VERSION 5.8 ;
BUSBITCHARS "[]" ;
DIVIDERCHAR "/" ;
UNITS
    DATABASE MICRONS 1000 ;
END UNITS

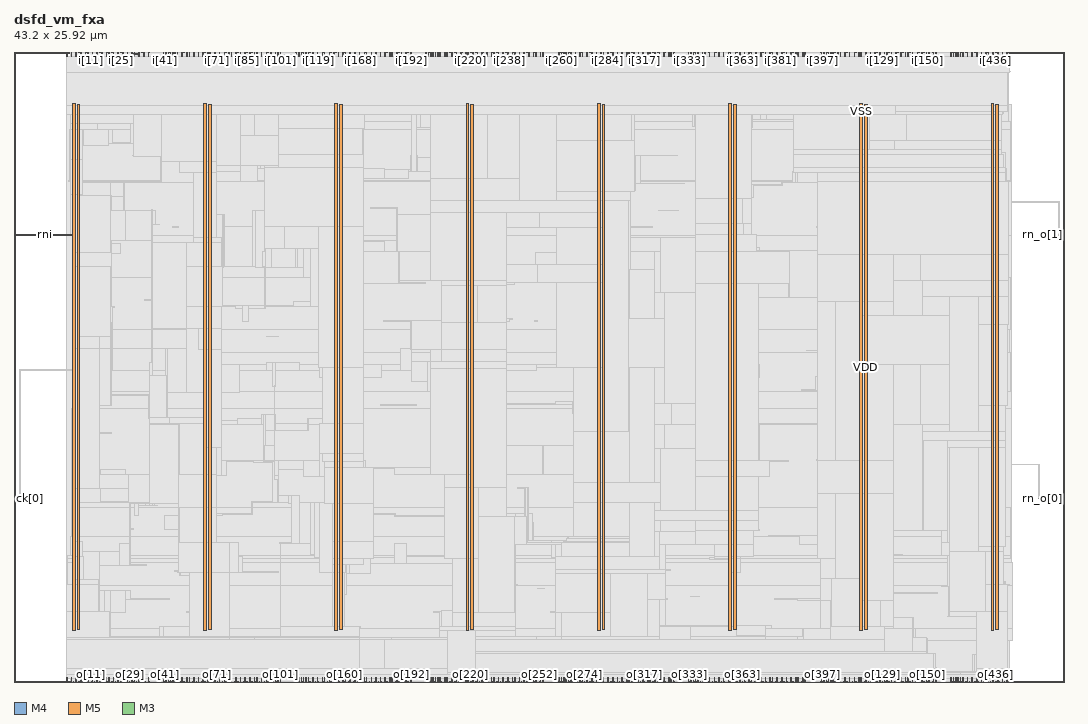
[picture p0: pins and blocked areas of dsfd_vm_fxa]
MACRO dsfd_vm_fxa
  FOREIGN dsfd_vm_fxa 0 0 ;
  CLASS BLOCK ;
  SIZE 43.2 BY 25.92 ;
  PIN ck[0]
    DIRECTION INPUT ;
    USE SIGNAL ;
    PORT
      LAYER M4 ;
        RECT  0 7.536 0.192 7.56 ;
    END
    PORT
      LAYER M4 ;
        RECT  0.156 7.536 0.275 7.56 ;
    END
  END ck[0]
  PIN i[0]
    DIRECTION INPUT ;
    USE SIGNAL ;
    PORT
      LAYER M5 ;
        RECT  2.16 25.728 2.184 25.92 ;
    END
  END i[0]
  PIN i[100]
    DIRECTION INPUT ;
    USE SIGNAL ;
    PORT
      LAYER M5 ;
        RECT  10.848 25.728 10.872 25.92 ;
    END
  END i[100]
  PIN i[101]
    DIRECTION INPUT ;
    USE SIGNAL ;
    PORT
      LAYER M3 ;
        RECT  10.944 25.882 10.962 25.92 ;
    END
  END i[101]
  PIN i[102]
    DIRECTION INPUT ;
    USE SIGNAL ;
    PORT
      LAYER M5 ;
        RECT  10.944 25.728 10.968 25.92 ;
    END
  END i[102]
  PIN i[103]
    DIRECTION INPUT ;
    USE SIGNAL ;
    PORT
      LAYER M3 ;
        RECT  11.592 25.882 11.61 25.92 ;
    END
  END i[103]
  PIN i[104]
    DIRECTION INPUT ;
    USE SIGNAL ;
    PORT
      LAYER M5 ;
        RECT  11.616 25.728 11.64 25.92 ;
    END
  END i[104]
  PIN i[105]
    DIRECTION INPUT ;
    USE SIGNAL ;
    PORT
      LAYER M3 ;
        RECT  11.664 25.882 11.682 25.92 ;
    END
  END i[105]
  PIN i[106]
    DIRECTION INPUT ;
    USE SIGNAL ;
    PORT
      LAYER M5 ;
        RECT  11.712 25.728 11.736 25.92 ;
    END
  END i[106]
  PIN i[107]
    DIRECTION INPUT ;
    USE SIGNAL ;
    PORT
      LAYER M3 ;
        RECT  11.736 25.882 11.754 25.92 ;
    END
  END i[107]
  PIN i[108]
    DIRECTION INPUT ;
    USE SIGNAL ;
    PORT
      LAYER M5 ;
        RECT  11.808 25.728 11.832 25.92 ;
    END
  END i[108]
  PIN i[109]
    DIRECTION INPUT ;
    USE SIGNAL ;
    PORT
      LAYER M3 ;
        RECT  11.808 25.882 11.826 25.92 ;
    END
  END i[109]
  PIN i[10]
    DIRECTION INPUT ;
    USE SIGNAL ;
    PORT
      LAYER M5 ;
        RECT  3.024 25.728 3.048 25.92 ;
    END
  END i[10]
  PIN i[110]
    DIRECTION INPUT ;
    USE SIGNAL ;
    PORT
      LAYER M5 ;
        RECT  11.904 25.728 11.928 25.92 ;
    END
  END i[110]
  PIN i[111]
    DIRECTION INPUT ;
    USE SIGNAL ;
    PORT
      LAYER M3 ;
        RECT  11.88 25.882 11.898 25.92 ;
    END
  END i[111]
  PIN i[112]
    DIRECTION INPUT ;
    USE SIGNAL ;
    PORT
      LAYER M5 ;
        RECT  12 25.728 12.024 25.92 ;
    END
  END i[112]
  PIN i[113]
    DIRECTION INPUT ;
    USE SIGNAL ;
    PORT
      LAYER M3 ;
        RECT  12.024 25.882 12.042 25.92 ;
    END
  END i[113]
  PIN i[114]
    DIRECTION INPUT ;
    USE SIGNAL ;
    PORT
      LAYER M5 ;
        RECT  12.096 25.728 12.12 25.92 ;
    END
  END i[114]
  PIN i[115]
    DIRECTION INPUT ;
    USE SIGNAL ;
    PORT
      LAYER M3 ;
        RECT  12.168 25.882 12.186 25.92 ;
    END
  END i[115]
  PIN i[116]
    DIRECTION INPUT ;
    USE SIGNAL ;
    PORT
      LAYER M5 ;
        RECT  12.288 25.728 12.312 25.92 ;
    END
  END i[116]
  PIN i[117]
    DIRECTION INPUT ;
    USE SIGNAL ;
    PORT
      LAYER M3 ;
        RECT  12.384 25.882 12.402 25.92 ;
    END
  END i[117]
  PIN i[118]
    DIRECTION INPUT ;
    USE SIGNAL ;
    PORT
      LAYER M5 ;
        RECT  12.48 25.728 12.504 25.92 ;
    END
  END i[118]
  PIN i[119]
    DIRECTION INPUT ;
    USE SIGNAL ;
    PORT
      LAYER M3 ;
        RECT  12.528 25.882 12.546 25.92 ;
    END
  END i[119]
  PIN i[11]
    DIRECTION INPUT ;
    USE SIGNAL ;
    PORT
      LAYER M3 ;
        RECT  3.168 25.882 3.186 25.92 ;
    END
  END i[11]
  PIN i[120]
    DIRECTION INPUT ;
    USE SIGNAL ;
    PORT
      LAYER M5 ;
        RECT  12.672 25.728 12.696 25.92 ;
    END
  END i[120]
  PIN i[121]
    DIRECTION INPUT ;
    USE SIGNAL ;
    PORT
      LAYER M3 ;
        RECT  12.744 25.882 12.762 25.92 ;
    END
  END i[121]
  PIN i[122]
    DIRECTION INPUT ;
    USE SIGNAL ;
    PORT
      LAYER M5 ;
        RECT  12.768 25.728 12.792 25.92 ;
    END
  END i[122]
  PIN i[123]
    DIRECTION INPUT ;
    USE SIGNAL ;
    PORT
      LAYER M3 ;
        RECT  12.888 25.882 12.906 25.92 ;
    END
  END i[123]
  PIN i[124]
    DIRECTION INPUT ;
    USE SIGNAL ;
    PORT
      LAYER M5 ;
        RECT  12.96 25.728 12.984 25.92 ;
    END
  END i[124]
  PIN i[125]
    DIRECTION INPUT ;
    USE SIGNAL ;
    PORT
      LAYER M3 ;
        RECT  13.032 25.882 13.05 25.92 ;
    END
  END i[125]
  PIN i[126]
    DIRECTION INPUT ;
    USE SIGNAL ;
    PORT
      LAYER M5 ;
        RECT  13.152 25.728 13.176 25.92 ;
    END
  END i[126]
  PIN i[127]
    DIRECTION INPUT ;
    USE SIGNAL ;
    PORT
      LAYER M3 ;
        RECT  13.248 25.882 13.266 25.92 ;
    END
  END i[127]
  PIN i[128]
    DIRECTION INPUT ;
    USE SIGNAL ;
    PORT
      LAYER M5 ;
        RECT  35.616 25.728 35.64 25.92 ;
    END
  END i[128]
  PIN i[129]
    DIRECTION INPUT ;
    USE SIGNAL ;
    PORT
      LAYER M3 ;
        RECT  35.712 25.882 35.73 25.92 ;
    END
  END i[129]
  PIN i[12]
    DIRECTION INPUT ;
    USE SIGNAL ;
    PORT
      LAYER M5 ;
        RECT  3.216 25.728 3.24 25.92 ;
    END
  END i[12]
  PIN i[130]
    DIRECTION INPUT ;
    USE SIGNAL ;
    PORT
      LAYER M5 ;
        RECT  35.808 25.728 35.832 25.92 ;
    END
  END i[130]
  PIN i[131]
    DIRECTION INPUT ;
    USE SIGNAL ;
    PORT
      LAYER M3 ;
        RECT  35.856 25.882 35.874 25.92 ;
    END
  END i[131]
  PIN i[132]
    DIRECTION INPUT ;
    USE SIGNAL ;
    PORT
      LAYER M5 ;
        RECT  35.904 25.728 35.928 25.92 ;
    END
  END i[132]
  PIN i[133]
    DIRECTION INPUT ;
    USE SIGNAL ;
    PORT
      LAYER M3 ;
        RECT  36 25.882 36.018 25.92 ;
    END
  END i[133]
  PIN i[134]
    DIRECTION INPUT ;
    USE SIGNAL ;
    PORT
      LAYER M5 ;
        RECT  36.096 25.728 36.12 25.92 ;
    END
  END i[134]
  PIN i[135]
    DIRECTION INPUT ;
    USE SIGNAL ;
    PORT
      LAYER M3 ;
        RECT  36.216 25.882 36.234 25.92 ;
    END
  END i[135]
  PIN i[136]
    DIRECTION INPUT ;
    USE SIGNAL ;
    PORT
      LAYER M5 ;
        RECT  36.288 25.728 36.312 25.92 ;
    END
  END i[136]
  PIN i[137]
    DIRECTION INPUT ;
    USE SIGNAL ;
    PORT
      LAYER M3 ;
        RECT  36.36 25.882 36.378 25.92 ;
    END
  END i[137]
  PIN i[138]
    DIRECTION INPUT ;
    USE SIGNAL ;
    PORT
      LAYER M5 ;
        RECT  36.48 25.728 36.504 25.92 ;
    END
  END i[138]
  PIN i[139]
    DIRECTION INPUT ;
    USE SIGNAL ;
    PORT
      LAYER M3 ;
        RECT  36.576 25.882 36.594 25.92 ;
    END
  END i[139]
  PIN i[13]
    DIRECTION INPUT ;
    USE SIGNAL ;
    PORT
      LAYER M3 ;
        RECT  3.312 25.882 3.33 25.92 ;
    END
  END i[13]
  PIN i[140]
    DIRECTION INPUT ;
    USE SIGNAL ;
    PORT
      LAYER M5 ;
        RECT  36.672 25.728 36.696 25.92 ;
    END
  END i[140]
  PIN i[141]
    DIRECTION INPUT ;
    USE SIGNAL ;
    PORT
      LAYER M3 ;
        RECT  36.72 25.882 36.738 25.92 ;
    END
  END i[141]
  PIN i[142]
    DIRECTION INPUT ;
    USE SIGNAL ;
    PORT
      LAYER M5 ;
        RECT  36.768 25.728 36.792 25.92 ;
    END
  END i[142]
  PIN i[143]
    DIRECTION INPUT ;
    USE SIGNAL ;
    PORT
      LAYER M5 ;
        RECT  36.96 25.728 36.984 25.92 ;
    END
  END i[143]
  PIN i[144]
    DIRECTION INPUT ;
    USE SIGNAL ;
    PORT
      LAYER M3 ;
        RECT  37.08 25.882 37.098 25.92 ;
    END
  END i[144]
  PIN i[145]
    DIRECTION INPUT ;
    USE SIGNAL ;
    PORT
      LAYER M5 ;
        RECT  37.152 25.728 37.176 25.92 ;
    END
  END i[145]
  PIN i[146]
    DIRECTION INPUT ;
    USE SIGNAL ;
    PORT
      LAYER M3 ;
        RECT  37.224 25.882 37.242 25.92 ;
    END
  END i[146]
  PIN i[147]
    DIRECTION INPUT ;
    USE SIGNAL ;
    PORT
      LAYER M5 ;
        RECT  37.344 25.728 37.368 25.92 ;
    END
  END i[147]
  PIN i[148]
    DIRECTION INPUT ;
    USE SIGNAL ;
    PORT
      LAYER M3 ;
        RECT  37.44 25.882 37.458 25.92 ;
    END
  END i[148]
  PIN i[149]
    DIRECTION INPUT ;
    USE SIGNAL ;
    PORT
      LAYER M5 ;
        RECT  37.536 25.728 37.56 25.92 ;
    END
  END i[149]
  PIN i[14]
    DIRECTION INPUT ;
    USE SIGNAL ;
    PORT
      LAYER M5 ;
        RECT  3.408 25.728 3.432 25.92 ;
    END
  END i[14]
  PIN i[150]
    DIRECTION INPUT ;
    USE SIGNAL ;
    PORT
      LAYER M3 ;
        RECT  37.584 25.882 37.602 25.92 ;
    END
  END i[150]
  PIN i[151]
    DIRECTION INPUT ;
    USE SIGNAL ;
    PORT
      LAYER M5 ;
        RECT  37.632 25.728 37.656 25.92 ;
    END
  END i[151]
  PIN i[152]
    DIRECTION INPUT ;
    USE SIGNAL ;
    PORT
      LAYER M3 ;
        RECT  37.8 25.882 37.818 25.92 ;
    END
  END i[152]
  PIN i[153]
    DIRECTION INPUT ;
    USE SIGNAL ;
    PORT
      LAYER M5 ;
        RECT  37.824 25.728 37.848 25.92 ;
    END
  END i[153]
  PIN i[154]
    DIRECTION INPUT ;
    USE SIGNAL ;
    PORT
      LAYER M3 ;
        RECT  37.944 25.882 37.962 25.92 ;
    END
  END i[154]
  PIN i[155]
    DIRECTION INPUT ;
    USE SIGNAL ;
    PORT
      LAYER M5 ;
        RECT  37.92 25.728 37.944 25.92 ;
    END
  END i[155]
  PIN i[156]
    DIRECTION INPUT ;
    USE SIGNAL ;
    PORT
      LAYER M3 ;
        RECT  38.592 25.882 38.61 25.92 ;
    END
  END i[156]
  PIN i[157]
    DIRECTION INPUT ;
    USE SIGNAL ;
    PORT
      LAYER M5 ;
        RECT  13.344 25.728 13.368 25.92 ;
    END
  END i[157]
  PIN i[158]
    DIRECTION INPUT ;
    USE SIGNAL ;
    PORT
      LAYER M3 ;
        RECT  13.392 25.882 13.41 25.92 ;
    END
  END i[158]
  PIN i[159]
    DIRECTION INPUT ;
    USE SIGNAL ;
    PORT
      LAYER M5 ;
        RECT  13.536 25.728 13.56 25.92 ;
    END
  END i[159]
  PIN i[15]
    DIRECTION INPUT ;
    USE SIGNAL ;
    PORT
      LAYER M3 ;
        RECT  3.528 25.882 3.546 25.92 ;
    END
  END i[15]
  PIN i[160]
    DIRECTION INPUT ;
    USE SIGNAL ;
    PORT
      LAYER M3 ;
        RECT  13.608 25.882 13.626 25.92 ;
    END
  END i[160]
  PIN i[161]
    DIRECTION INPUT ;
    USE SIGNAL ;
    PORT
      LAYER M5 ;
        RECT  13.632 25.728 13.656 25.92 ;
    END
  END i[161]
  PIN i[162]
    DIRECTION INPUT ;
    USE SIGNAL ;
    PORT
      LAYER M3 ;
        RECT  13.752 25.882 13.77 25.92 ;
    END
  END i[162]
  PIN i[163]
    DIRECTION INPUT ;
    USE SIGNAL ;
    PORT
      LAYER M5 ;
        RECT  13.824 25.728 13.848 25.92 ;
    END
  END i[163]
  PIN i[164]
    DIRECTION INPUT ;
    USE SIGNAL ;
    PORT
      LAYER M3 ;
        RECT  13.968 25.882 13.986 25.92 ;
    END
  END i[164]
  PIN i[165]
    DIRECTION INPUT ;
    USE SIGNAL ;
    PORT
      LAYER M5 ;
        RECT  14.016 25.728 14.04 25.92 ;
    END
  END i[165]
  PIN i[166]
    DIRECTION INPUT ;
    USE SIGNAL ;
    PORT
      LAYER M3 ;
        RECT  14.112 25.882 14.13 25.92 ;
    END
  END i[166]
  PIN i[167]
    DIRECTION INPUT ;
    USE SIGNAL ;
    PORT
      LAYER M5 ;
        RECT  14.208 25.728 14.232 25.92 ;
    END
  END i[167]
  PIN i[168]
    DIRECTION INPUT ;
    USE SIGNAL ;
    PORT
      LAYER M3 ;
        RECT  14.256 25.882 14.274 25.92 ;
    END
  END i[168]
  PIN i[169]
    DIRECTION INPUT ;
    USE SIGNAL ;
    PORT
      LAYER M5 ;
        RECT  14.4 25.728 14.424 25.92 ;
    END
  END i[169]
  PIN i[16]
    DIRECTION INPUT ;
    USE SIGNAL ;
    PORT
      LAYER M5 ;
        RECT  3.6 25.728 3.624 25.92 ;
    END
  END i[16]
  PIN i[170]
    DIRECTION INPUT ;
    USE SIGNAL ;
    PORT
      LAYER M3 ;
        RECT  14.472 25.882 14.49 25.92 ;
    END
  END i[170]
  PIN i[171]
    DIRECTION INPUT ;
    USE SIGNAL ;
    PORT
      LAYER M5 ;
        RECT  14.496 25.728 14.52 25.92 ;
    END
  END i[171]
  PIN i[172]
    DIRECTION INPUT ;
    USE SIGNAL ;
    PORT
      LAYER M3 ;
        RECT  14.616 25.882 14.634 25.92 ;
    END
  END i[172]
  PIN i[173]
    DIRECTION INPUT ;
    USE SIGNAL ;
    PORT
      LAYER M5 ;
        RECT  14.688 25.728 14.712 25.92 ;
    END
  END i[173]
  PIN i[174]
    DIRECTION INPUT ;
    USE SIGNAL ;
    PORT
      LAYER M3 ;
        RECT  14.832 25.882 14.85 25.92 ;
    END
  END i[174]
  PIN i[175]
    DIRECTION INPUT ;
    USE SIGNAL ;
    PORT
      LAYER M5 ;
        RECT  14.88 25.728 14.904 25.92 ;
    END
  END i[175]
  PIN i[176]
    DIRECTION INPUT ;
    USE SIGNAL ;
    PORT
      LAYER M3 ;
        RECT  14.976 25.882 14.994 25.92 ;
    END
  END i[176]
  PIN i[177]
    DIRECTION INPUT ;
    USE SIGNAL ;
    PORT
      LAYER M5 ;
        RECT  15.072 25.728 15.096 25.92 ;
    END
  END i[177]
  PIN i[178]
    DIRECTION INPUT ;
    USE SIGNAL ;
    PORT
      LAYER M3 ;
        RECT  15.12 25.882 15.138 25.92 ;
    END
  END i[178]
  PIN i[179]
    DIRECTION INPUT ;
    USE SIGNAL ;
    PORT
      LAYER M5 ;
        RECT  15.264 25.728 15.288 25.92 ;
    END
  END i[179]
  PIN i[17]
    DIRECTION INPUT ;
    USE SIGNAL ;
    PORT
      LAYER M3 ;
        RECT  3.672 25.882 3.69 25.92 ;
    END
  END i[17]
  PIN i[180]
    DIRECTION INPUT ;
    USE SIGNAL ;
    PORT
      LAYER M3 ;
        RECT  15.336 25.882 15.354 25.92 ;
    END
  END i[180]
  PIN i[181]
    DIRECTION INPUT ;
    USE SIGNAL ;
    PORT
      LAYER M5 ;
        RECT  15.456 25.728 15.48 25.92 ;
    END
  END i[181]
  PIN i[182]
    DIRECTION INPUT ;
    USE SIGNAL ;
    PORT
      LAYER M3 ;
        RECT  15.48 25.882 15.498 25.92 ;
    END
  END i[182]
  PIN i[183]
    DIRECTION INPUT ;
    USE SIGNAL ;
    PORT
      LAYER M5 ;
        RECT  15.552 25.728 15.576 25.92 ;
    END
  END i[183]
  PIN i[184]
    DIRECTION INPUT ;
    USE SIGNAL ;
    PORT
      LAYER M3 ;
        RECT  15.696 25.882 15.714 25.92 ;
    END
  END i[184]
  PIN i[185]
    DIRECTION INPUT ;
    USE SIGNAL ;
    PORT
      LAYER M5 ;
        RECT  15.744 25.728 15.768 25.92 ;
    END
  END i[185]
  PIN i[186]
    DIRECTION INPUT ;
    USE SIGNAL ;
    PORT
      LAYER M3 ;
        RECT  15.84 25.882 15.858 25.92 ;
    END
  END i[186]
  PIN i[187]
    DIRECTION INPUT ;
    USE SIGNAL ;
    PORT
      LAYER M5 ;
        RECT  15.936 25.728 15.96 25.92 ;
    END
  END i[187]
  PIN i[188]
    DIRECTION INPUT ;
    USE SIGNAL ;
    PORT
      LAYER M3 ;
        RECT  16.056 25.882 16.074 25.92 ;
    END
  END i[188]
  PIN i[189]
    DIRECTION INPUT ;
    USE SIGNAL ;
    PORT
      LAYER M5 ;
        RECT  16.128 25.728 16.152 25.92 ;
    END
  END i[189]
  PIN i[18]
    DIRECTION INPUT ;
    USE SIGNAL ;
    PORT
      LAYER M5 ;
        RECT  3.792 25.728 3.816 25.92 ;
    END
  END i[18]
  PIN i[190]
    DIRECTION INPUT ;
    USE SIGNAL ;
    PORT
      LAYER M3 ;
        RECT  16.2 25.882 16.218 25.92 ;
    END
  END i[190]
  PIN i[191]
    DIRECTION INPUT ;
    USE SIGNAL ;
    PORT
      LAYER M5 ;
        RECT  16.32 25.728 16.344 25.92 ;
    END
  END i[191]
  PIN i[192]
    DIRECTION INPUT ;
    USE SIGNAL ;
    PORT
      LAYER M3 ;
        RECT  16.344 25.882 16.362 25.92 ;
    END
  END i[192]
  PIN i[193]
    DIRECTION INPUT ;
    USE SIGNAL ;
    PORT
      LAYER M5 ;
        RECT  16.944 25.728 16.968 25.92 ;
    END
  END i[193]
  PIN i[194]
    DIRECTION INPUT ;
    USE SIGNAL ;
    PORT
      LAYER M3 ;
        RECT  16.992 25.882 17.01 25.92 ;
    END
  END i[194]
  PIN i[195]
    DIRECTION INPUT ;
    USE SIGNAL ;
    PORT
      LAYER M5 ;
        RECT  17.04 25.728 17.064 25.92 ;
    END
  END i[195]
  PIN i[196]
    DIRECTION INPUT ;
    USE SIGNAL ;
    PORT
      LAYER M3 ;
        RECT  17.064 25.882 17.082 25.92 ;
    END
  END i[196]
  PIN i[197]
    DIRECTION INPUT ;
    USE SIGNAL ;
    PORT
      LAYER M5 ;
        RECT  17.136 25.728 17.16 25.92 ;
    END
  END i[197]
  PIN i[198]
    DIRECTION INPUT ;
    USE SIGNAL ;
    PORT
      LAYER M3 ;
        RECT  17.136 25.882 17.154 25.92 ;
    END
  END i[198]
  PIN i[199]
    DIRECTION INPUT ;
    USE SIGNAL ;
    PORT
      LAYER M5 ;
        RECT  17.232 25.728 17.256 25.92 ;
    END
  END i[199]
  PIN i[19]
    DIRECTION INPUT ;
    USE SIGNAL ;
    PORT
      LAYER M3 ;
        RECT  3.816 25.882 3.834 25.92 ;
    END
  END i[19]
  PIN i[1]
    DIRECTION INPUT ;
    USE SIGNAL ;
    PORT
      LAYER M3 ;
        RECT  2.304 25.882 2.322 25.92 ;
    END
  END i[1]
  PIN i[200]
    DIRECTION INPUT ;
    USE SIGNAL ;
    PORT
      LAYER M3 ;
        RECT  17.208 25.882 17.226 25.92 ;
    END
  END i[200]
  PIN i[201]
    DIRECTION INPUT ;
    USE SIGNAL ;
    PORT
      LAYER M5 ;
        RECT  17.328 25.728 17.352 25.92 ;
    END
  END i[201]
  PIN i[202]
    DIRECTION INPUT ;
    USE SIGNAL ;
    PORT
      LAYER M3 ;
        RECT  17.28 25.882 17.298 25.92 ;
    END
  END i[202]
  PIN i[203]
    DIRECTION INPUT ;
    USE SIGNAL ;
    PORT
      LAYER M5 ;
        RECT  17.424 25.728 17.448 25.92 ;
    END
  END i[203]
  PIN i[204]
    DIRECTION INPUT ;
    USE SIGNAL ;
    PORT
      LAYER M3 ;
        RECT  17.424 25.882 17.442 25.92 ;
    END
  END i[204]
  PIN i[205]
    DIRECTION INPUT ;
    USE SIGNAL ;
    PORT
      LAYER M5 ;
        RECT  17.52 25.728 17.544 25.92 ;
    END
  END i[205]
  PIN i[206]
    DIRECTION INPUT ;
    USE SIGNAL ;
    PORT
      LAYER M3 ;
        RECT  17.568 25.882 17.586 25.92 ;
    END
  END i[206]
  PIN i[207]
    DIRECTION INPUT ;
    USE SIGNAL ;
    PORT
      LAYER M5 ;
        RECT  17.712 25.728 17.736 25.92 ;
    END
  END i[207]
  PIN i[208]
    DIRECTION INPUT ;
    USE SIGNAL ;
    PORT
      LAYER M3 ;
        RECT  17.784 25.882 17.802 25.92 ;
    END
  END i[208]
  PIN i[209]
    DIRECTION INPUT ;
    USE SIGNAL ;
    PORT
      LAYER M5 ;
        RECT  17.808 25.728 17.832 25.92 ;
    END
  END i[209]
  PIN i[20]
    DIRECTION INPUT ;
    USE SIGNAL ;
    PORT
      LAYER M5 ;
        RECT  3.888 25.728 3.912 25.92 ;
    END
  END i[20]
  PIN i[210]
    DIRECTION INPUT ;
    USE SIGNAL ;
    PORT
      LAYER M3 ;
        RECT  17.928 25.882 17.946 25.92 ;
    END
  END i[210]
  PIN i[211]
    DIRECTION INPUT ;
    USE SIGNAL ;
    PORT
      LAYER M5 ;
        RECT  18 25.728 18.024 25.92 ;
    END
  END i[211]
  PIN i[212]
    DIRECTION INPUT ;
    USE SIGNAL ;
    PORT
      LAYER M3 ;
        RECT  18.144 25.882 18.162 25.92 ;
    END
  END i[212]
  PIN i[213]
    DIRECTION INPUT ;
    USE SIGNAL ;
    PORT
      LAYER M5 ;
        RECT  18.192 25.728 18.216 25.92 ;
    END
  END i[213]
  PIN i[214]
    DIRECTION INPUT ;
    USE SIGNAL ;
    PORT
      LAYER M3 ;
        RECT  18.288 25.882 18.306 25.92 ;
    END
  END i[214]
  PIN i[215]
    DIRECTION INPUT ;
    USE SIGNAL ;
    PORT
      LAYER M5 ;
        RECT  18.384 25.728 18.408 25.92 ;
    END
  END i[215]
  PIN i[216]
    DIRECTION INPUT ;
    USE SIGNAL ;
    PORT
      LAYER M3 ;
        RECT  18.432 25.882 18.45 25.92 ;
    END
  END i[216]
  PIN i[217]
    DIRECTION INPUT ;
    USE SIGNAL ;
    PORT
      LAYER M5 ;
        RECT  18.576 25.728 18.6 25.92 ;
    END
  END i[217]
  PIN i[218]
    DIRECTION INPUT ;
    USE SIGNAL ;
    PORT
      LAYER M3 ;
        RECT  18.648 25.882 18.666 25.92 ;
    END
  END i[218]
  PIN i[219]
    DIRECTION INPUT ;
    USE SIGNAL ;
    PORT
      LAYER M5 ;
        RECT  18.672 25.728 18.696 25.92 ;
    END
  END i[219]
  PIN i[21]
    DIRECTION INPUT ;
    USE SIGNAL ;
    PORT
      LAYER M3 ;
        RECT  4.032 25.882 4.05 25.92 ;
    END
  END i[21]
  PIN i[220]
    DIRECTION INPUT ;
    USE SIGNAL ;
    PORT
      LAYER M3 ;
        RECT  18.792 25.882 18.81 25.92 ;
    END
  END i[220]
  PIN i[221]
    DIRECTION INPUT ;
    USE SIGNAL ;
    PORT
      LAYER M5 ;
        RECT  18.864 25.728 18.888 25.92 ;
    END
  END i[221]
  PIN i[222]
    DIRECTION INPUT ;
    USE SIGNAL ;
    PORT
      LAYER M3 ;
        RECT  19.008 25.882 19.026 25.92 ;
    END
  END i[222]
  PIN i[223]
    DIRECTION INPUT ;
    USE SIGNAL ;
    PORT
      LAYER M5 ;
        RECT  19.056 25.728 19.08 25.92 ;
    END
  END i[223]
  PIN i[224]
    DIRECTION INPUT ;
    USE SIGNAL ;
    PORT
      LAYER M3 ;
        RECT  19.152 25.882 19.17 25.92 ;
    END
  END i[224]
  PIN i[225]
    DIRECTION INPUT ;
    USE SIGNAL ;
    PORT
      LAYER M5 ;
        RECT  19.248 25.728 19.272 25.92 ;
    END
  END i[225]
  PIN i[226]
    DIRECTION INPUT ;
    USE SIGNAL ;
    PORT
      LAYER M3 ;
        RECT  19.296 25.882 19.314 25.92 ;
    END
  END i[226]
  PIN i[227]
    DIRECTION INPUT ;
    USE SIGNAL ;
    PORT
      LAYER M5 ;
        RECT  19.44 25.728 19.464 25.92 ;
    END
  END i[227]
  PIN i[228]
    DIRECTION INPUT ;
    USE SIGNAL ;
    PORT
      LAYER M3 ;
        RECT  19.512 25.882 19.53 25.92 ;
    END
  END i[228]
  PIN i[229]
    DIRECTION INPUT ;
    USE SIGNAL ;
    PORT
      LAYER M5 ;
        RECT  19.632 25.728 19.656 25.92 ;
    END
  END i[229]
  PIN i[22]
    DIRECTION INPUT ;
    USE SIGNAL ;
    PORT
      LAYER M5 ;
        RECT  4.08 25.728 4.104 25.92 ;
    END
  END i[22]
  PIN i[230]
    DIRECTION INPUT ;
    USE SIGNAL ;
    PORT
      LAYER M3 ;
        RECT  19.656 25.882 19.674 25.92 ;
    END
  END i[230]
  PIN i[231]
    DIRECTION INPUT ;
    USE SIGNAL ;
    PORT
      LAYER M5 ;
        RECT  19.728 25.728 19.752 25.92 ;
    END
  END i[231]
  PIN i[232]
    DIRECTION INPUT ;
    USE SIGNAL ;
    PORT
      LAYER M3 ;
        RECT  19.872 25.882 19.89 25.92 ;
    END
  END i[232]
  PIN i[233]
    DIRECTION INPUT ;
    USE SIGNAL ;
    PORT
      LAYER M5 ;
        RECT  19.92 25.728 19.944 25.92 ;
    END
  END i[233]
  PIN i[234]
    DIRECTION INPUT ;
    USE SIGNAL ;
    PORT
      LAYER M3 ;
        RECT  20.016 25.882 20.034 25.92 ;
    END
  END i[234]
  PIN i[235]
    DIRECTION INPUT ;
    USE SIGNAL ;
    PORT
      LAYER M5 ;
        RECT  20.112 25.728 20.136 25.92 ;
    END
  END i[235]
  PIN i[236]
    DIRECTION INPUT ;
    USE SIGNAL ;
    PORT
      LAYER M3 ;
        RECT  20.232 25.882 20.25 25.92 ;
    END
  END i[236]
  PIN i[237]
    DIRECTION INPUT ;
    USE SIGNAL ;
    PORT
      LAYER M5 ;
        RECT  20.304 25.728 20.328 25.92 ;
    END
  END i[237]
  PIN i[238]
    DIRECTION INPUT ;
    USE SIGNAL ;
    PORT
      LAYER M3 ;
        RECT  20.376 25.882 20.394 25.92 ;
    END
  END i[238]
  PIN i[239]
    DIRECTION INPUT ;
    USE SIGNAL ;
    PORT
      LAYER M5 ;
        RECT  20.496 25.728 20.52 25.92 ;
    END
  END i[239]
  PIN i[23]
    DIRECTION INPUT ;
    USE SIGNAL ;
    PORT
      LAYER M3 ;
        RECT  4.176 25.882 4.194 25.92 ;
    END
  END i[23]
  PIN i[240]
    DIRECTION INPUT ;
    USE SIGNAL ;
    PORT
      LAYER M3 ;
        RECT  20.52 25.882 20.538 25.92 ;
    END
  END i[240]
  PIN i[241]
    DIRECTION INPUT ;
    USE SIGNAL ;
    PORT
      LAYER M5 ;
        RECT  20.592 25.728 20.616 25.92 ;
    END
  END i[241]
  PIN i[242]
    DIRECTION INPUT ;
    USE SIGNAL ;
    PORT
      LAYER M3 ;
        RECT  20.736 25.882 20.754 25.92 ;
    END
  END i[242]
  PIN i[243]
    DIRECTION INPUT ;
    USE SIGNAL ;
    PORT
      LAYER M5 ;
        RECT  20.784 25.728 20.808 25.92 ;
    END
  END i[243]
  PIN i[244]
    DIRECTION INPUT ;
    USE SIGNAL ;
    PORT
      LAYER M3 ;
        RECT  20.88 25.882 20.898 25.92 ;
    END
  END i[244]
  PIN i[245]
    DIRECTION INPUT ;
    USE SIGNAL ;
    PORT
      LAYER M5 ;
        RECT  20.976 25.728 21 25.92 ;
    END
  END i[245]
  PIN i[246]
    DIRECTION INPUT ;
    USE SIGNAL ;
    PORT
      LAYER M3 ;
        RECT  21.096 25.882 21.114 25.92 ;
    END
  END i[246]
  PIN i[247]
    DIRECTION INPUT ;
    USE SIGNAL ;
    PORT
      LAYER M5 ;
        RECT  21.168 25.728 21.192 25.92 ;
    END
  END i[247]
  PIN i[248]
    DIRECTION INPUT ;
    USE SIGNAL ;
    PORT
      LAYER M3 ;
        RECT  21.24 25.882 21.258 25.92 ;
    END
  END i[248]
  PIN i[249]
    DIRECTION INPUT ;
    USE SIGNAL ;
    PORT
      LAYER M5 ;
        RECT  21.36 25.728 21.384 25.92 ;
    END
  END i[249]
  PIN i[24]
    DIRECTION INPUT ;
    USE SIGNAL ;
    PORT
      LAYER M5 ;
        RECT  4.272 25.728 4.296 25.92 ;
    END
  END i[24]
  PIN i[250]
    DIRECTION INPUT ;
    USE SIGNAL ;
    PORT
      LAYER M3 ;
        RECT  21.384 25.882 21.402 25.92 ;
    END
  END i[250]
  PIN i[251]
    DIRECTION INPUT ;
    USE SIGNAL ;
    PORT
      LAYER M5 ;
        RECT  21.456 25.728 21.48 25.92 ;
    END
  END i[251]
  PIN i[252]
    DIRECTION INPUT ;
    USE SIGNAL ;
    PORT
      LAYER M3 ;
        RECT  21.6 25.882 21.618 25.92 ;
    END
  END i[252]
  PIN i[253]
    DIRECTION INPUT ;
    USE SIGNAL ;
    PORT
      LAYER M5 ;
        RECT  21.648 25.728 21.672 25.92 ;
    END
  END i[253]
  PIN i[254]
    DIRECTION INPUT ;
    USE SIGNAL ;
    PORT
      LAYER M3 ;
        RECT  21.744 25.882 21.762 25.92 ;
    END
  END i[254]
  PIN i[255]
    DIRECTION INPUT ;
    USE SIGNAL ;
    PORT
      LAYER M5 ;
        RECT  21.744 25.728 21.768 25.92 ;
    END
  END i[255]
  PIN i[256]
    DIRECTION INPUT ;
    USE SIGNAL ;
    PORT
      LAYER M3 ;
        RECT  22.392 25.882 22.41 25.92 ;
    END
  END i[256]
  PIN i[257]
    DIRECTION INPUT ;
    USE SIGNAL ;
    PORT
      LAYER M5 ;
        RECT  22.416 25.728 22.44 25.92 ;
    END
  END i[257]
  PIN i[258]
    DIRECTION INPUT ;
    USE SIGNAL ;
    PORT
      LAYER M3 ;
        RECT  22.464 25.882 22.482 25.92 ;
    END
  END i[258]
  PIN i[259]
    DIRECTION INPUT ;
    USE SIGNAL ;
    PORT
      LAYER M5 ;
        RECT  22.512 25.728 22.536 25.92 ;
    END
  END i[259]
  PIN i[25]
    DIRECTION INPUT ;
    USE SIGNAL ;
    PORT
      LAYER M3 ;
        RECT  4.392 25.882 4.41 25.92 ;
    END
  END i[25]
  PIN i[260]
    DIRECTION INPUT ;
    USE SIGNAL ;
    PORT
      LAYER M3 ;
        RECT  22.536 25.882 22.554 25.92 ;
    END
  END i[260]
  PIN i[261]
    DIRECTION INPUT ;
    USE SIGNAL ;
    PORT
      LAYER M5 ;
        RECT  22.608 25.728 22.632 25.92 ;
    END
  END i[261]
  PIN i[262]
    DIRECTION INPUT ;
    USE SIGNAL ;
    PORT
      LAYER M3 ;
        RECT  22.608 25.882 22.626 25.92 ;
    END
  END i[262]
  PIN i[263]
    DIRECTION INPUT ;
    USE SIGNAL ;
    PORT
      LAYER M5 ;
        RECT  22.704 25.728 22.728 25.92 ;
    END
  END i[263]
  PIN i[264]
    DIRECTION INPUT ;
    USE SIGNAL ;
    PORT
      LAYER M3 ;
        RECT  22.68 25.882 22.698 25.92 ;
    END
  END i[264]
  PIN i[265]
    DIRECTION INPUT ;
    USE SIGNAL ;
    PORT
      LAYER M5 ;
        RECT  22.8 25.728 22.824 25.92 ;
    END
  END i[265]
  PIN i[266]
    DIRECTION INPUT ;
    USE SIGNAL ;
    PORT
      LAYER M3 ;
        RECT  22.824 25.882 22.842 25.92 ;
    END
  END i[266]
  PIN i[267]
    DIRECTION INPUT ;
    USE SIGNAL ;
    PORT
      LAYER M5 ;
        RECT  22.896 25.728 22.92 25.92 ;
    END
  END i[267]
  PIN i[268]
    DIRECTION INPUT ;
    USE SIGNAL ;
    PORT
      LAYER M3 ;
        RECT  22.968 25.882 22.986 25.92 ;
    END
  END i[268]
  PIN i[269]
    DIRECTION INPUT ;
    USE SIGNAL ;
    PORT
      LAYER M5 ;
        RECT  23.088 25.728 23.112 25.92 ;
    END
  END i[269]
  PIN i[26]
    DIRECTION INPUT ;
    USE SIGNAL ;
    PORT
      LAYER M5 ;
        RECT  4.464 25.728 4.488 25.92 ;
    END
  END i[26]
  PIN i[270]
    DIRECTION INPUT ;
    USE SIGNAL ;
    PORT
      LAYER M3 ;
        RECT  23.184 25.882 23.202 25.92 ;
    END
  END i[270]
  PIN i[271]
    DIRECTION INPUT ;
    USE SIGNAL ;
    PORT
      LAYER M5 ;
        RECT  23.28 25.728 23.304 25.92 ;
    END
  END i[271]
  PIN i[272]
    DIRECTION INPUT ;
    USE SIGNAL ;
    PORT
      LAYER M3 ;
        RECT  23.328 25.882 23.346 25.92 ;
    END
  END i[272]
  PIN i[273]
    DIRECTION INPUT ;
    USE SIGNAL ;
    PORT
      LAYER M5 ;
        RECT  23.376 25.728 23.4 25.92 ;
    END
  END i[273]
  PIN i[274]
    DIRECTION INPUT ;
    USE SIGNAL ;
    PORT
      LAYER M3 ;
        RECT  23.472 25.882 23.49 25.92 ;
    END
  END i[274]
  PIN i[275]
    DIRECTION INPUT ;
    USE SIGNAL ;
    PORT
      LAYER M5 ;
        RECT  23.568 25.728 23.592 25.92 ;
    END
  END i[275]
  PIN i[276]
    DIRECTION INPUT ;
    USE SIGNAL ;
    PORT
      LAYER M3 ;
        RECT  23.688 25.882 23.706 25.92 ;
    END
  END i[276]
  PIN i[277]
    DIRECTION INPUT ;
    USE SIGNAL ;
    PORT
      LAYER M5 ;
        RECT  23.76 25.728 23.784 25.92 ;
    END
  END i[277]
  PIN i[278]
    DIRECTION INPUT ;
    USE SIGNAL ;
    PORT
      LAYER M3 ;
        RECT  23.832 25.882 23.85 25.92 ;
    END
  END i[278]
  PIN i[279]
    DIRECTION INPUT ;
    USE SIGNAL ;
    PORT
      LAYER M5 ;
        RECT  23.952 25.728 23.976 25.92 ;
    END
  END i[279]
  PIN i[27]
    DIRECTION INPUT ;
    USE SIGNAL ;
    PORT
      LAYER M3 ;
        RECT  4.536 25.882 4.554 25.92 ;
    END
  END i[27]
  PIN i[280]
    DIRECTION INPUT ;
    USE SIGNAL ;
    PORT
      LAYER M3 ;
        RECT  24.048 25.882 24.066 25.92 ;
    END
  END i[280]
  PIN i[281]
    DIRECTION INPUT ;
    USE SIGNAL ;
    PORT
      LAYER M5 ;
        RECT  24.144 25.728 24.168 25.92 ;
    END
  END i[281]
  PIN i[282]
    DIRECTION INPUT ;
    USE SIGNAL ;
    PORT
      LAYER M3 ;
        RECT  24.192 25.882 24.21 25.92 ;
    END
  END i[282]
  PIN i[283]
    DIRECTION INPUT ;
    USE SIGNAL ;
    PORT
      LAYER M5 ;
        RECT  24.24 25.728 24.264 25.92 ;
    END
  END i[283]
  PIN i[284]
    DIRECTION INPUT ;
    USE SIGNAL ;
    PORT
      LAYER M3 ;
        RECT  24.408 25.882 24.426 25.92 ;
    END
  END i[284]
  PIN i[285]
    DIRECTION INPUT ;
    USE SIGNAL ;
    PORT
      LAYER M3 ;
        RECT  38.664 25.882 38.682 25.92 ;
    END
  END i[285]
  PIN i[286]
    DIRECTION INPUT ;
    USE SIGNAL ;
    PORT
      LAYER M5 ;
        RECT  38.64 25.728 38.664 25.92 ;
    END
  END i[286]
  PIN i[287]
    DIRECTION INPUT ;
    USE SIGNAL ;
    PORT
      LAYER M3 ;
        RECT  38.736 25.882 38.754 25.92 ;
    END
  END i[287]
  PIN i[288]
    DIRECTION INPUT ;
    USE SIGNAL ;
    PORT
      LAYER M5 ;
        RECT  38.736 25.728 38.76 25.92 ;
    END
  END i[288]
  PIN i[289]
    DIRECTION INPUT ;
    USE SIGNAL ;
    PORT
      LAYER M3 ;
        RECT  38.808 25.882 38.826 25.92 ;
    END
  END i[289]
  PIN i[28]
    DIRECTION INPUT ;
    USE SIGNAL ;
    PORT
      LAYER M5 ;
        RECT  4.656 25.728 4.68 25.92 ;
    END
  END i[28]
  PIN i[290]
    DIRECTION INPUT ;
    USE SIGNAL ;
    PORT
      LAYER M5 ;
        RECT  38.832 25.728 38.856 25.92 ;
    END
  END i[290]
  PIN i[291]
    DIRECTION INPUT ;
    USE SIGNAL ;
    PORT
      LAYER M3 ;
        RECT  38.88 25.882 38.898 25.92 ;
    END
  END i[291]
  PIN i[292]
    DIRECTION INPUT ;
    USE SIGNAL ;
    PORT
      LAYER M5 ;
        RECT  38.928 25.728 38.952 25.92 ;
    END
  END i[292]
  PIN i[293]
    DIRECTION INPUT ;
    USE SIGNAL ;
    PORT
      LAYER M3 ;
        RECT  38.952 25.882 38.97 25.92 ;
    END
  END i[293]
  PIN i[294]
    DIRECTION INPUT ;
    USE SIGNAL ;
    PORT
      LAYER M5 ;
        RECT  39.024 25.728 39.048 25.92 ;
    END
  END i[294]
  PIN i[295]
    DIRECTION INPUT ;
    USE SIGNAL ;
    PORT
      LAYER M3 ;
        RECT  39.168 25.882 39.186 25.92 ;
    END
  END i[295]
  PIN i[296]
    DIRECTION INPUT ;
    USE SIGNAL ;
    PORT
      LAYER M5 ;
        RECT  39.216 25.728 39.24 25.92 ;
    END
  END i[296]
  PIN i[297]
    DIRECTION INPUT ;
    USE SIGNAL ;
    PORT
      LAYER M3 ;
        RECT  39.312 25.882 39.33 25.92 ;
    END
  END i[297]
  PIN i[298]
    DIRECTION INPUT ;
    USE SIGNAL ;
    PORT
      LAYER M5 ;
        RECT  39.408 25.728 39.432 25.92 ;
    END
  END i[298]
  PIN i[299]
    DIRECTION INPUT ;
    USE SIGNAL ;
    PORT
      LAYER M3 ;
        RECT  39.528 25.882 39.546 25.92 ;
    END
  END i[299]
  PIN i[29]
    DIRECTION INPUT ;
    USE SIGNAL ;
    PORT
      LAYER M3 ;
        RECT  4.752 25.882 4.77 25.92 ;
    END
  END i[29]
  PIN i[2]
    DIRECTION INPUT ;
    USE SIGNAL ;
    PORT
      LAYER M5 ;
        RECT  2.352 25.728 2.376 25.92 ;
    END
  END i[2]
  PIN i[300]
    DIRECTION INPUT ;
    USE SIGNAL ;
    PORT
      LAYER M5 ;
        RECT  24.432 25.728 24.456 25.92 ;
    END
  END i[300]
  PIN i[301]
    DIRECTION INPUT ;
    USE SIGNAL ;
    PORT
      LAYER M3 ;
        RECT  24.552 25.882 24.57 25.92 ;
    END
  END i[301]
  PIN i[302]
    DIRECTION INPUT ;
    USE SIGNAL ;
    PORT
      LAYER M5 ;
        RECT  24.624 25.728 24.648 25.92 ;
    END
  END i[302]
  PIN i[303]
    DIRECTION INPUT ;
    USE SIGNAL ;
    PORT
      LAYER M3 ;
        RECT  24.696 25.882 24.714 25.92 ;
    END
  END i[303]
  PIN i[304]
    DIRECTION INPUT ;
    USE SIGNAL ;
    PORT
      LAYER M5 ;
        RECT  24.816 25.728 24.84 25.92 ;
    END
  END i[304]
  PIN i[305]
    DIRECTION INPUT ;
    USE SIGNAL ;
    PORT
      LAYER M3 ;
        RECT  24.912 25.882 24.93 25.92 ;
    END
  END i[305]
  PIN i[306]
    DIRECTION INPUT ;
    USE SIGNAL ;
    PORT
      LAYER M5 ;
        RECT  25.008 25.728 25.032 25.92 ;
    END
  END i[306]
  PIN i[307]
    DIRECTION INPUT ;
    USE SIGNAL ;
    PORT
      LAYER M3 ;
        RECT  25.056 25.882 25.074 25.92 ;
    END
  END i[307]
  PIN i[308]
    DIRECTION INPUT ;
    USE SIGNAL ;
    PORT
      LAYER M5 ;
        RECT  25.2 25.728 25.224 25.92 ;
    END
  END i[308]
  PIN i[309]
    DIRECTION INPUT ;
    USE SIGNAL ;
    PORT
      LAYER M3 ;
        RECT  25.272 25.882 25.29 25.92 ;
    END
  END i[309]
  PIN i[30]
    DIRECTION INPUT ;
    USE SIGNAL ;
    PORT
      LAYER M5 ;
        RECT  4.848 25.728 4.872 25.92 ;
    END
  END i[30]
  PIN i[310]
    DIRECTION INPUT ;
    USE SIGNAL ;
    PORT
      LAYER M5 ;
        RECT  25.296 25.728 25.32 25.92 ;
    END
  END i[310]
  PIN i[311]
    DIRECTION INPUT ;
    USE SIGNAL ;
    PORT
      LAYER M3 ;
        RECT  25.416 25.882 25.434 25.92 ;
    END
  END i[311]
  PIN i[312]
    DIRECTION INPUT ;
    USE SIGNAL ;
    PORT
      LAYER M5 ;
        RECT  25.488 25.728 25.512 25.92 ;
    END
  END i[312]
  PIN i[313]
    DIRECTION INPUT ;
    USE SIGNAL ;
    PORT
      LAYER M3 ;
        RECT  25.56 25.882 25.578 25.92 ;
    END
  END i[313]
  PIN i[314]
    DIRECTION INPUT ;
    USE SIGNAL ;
    PORT
      LAYER M5 ;
        RECT  25.68 25.728 25.704 25.92 ;
    END
  END i[314]
  PIN i[315]
    DIRECTION INPUT ;
    USE SIGNAL ;
    PORT
      LAYER M3 ;
        RECT  25.776 25.882 25.794 25.92 ;
    END
  END i[315]
  PIN i[316]
    DIRECTION INPUT ;
    USE SIGNAL ;
    PORT
      LAYER M5 ;
        RECT  25.872 25.728 25.896 25.92 ;
    END
  END i[316]
  PIN i[317]
    DIRECTION INPUT ;
    USE SIGNAL ;
    PORT
      LAYER M3 ;
        RECT  25.92 25.882 25.938 25.92 ;
    END
  END i[317]
  PIN i[318]
    DIRECTION INPUT ;
    USE SIGNAL ;
    PORT
      LAYER M5 ;
        RECT  26.064 25.728 26.088 25.92 ;
    END
  END i[318]
  PIN i[319]
    DIRECTION INPUT ;
    USE SIGNAL ;
    PORT
      LAYER M3 ;
        RECT  26.136 25.882 26.154 25.92 ;
    END
  END i[319]
  PIN i[31]
    DIRECTION INPUT ;
    USE SIGNAL ;
    PORT
      LAYER M3 ;
        RECT  4.896 25.882 4.914 25.92 ;
    END
  END i[31]
  PIN i[320]
    DIRECTION INPUT ;
    USE SIGNAL ;
    PORT
      LAYER M5 ;
        RECT  26.16 25.728 26.184 25.92 ;
    END
  END i[320]
  PIN i[321]
    DIRECTION INPUT ;
    USE SIGNAL ;
    PORT
      LAYER M3 ;
        RECT  26.28 25.882 26.298 25.92 ;
    END
  END i[321]
  PIN i[322]
    DIRECTION INPUT ;
    USE SIGNAL ;
    PORT
      LAYER M5 ;
        RECT  26.352 25.728 26.376 25.92 ;
    END
  END i[322]
  PIN i[323]
    DIRECTION INPUT ;
    USE SIGNAL ;
    PORT
      LAYER M3 ;
        RECT  26.496 25.882 26.514 25.92 ;
    END
  END i[323]
  PIN i[324]
    DIRECTION INPUT ;
    USE SIGNAL ;
    PORT
      LAYER M5 ;
        RECT  26.544 25.728 26.568 25.92 ;
    END
  END i[324]
  PIN i[325]
    DIRECTION INPUT ;
    USE SIGNAL ;
    PORT
      LAYER M3 ;
        RECT  26.64 25.882 26.658 25.92 ;
    END
  END i[325]
  PIN i[326]
    DIRECTION INPUT ;
    USE SIGNAL ;
    PORT
      LAYER M5 ;
        RECT  26.736 25.728 26.76 25.92 ;
    END
  END i[326]
  PIN i[327]
    DIRECTION INPUT ;
    USE SIGNAL ;
    PORT
      LAYER M3 ;
        RECT  26.784 25.882 26.802 25.92 ;
    END
  END i[327]
  PIN i[328]
    DIRECTION INPUT ;
    USE SIGNAL ;
    PORT
      LAYER M5 ;
        RECT  26.928 25.728 26.952 25.92 ;
    END
  END i[328]
  PIN i[329]
    DIRECTION INPUT ;
    USE SIGNAL ;
    PORT
      LAYER M3 ;
        RECT  27 25.882 27.018 25.92 ;
    END
  END i[329]
  PIN i[32]
    DIRECTION INPUT ;
    USE SIGNAL ;
    PORT
      LAYER M5 ;
        RECT  4.944 25.728 4.968 25.92 ;
    END
    PORT
      LAYER M5 ;
        RECT  4.896 25.811 5.064 25.859 ;
    END
  END i[32]
  PIN i[330]
    DIRECTION INPUT ;
    USE SIGNAL ;
    PORT
      LAYER M5 ;
        RECT  27.024 25.728 27.048 25.92 ;
    END
  END i[330]
  PIN i[331]
    DIRECTION INPUT ;
    USE SIGNAL ;
    PORT
      LAYER M3 ;
        RECT  27.144 25.882 27.162 25.92 ;
    END
  END i[331]
  PIN i[332]
    DIRECTION INPUT ;
    USE SIGNAL ;
    PORT
      LAYER M5 ;
        RECT  27.12 25.728 27.144 25.92 ;
    END
  END i[332]
  PIN i[333]
    DIRECTION INPUT ;
    USE SIGNAL ;
    PORT
      LAYER M3 ;
        RECT  27.792 25.882 27.81 25.92 ;
    END
  END i[333]
  PIN i[334]
    DIRECTION INPUT ;
    USE SIGNAL ;
    PORT
      LAYER M5 ;
        RECT  27.744 25.728 27.768 25.92 ;
    END
  END i[334]
  PIN i[335]
    DIRECTION INPUT ;
    USE SIGNAL ;
    PORT
      LAYER M3 ;
        RECT  27.864 25.882 27.882 25.92 ;
    END
  END i[335]
  PIN i[336]
    DIRECTION INPUT ;
    USE SIGNAL ;
    PORT
      LAYER M5 ;
        RECT  27.84 25.728 27.864 25.92 ;
    END
  END i[336]
  PIN i[337]
    DIRECTION INPUT ;
    USE SIGNAL ;
    PORT
      LAYER M3 ;
        RECT  27.936 25.882 27.954 25.92 ;
    END
  END i[337]
  PIN i[338]
    DIRECTION INPUT ;
    USE SIGNAL ;
    PORT
      LAYER M5 ;
        RECT  27.936 25.728 27.96 25.92 ;
    END
  END i[338]
  PIN i[339]
    DIRECTION INPUT ;
    USE SIGNAL ;
    PORT
      LAYER M3 ;
        RECT  28.008 25.882 28.026 25.92 ;
    END
  END i[339]
  PIN i[33]
    DIRECTION INPUT ;
    USE SIGNAL ;
    PORT
      LAYER M3 ;
        RECT  5.04 25.882 5.058 25.92 ;
    END
  END i[33]
  PIN i[340]
    DIRECTION INPUT ;
    USE SIGNAL ;
    PORT
      LAYER M5 ;
        RECT  28.032 25.728 28.056 25.92 ;
    END
  END i[340]
  PIN i[341]
    DIRECTION INPUT ;
    USE SIGNAL ;
    PORT
      LAYER M3 ;
        RECT  28.08 25.882 28.098 25.92 ;
    END
  END i[341]
  PIN i[342]
    DIRECTION INPUT ;
    USE SIGNAL ;
    PORT
      LAYER M5 ;
        RECT  28.128 25.728 28.152 25.92 ;
    END
  END i[342]
  PIN i[343]
    DIRECTION INPUT ;
    USE SIGNAL ;
    PORT
      LAYER M3 ;
        RECT  28.224 25.882 28.242 25.92 ;
    END
  END i[343]
  PIN i[344]
    DIRECTION INPUT ;
    USE SIGNAL ;
    PORT
      LAYER M5 ;
        RECT  28.32 25.728 28.344 25.92 ;
    END
  END i[344]
  PIN i[345]
    DIRECTION INPUT ;
    USE SIGNAL ;
    PORT
      LAYER M3 ;
        RECT  28.368 25.882 28.386 25.92 ;
    END
  END i[345]
  PIN i[346]
    DIRECTION INPUT ;
    USE SIGNAL ;
    PORT
      LAYER M5 ;
        RECT  28.416 25.728 28.44 25.92 ;
    END
  END i[346]
  PIN i[347]
    DIRECTION INPUT ;
    USE SIGNAL ;
    PORT
      LAYER M3 ;
        RECT  28.584 25.882 28.602 25.92 ;
    END
  END i[347]
  PIN i[348]
    DIRECTION INPUT ;
    USE SIGNAL ;
    PORT
      LAYER M5 ;
        RECT  28.608 25.728 28.632 25.92 ;
    END
  END i[348]
  PIN i[349]
    DIRECTION INPUT ;
    USE SIGNAL ;
    PORT
      LAYER M3 ;
        RECT  28.728 25.882 28.746 25.92 ;
    END
  END i[349]
  PIN i[34]
    DIRECTION INPUT ;
    USE SIGNAL ;
    PORT
      LAYER M5 ;
        RECT  5.136 25.728 5.16 25.92 ;
    END
  END i[34]
  PIN i[350]
    DIRECTION INPUT ;
    USE SIGNAL ;
    PORT
      LAYER M5 ;
        RECT  28.8 25.728 28.824 25.92 ;
    END
  END i[350]
  PIN i[351]
    DIRECTION INPUT ;
    USE SIGNAL ;
    PORT
      LAYER M3 ;
        RECT  28.872 25.882 28.89 25.92 ;
    END
  END i[351]
  PIN i[352]
    DIRECTION INPUT ;
    USE SIGNAL ;
    PORT
      LAYER M5 ;
        RECT  28.992 25.728 29.016 25.92 ;
    END
  END i[352]
  PIN i[353]
    DIRECTION INPUT ;
    USE SIGNAL ;
    PORT
      LAYER M3 ;
        RECT  29.088 25.882 29.106 25.92 ;
    END
  END i[353]
  PIN i[354]
    DIRECTION INPUT ;
    USE SIGNAL ;
    PORT
      LAYER M5 ;
        RECT  29.184 25.728 29.208 25.92 ;
    END
  END i[354]
  PIN i[355]
    DIRECTION INPUT ;
    USE SIGNAL ;
    PORT
      LAYER M3 ;
        RECT  29.232 25.882 29.25 25.92 ;
    END
  END i[355]
  PIN i[356]
    DIRECTION INPUT ;
    USE SIGNAL ;
    PORT
      LAYER M5 ;
        RECT  29.376 25.728 29.4 25.92 ;
    END
  END i[356]
  PIN i[357]
    DIRECTION INPUT ;
    USE SIGNAL ;
    PORT
      LAYER M3 ;
        RECT  29.448 25.882 29.466 25.92 ;
    END
  END i[357]
  PIN i[358]
    DIRECTION INPUT ;
    USE SIGNAL ;
    PORT
      LAYER M5 ;
        RECT  29.472 25.728 29.496 25.92 ;
    END
  END i[358]
  PIN i[359]
    DIRECTION INPUT ;
    USE SIGNAL ;
    PORT
      LAYER M3 ;
        RECT  29.592 25.882 29.61 25.92 ;
    END
  END i[359]
  PIN i[35]
    DIRECTION INPUT ;
    USE SIGNAL ;
    PORT
      LAYER M3 ;
        RECT  5.256 25.882 5.274 25.92 ;
    END
  END i[35]
  PIN i[360]
    DIRECTION INPUT ;
    USE SIGNAL ;
    PORT
      LAYER M5 ;
        RECT  29.664 25.728 29.688 25.92 ;
    END
  END i[360]
  PIN i[361]
    DIRECTION INPUT ;
    USE SIGNAL ;
    PORT
      LAYER M3 ;
        RECT  29.736 25.882 29.754 25.92 ;
    END
  END i[361]
  PIN i[362]
    DIRECTION INPUT ;
    USE SIGNAL ;
    PORT
      LAYER M5 ;
        RECT  29.856 25.728 29.88 25.92 ;
    END
  END i[362]
  PIN i[363]
    DIRECTION INPUT ;
    USE SIGNAL ;
    PORT
      LAYER M3 ;
        RECT  29.952 25.882 29.97 25.92 ;
    END
  END i[363]
  PIN i[364]
    DIRECTION INPUT ;
    USE SIGNAL ;
    PORT
      LAYER M5 ;
        RECT  30.048 25.728 30.072 25.92 ;
    END
  END i[364]
  PIN i[365]
    DIRECTION INPUT ;
    USE SIGNAL ;
    PORT
      LAYER M3 ;
        RECT  30.096 25.882 30.114 25.92 ;
    END
  END i[365]
  PIN i[366]
    DIRECTION INPUT ;
    USE SIGNAL ;
    PORT
      LAYER M5 ;
        RECT  30.24 25.728 30.264 25.92 ;
    END
  END i[366]
  PIN i[367]
    DIRECTION INPUT ;
    USE SIGNAL ;
    PORT
      LAYER M3 ;
        RECT  30.312 25.882 30.33 25.92 ;
    END
  END i[367]
  PIN i[368]
    DIRECTION INPUT ;
    USE SIGNAL ;
    PORT
      LAYER M5 ;
        RECT  30.336 25.728 30.36 25.92 ;
    END
  END i[368]
  PIN i[369]
    DIRECTION INPUT ;
    USE SIGNAL ;
    PORT
      LAYER M3 ;
        RECT  30.456 25.882 30.474 25.92 ;
    END
  END i[369]
  PIN i[36]
    DIRECTION INPUT ;
    USE SIGNAL ;
    PORT
      LAYER M5 ;
        RECT  5.328 25.728 5.352 25.92 ;
    END
  END i[36]
  PIN i[370]
    DIRECTION INPUT ;
    USE SIGNAL ;
    PORT
      LAYER M5 ;
        RECT  30.528 25.728 30.552 25.92 ;
    END
  END i[370]
  PIN i[371]
    DIRECTION INPUT ;
    USE SIGNAL ;
    PORT
      LAYER M3 ;
        RECT  30.672 25.882 30.69 25.92 ;
    END
  END i[371]
  PIN i[372]
    DIRECTION INPUT ;
    USE SIGNAL ;
    PORT
      LAYER M5 ;
        RECT  30.72 25.728 30.744 25.92 ;
    END
  END i[372]
  PIN i[373]
    DIRECTION INPUT ;
    USE SIGNAL ;
    PORT
      LAYER M3 ;
        RECT  30.816 25.882 30.834 25.92 ;
    END
  END i[373]
  PIN i[374]
    DIRECTION INPUT ;
    USE SIGNAL ;
    PORT
      LAYER M5 ;
        RECT  30.912 25.728 30.936 25.92 ;
    END
  END i[374]
  PIN i[375]
    DIRECTION INPUT ;
    USE SIGNAL ;
    PORT
      LAYER M3 ;
        RECT  30.96 25.882 30.978 25.92 ;
    END
  END i[375]
  PIN i[376]
    DIRECTION INPUT ;
    USE SIGNAL ;
    PORT
      LAYER M5 ;
        RECT  31.104 25.728 31.128 25.92 ;
    END
  END i[376]
  PIN i[377]
    DIRECTION INPUT ;
    USE SIGNAL ;
    PORT
      LAYER M3 ;
        RECT  31.176 25.882 31.194 25.92 ;
    END
  END i[377]
  PIN i[378]
    DIRECTION INPUT ;
    USE SIGNAL ;
    PORT
      LAYER M5 ;
        RECT  31.2 25.728 31.224 25.92 ;
    END
  END i[378]
  PIN i[379]
    DIRECTION INPUT ;
    USE SIGNAL ;
    PORT
      LAYER M3 ;
        RECT  31.32 25.882 31.338 25.92 ;
    END
  END i[379]
  PIN i[37]
    DIRECTION INPUT ;
    USE SIGNAL ;
    PORT
      LAYER M3 ;
        RECT  5.4 25.882 5.418 25.92 ;
    END
  END i[37]
  PIN i[380]
    DIRECTION INPUT ;
    USE SIGNAL ;
    PORT
      LAYER M5 ;
        RECT  31.392 25.728 31.416 25.92 ;
    END
  END i[380]
  PIN i[381]
    DIRECTION INPUT ;
    USE SIGNAL ;
    PORT
      LAYER M3 ;
        RECT  31.536 25.882 31.554 25.92 ;
    END
  END i[381]
  PIN i[382]
    DIRECTION INPUT ;
    USE SIGNAL ;
    PORT
      LAYER M5 ;
        RECT  31.584 25.728 31.608 25.92 ;
    END
  END i[382]
  PIN i[383]
    DIRECTION INPUT ;
    USE SIGNAL ;
    PORT
      LAYER M3 ;
        RECT  31.68 25.882 31.698 25.92 ;
    END
  END i[383]
  PIN i[384]
    DIRECTION INPUT ;
    USE SIGNAL ;
    PORT
      LAYER M5 ;
        RECT  31.776 25.728 31.8 25.92 ;
    END
  END i[384]
  PIN i[385]
    DIRECTION INPUT ;
    USE SIGNAL ;
    PORT
      LAYER M3 ;
        RECT  31.824 25.882 31.842 25.92 ;
    END
  END i[385]
  PIN i[386]
    DIRECTION INPUT ;
    USE SIGNAL ;
    PORT
      LAYER M5 ;
        RECT  31.968 25.728 31.992 25.92 ;
    END
  END i[386]
  PIN i[387]
    DIRECTION INPUT ;
    USE SIGNAL ;
    PORT
      LAYER M3 ;
        RECT  32.04 25.882 32.058 25.92 ;
    END
  END i[387]
  PIN i[388]
    DIRECTION INPUT ;
    USE SIGNAL ;
    PORT
      LAYER M5 ;
        RECT  32.16 25.728 32.184 25.92 ;
    END
  END i[388]
  PIN i[389]
    DIRECTION INPUT ;
    USE SIGNAL ;
    PORT
      LAYER M3 ;
        RECT  32.184 25.882 32.202 25.92 ;
    END
  END i[389]
  PIN i[38]
    DIRECTION INPUT ;
    USE SIGNAL ;
    PORT
      LAYER M5 ;
        RECT  5.52 25.728 5.544 25.92 ;
    END
  END i[38]
  PIN i[390]
    DIRECTION INPUT ;
    USE SIGNAL ;
    PORT
      LAYER M5 ;
        RECT  32.256 25.728 32.28 25.92 ;
    END
  END i[390]
  PIN i[391]
    DIRECTION INPUT ;
    USE SIGNAL ;
    PORT
      LAYER M3 ;
        RECT  32.4 25.882 32.418 25.92 ;
    END
  END i[391]
  PIN i[392]
    DIRECTION INPUT ;
    USE SIGNAL ;
    PORT
      LAYER M5 ;
        RECT  32.448 25.728 32.472 25.92 ;
    END
  END i[392]
  PIN i[393]
    DIRECTION INPUT ;
    USE SIGNAL ;
    PORT
      LAYER M3 ;
        RECT  32.544 25.882 32.562 25.92 ;
    END
  END i[393]
  PIN i[394]
    DIRECTION INPUT ;
    USE SIGNAL ;
    PORT
      LAYER M5 ;
        RECT  32.544 25.728 32.568 25.92 ;
    END
  END i[394]
  PIN i[395]
    DIRECTION INPUT ;
    USE SIGNAL ;
    PORT
      LAYER M3 ;
        RECT  33.192 25.882 33.21 25.92 ;
    END
  END i[395]
  PIN i[396]
    DIRECTION INPUT ;
    USE SIGNAL ;
    PORT
      LAYER M5 ;
        RECT  33.216 25.728 33.24 25.92 ;
    END
  END i[396]
  PIN i[397]
    DIRECTION INPUT ;
    USE SIGNAL ;
    PORT
      LAYER M3 ;
        RECT  33.264 25.882 33.282 25.92 ;
    END
  END i[397]
  PIN i[398]
    DIRECTION INPUT ;
    USE SIGNAL ;
    PORT
      LAYER M5 ;
        RECT  33.312 25.728 33.336 25.92 ;
    END
  END i[398]
  PIN i[399]
    DIRECTION INPUT ;
    USE SIGNAL ;
    PORT
      LAYER M3 ;
        RECT  33.336 25.882 33.354 25.92 ;
    END
  END i[399]
  PIN i[39]
    DIRECTION INPUT ;
    USE SIGNAL ;
    PORT
      LAYER M3 ;
        RECT  5.544 25.882 5.562 25.92 ;
    END
  END i[39]
  PIN i[3]
    DIRECTION INPUT ;
    USE SIGNAL ;
    PORT
      LAYER M3 ;
        RECT  2.448 25.882 2.466 25.92 ;
    END
  END i[3]
  PIN i[400]
    DIRECTION INPUT ;
    USE SIGNAL ;
    PORT
      LAYER M5 ;
        RECT  33.408 25.728 33.432 25.92 ;
    END
  END i[400]
  PIN i[401]
    DIRECTION INPUT ;
    USE SIGNAL ;
    PORT
      LAYER M3 ;
        RECT  33.408 25.882 33.426 25.92 ;
    END
  END i[401]
  PIN i[402]
    DIRECTION INPUT ;
    USE SIGNAL ;
    PORT
      LAYER M5 ;
        RECT  33.504 25.728 33.528 25.92 ;
    END
  END i[402]
  PIN i[403]
    DIRECTION INPUT ;
    USE SIGNAL ;
    PORT
      LAYER M3 ;
        RECT  33.48 25.882 33.498 25.92 ;
    END
  END i[403]
  PIN i[404]
    DIRECTION INPUT ;
    USE SIGNAL ;
    PORT
      LAYER M5 ;
        RECT  33.6 25.728 33.624 25.92 ;
    END
  END i[404]
  PIN i[405]
    DIRECTION INPUT ;
    USE SIGNAL ;
    PORT
      LAYER M3 ;
        RECT  33.624 25.882 33.642 25.92 ;
    END
  END i[405]
  PIN i[406]
    DIRECTION INPUT ;
    USE SIGNAL ;
    PORT
      LAYER M5 ;
        RECT  33.696 25.728 33.72 25.92 ;
    END
  END i[406]
  PIN i[407]
    DIRECTION INPUT ;
    USE SIGNAL ;
    PORT
      LAYER M3 ;
        RECT  33.768 25.882 33.786 25.92 ;
    END
  END i[407]
  PIN i[408]
    DIRECTION INPUT ;
    USE SIGNAL ;
    PORT
      LAYER M5 ;
        RECT  33.888 25.728 33.912 25.92 ;
    END
  END i[408]
  PIN i[409]
    DIRECTION INPUT ;
    USE SIGNAL ;
    PORT
      LAYER M3 ;
        RECT  33.912 25.882 33.93 25.92 ;
    END
  END i[409]
  PIN i[40]
    DIRECTION INPUT ;
    USE SIGNAL ;
    PORT
      LAYER M5 ;
        RECT  6.144 25.728 6.168 25.92 ;
    END
  END i[40]
  PIN i[410]
    DIRECTION INPUT ;
    USE SIGNAL ;
    PORT
      LAYER M5 ;
        RECT  33.984 25.728 34.008 25.92 ;
    END
  END i[410]
  PIN i[411]
    DIRECTION INPUT ;
    USE SIGNAL ;
    PORT
      LAYER M3 ;
        RECT  34.128 25.882 34.146 25.92 ;
    END
  END i[411]
  PIN i[412]
    DIRECTION INPUT ;
    USE SIGNAL ;
    PORT
      LAYER M5 ;
        RECT  34.176 25.728 34.2 25.92 ;
    END
  END i[412]
  PIN i[413]
    DIRECTION INPUT ;
    USE SIGNAL ;
    PORT
      LAYER M3 ;
        RECT  34.272 25.882 34.29 25.92 ;
    END
  END i[413]
  PIN i[414]
    DIRECTION INPUT ;
    USE SIGNAL ;
    PORT
      LAYER M5 ;
        RECT  34.368 25.728 34.392 25.92 ;
    END
  END i[414]
  PIN i[415]
    DIRECTION INPUT ;
    USE SIGNAL ;
    PORT
      LAYER M3 ;
        RECT  34.488 25.882 34.506 25.92 ;
    END
  END i[415]
  PIN i[416]
    DIRECTION INPUT ;
    USE SIGNAL ;
    PORT
      LAYER M5 ;
        RECT  34.56 25.728 34.584 25.92 ;
    END
  END i[416]
  PIN i[417]
    DIRECTION INPUT ;
    USE SIGNAL ;
    PORT
      LAYER M3 ;
        RECT  34.632 25.882 34.65 25.92 ;
    END
  END i[417]
  PIN i[418]
    DIRECTION INPUT ;
    USE SIGNAL ;
    PORT
      LAYER M5 ;
        RECT  34.752 25.728 34.776 25.92 ;
    END
  END i[418]
  PIN i[419]
    DIRECTION INPUT ;
    USE SIGNAL ;
    PORT
      LAYER M3 ;
        RECT  34.776 25.882 34.794 25.92 ;
    END
  END i[419]
  PIN i[41]
    DIRECTION INPUT ;
    USE SIGNAL ;
    PORT
      LAYER M3 ;
        RECT  6.192 25.882 6.21 25.92 ;
    END
  END i[41]
  PIN i[420]
    DIRECTION INPUT ;
    USE SIGNAL ;
    PORT
      LAYER M5 ;
        RECT  34.848 25.728 34.872 25.92 ;
    END
  END i[420]
  PIN i[421]
    DIRECTION INPUT ;
    USE SIGNAL ;
    PORT
      LAYER M3 ;
        RECT  34.992 25.882 35.01 25.92 ;
    END
  END i[421]
  PIN i[422]
    DIRECTION INPUT ;
    USE SIGNAL ;
    PORT
      LAYER M5 ;
        RECT  35.04 25.728 35.064 25.92 ;
    END
  END i[422]
  PIN i[423]
    DIRECTION INPUT ;
    USE SIGNAL ;
    PORT
      LAYER M3 ;
        RECT  35.136 25.882 35.154 25.92 ;
    END
  END i[423]
  PIN i[424]
    DIRECTION INPUT ;
    USE SIGNAL ;
    PORT
      LAYER M5 ;
        RECT  35.232 25.728 35.256 25.92 ;
    END
  END i[424]
  PIN i[425]
    DIRECTION INPUT ;
    USE SIGNAL ;
    PORT
      LAYER M3 ;
        RECT  35.352 25.882 35.37 25.92 ;
    END
  END i[425]
  PIN i[426]
    DIRECTION INPUT ;
    USE SIGNAL ;
    PORT
      LAYER M5 ;
        RECT  35.424 25.728 35.448 25.92 ;
    END
  END i[426]
  PIN i[427]
    DIRECTION INPUT ;
    USE SIGNAL ;
    PORT
      LAYER M3 ;
        RECT  35.496 25.882 35.514 25.92 ;
    END
  END i[427]
  PIN i[428]
    DIRECTION INPUT ;
    USE SIGNAL ;
    PORT
      LAYER M3 ;
        RECT  39.672 25.882 39.69 25.92 ;
    END
  END i[428]
  PIN i[429]
    DIRECTION INPUT ;
    USE SIGNAL ;
    PORT
      LAYER M5 ;
        RECT  39.792 25.728 39.816 25.92 ;
    END
  END i[429]
  PIN i[42]
    DIRECTION INPUT ;
    USE SIGNAL ;
    PORT
      LAYER M5 ;
        RECT  6.24 25.728 6.264 25.92 ;
    END
  END i[42]
  PIN i[430]
    DIRECTION INPUT ;
    USE SIGNAL ;
    PORT
      LAYER M3 ;
        RECT  39.888 25.882 39.906 25.92 ;
    END
  END i[430]
  PIN i[431]
    DIRECTION INPUT ;
    USE SIGNAL ;
    PORT
      LAYER M5 ;
        RECT  39.984 25.728 40.008 25.92 ;
    END
  END i[431]
  PIN i[432]
    DIRECTION INPUT ;
    USE SIGNAL ;
    PORT
      LAYER M3 ;
        RECT  40.032 25.882 40.05 25.92 ;
    END
  END i[432]
  PIN i[433]
    DIRECTION INPUT ;
    USE SIGNAL ;
    PORT
      LAYER M5 ;
        RECT  40.08 25.728 40.104 25.92 ;
    END
  END i[433]
  PIN i[434]
    DIRECTION INPUT ;
    USE SIGNAL ;
    PORT
      LAYER M3 ;
        RECT  40.176 25.882 40.194 25.92 ;
    END
  END i[434]
  PIN i[435]
    DIRECTION INPUT ;
    USE SIGNAL ;
    PORT
      LAYER M5 ;
        RECT  40.272 25.728 40.296 25.92 ;
    END
  END i[435]
  PIN i[436]
    DIRECTION INPUT ;
    USE SIGNAL ;
    PORT
      LAYER M3 ;
        RECT  40.392 25.882 40.41 25.92 ;
    END
  END i[436]
  PIN i[437]
    DIRECTION INPUT ;
    USE SIGNAL ;
    PORT
      LAYER M5 ;
        RECT  40.464 25.728 40.488 25.92 ;
    END
  END i[437]
  PIN i[438]
    DIRECTION INPUT ;
    USE SIGNAL ;
    PORT
      LAYER M3 ;
        RECT  40.536 25.882 40.554 25.92 ;
    END
  END i[438]
  PIN i[439]
    DIRECTION INPUT ;
    USE SIGNAL ;
    PORT
      LAYER M5 ;
        RECT  40.656 25.728 40.68 25.92 ;
    END
  END i[439]
  PIN i[43]
    DIRECTION INPUT ;
    USE SIGNAL ;
    PORT
      LAYER M3 ;
        RECT  6.264 25.882 6.282 25.92 ;
    END
  END i[43]
  PIN i[440]
    DIRECTION INPUT ;
    USE SIGNAL ;
    PORT
      LAYER M3 ;
        RECT  40.752 25.882 40.77 25.92 ;
    END
  END i[440]
  PIN i[441]
    DIRECTION INPUT ;
    USE SIGNAL ;
    PORT
      LAYER M5 ;
        RECT  40.848 25.728 40.872 25.92 ;
    END
  END i[441]
  PIN i[442]
    DIRECTION INPUT ;
    USE SIGNAL ;
    PORT
      LAYER M3 ;
        RECT  40.896 25.882 40.914 25.92 ;
    END
  END i[442]
  PIN i[44]
    DIRECTION INPUT ;
    USE SIGNAL ;
    PORT
      LAYER M5 ;
        RECT  6.336 25.728 6.36 25.92 ;
    END
  END i[44]
  PIN i[45]
    DIRECTION INPUT ;
    USE SIGNAL ;
    PORT
      LAYER M3 ;
        RECT  6.336 25.882 6.354 25.92 ;
    END
  END i[45]
  PIN i[46]
    DIRECTION INPUT ;
    USE SIGNAL ;
    PORT
      LAYER M5 ;
        RECT  6.432 25.728 6.456 25.92 ;
    END
  END i[46]
  PIN i[47]
    DIRECTION INPUT ;
    USE SIGNAL ;
    PORT
      LAYER M3 ;
        RECT  6.408 25.882 6.426 25.92 ;
    END
  END i[47]
  PIN i[48]
    DIRECTION INPUT ;
    USE SIGNAL ;
    PORT
      LAYER M5 ;
        RECT  6.528 25.728 6.552 25.92 ;
    END
  END i[48]
  PIN i[49]
    DIRECTION INPUT ;
    USE SIGNAL ;
    PORT
      LAYER M3 ;
        RECT  6.48 25.882 6.498 25.92 ;
    END
  END i[49]
  PIN i[4]
    DIRECTION INPUT ;
    USE SIGNAL ;
    PORT
      LAYER M5 ;
        RECT  2.544 25.728 2.568 25.92 ;
    END
  END i[4]
  PIN i[50]
    DIRECTION INPUT ;
    USE SIGNAL ;
    PORT
      LAYER M5 ;
        RECT  6.624 25.728 6.648 25.92 ;
    END
  END i[50]
  PIN i[51]
    DIRECTION INPUT ;
    USE SIGNAL ;
    PORT
      LAYER M3 ;
        RECT  6.624 25.882 6.642 25.92 ;
    END
  END i[51]
  PIN i[52]
    DIRECTION INPUT ;
    USE SIGNAL ;
    PORT
      LAYER M5 ;
        RECT  6.72 25.728 6.744 25.92 ;
    END
  END i[52]
  PIN i[53]
    DIRECTION INPUT ;
    USE SIGNAL ;
    PORT
      LAYER M3 ;
        RECT  6.84 25.882 6.858 25.92 ;
    END
  END i[53]
  PIN i[54]
    DIRECTION INPUT ;
    USE SIGNAL ;
    PORT
      LAYER M5 ;
        RECT  6.912 25.728 6.936 25.92 ;
    END
  END i[54]
  PIN i[55]
    DIRECTION INPUT ;
    USE SIGNAL ;
    PORT
      LAYER M3 ;
        RECT  6.984 25.882 7.002 25.92 ;
    END
  END i[55]
  PIN i[56]
    DIRECTION INPUT ;
    USE SIGNAL ;
    PORT
      LAYER M5 ;
        RECT  7.104 25.728 7.128 25.92 ;
    END
  END i[56]
  PIN i[57]
    DIRECTION INPUT ;
    USE SIGNAL ;
    PORT
      LAYER M3 ;
        RECT  7.128 25.882 7.146 25.92 ;
    END
  END i[57]
  PIN i[58]
    DIRECTION INPUT ;
    USE SIGNAL ;
    PORT
      LAYER M5 ;
        RECT  7.2 25.728 7.224 25.92 ;
    END
  END i[58]
  PIN i[59]
    DIRECTION INPUT ;
    USE SIGNAL ;
    PORT
      LAYER M3 ;
        RECT  7.344 25.882 7.362 25.92 ;
    END
  END i[59]
  PIN i[5]
    DIRECTION INPUT ;
    USE SIGNAL ;
    PORT
      LAYER M3 ;
        RECT  2.664 25.882 2.682 25.92 ;
    END
  END i[5]
  PIN i[60]
    DIRECTION INPUT ;
    USE SIGNAL ;
    PORT
      LAYER M5 ;
        RECT  7.392 25.728 7.416 25.92 ;
    END
  END i[60]
  PIN i[61]
    DIRECTION INPUT ;
    USE SIGNAL ;
    PORT
      LAYER M3 ;
        RECT  7.488 25.882 7.506 25.92 ;
    END
  END i[61]
  PIN i[62]
    DIRECTION INPUT ;
    USE SIGNAL ;
    PORT
      LAYER M5 ;
        RECT  7.584 25.728 7.608 25.92 ;
    END
  END i[62]
  PIN i[63]
    DIRECTION INPUT ;
    USE SIGNAL ;
    PORT
      LAYER M3 ;
        RECT  7.704 25.882 7.722 25.92 ;
    END
  END i[63]
  PIN i[64]
    DIRECTION INPUT ;
    USE SIGNAL ;
    PORT
      LAYER M5 ;
        RECT  7.776 25.728 7.8 25.92 ;
    END
  END i[64]
  PIN i[65]
    DIRECTION INPUT ;
    USE SIGNAL ;
    PORT
      LAYER M3 ;
        RECT  7.848 25.882 7.866 25.92 ;
    END
  END i[65]
  PIN i[66]
    DIRECTION INPUT ;
    USE SIGNAL ;
    PORT
      LAYER M5 ;
        RECT  7.968 25.728 7.992 25.92 ;
    END
  END i[66]
  PIN i[67]
    DIRECTION INPUT ;
    USE SIGNAL ;
    PORT
      LAYER M3 ;
        RECT  7.992 25.882 8.01 25.92 ;
    END
  END i[67]
  PIN i[68]
    DIRECTION INPUT ;
    USE SIGNAL ;
    PORT
      LAYER M5 ;
        RECT  8.064 25.728 8.088 25.92 ;
    END
  END i[68]
  PIN i[69]
    DIRECTION INPUT ;
    USE SIGNAL ;
    PORT
      LAYER M3 ;
        RECT  8.208 25.882 8.226 25.92 ;
    END
  END i[69]
  PIN i[6]
    DIRECTION INPUT ;
    USE SIGNAL ;
    PORT
      LAYER M5 ;
        RECT  2.736 25.728 2.76 25.92 ;
    END
  END i[6]
  PIN i[70]
    DIRECTION INPUT ;
    USE SIGNAL ;
    PORT
      LAYER M5 ;
        RECT  8.256 25.728 8.28 25.92 ;
    END
  END i[70]
  PIN i[71]
    DIRECTION INPUT ;
    USE SIGNAL ;
    PORT
      LAYER M3 ;
        RECT  8.352 25.882 8.37 25.92 ;
    END
  END i[71]
  PIN i[72]
    DIRECTION INPUT ;
    USE SIGNAL ;
    PORT
      LAYER M5 ;
        RECT  8.448 25.728 8.472 25.92 ;
    END
  END i[72]
  PIN i[73]
    DIRECTION INPUT ;
    USE SIGNAL ;
    PORT
      LAYER M3 ;
        RECT  8.568 25.882 8.586 25.92 ;
    END
  END i[73]
  PIN i[74]
    DIRECTION INPUT ;
    USE SIGNAL ;
    PORT
      LAYER M5 ;
        RECT  8.64 25.728 8.664 25.92 ;
    END
  END i[74]
  PIN i[75]
    DIRECTION INPUT ;
    USE SIGNAL ;
    PORT
      LAYER M3 ;
        RECT  8.712 25.882 8.73 25.92 ;
    END
  END i[75]
  PIN i[76]
    DIRECTION INPUT ;
    USE SIGNAL ;
    PORT
      LAYER M5 ;
        RECT  8.832 25.728 8.856 25.92 ;
    END
  END i[76]
  PIN i[77]
    DIRECTION INPUT ;
    USE SIGNAL ;
    PORT
      LAYER M3 ;
        RECT  8.856 25.882 8.874 25.92 ;
    END
  END i[77]
  PIN i[78]
    DIRECTION INPUT ;
    USE SIGNAL ;
    PORT
      LAYER M5 ;
        RECT  8.928 25.728 8.952 25.92 ;
    END
  END i[78]
  PIN i[79]
    DIRECTION INPUT ;
    USE SIGNAL ;
    PORT
      LAYER M3 ;
        RECT  9.072 25.882 9.09 25.92 ;
    END
  END i[79]
  PIN i[7]
    DIRECTION INPUT ;
    USE SIGNAL ;
    PORT
      LAYER M3 ;
        RECT  2.808 25.882 2.826 25.92 ;
    END
  END i[7]
  PIN i[80]
    DIRECTION INPUT ;
    USE SIGNAL ;
    PORT
      LAYER M5 ;
        RECT  9.12 25.728 9.144 25.92 ;
    END
  END i[80]
  PIN i[81]
    DIRECTION INPUT ;
    USE SIGNAL ;
    PORT
      LAYER M3 ;
        RECT  9.216 25.882 9.234 25.92 ;
    END
  END i[81]
  PIN i[82]
    DIRECTION INPUT ;
    USE SIGNAL ;
    PORT
      LAYER M5 ;
        RECT  9.312 25.728 9.336 25.92 ;
    END
  END i[82]
  PIN i[83]
    DIRECTION INPUT ;
    USE SIGNAL ;
    PORT
      LAYER M3 ;
        RECT  9.432 25.882 9.45 25.92 ;
    END
  END i[83]
  PIN i[84]
    DIRECTION INPUT ;
    USE SIGNAL ;
    PORT
      LAYER M5 ;
        RECT  9.504 25.728 9.528 25.92 ;
    END
  END i[84]
  PIN i[85]
    DIRECTION INPUT ;
    USE SIGNAL ;
    PORT
      LAYER M3 ;
        RECT  9.576 25.882 9.594 25.92 ;
    END
  END i[85]
  PIN i[86]
    DIRECTION INPUT ;
    USE SIGNAL ;
    PORT
      LAYER M5 ;
        RECT  9.696 25.728 9.72 25.92 ;
    END
  END i[86]
  PIN i[87]
    DIRECTION INPUT ;
    USE SIGNAL ;
    PORT
      LAYER M3 ;
        RECT  9.792 25.882 9.81 25.92 ;
    END
  END i[87]
  PIN i[88]
    DIRECTION INPUT ;
    USE SIGNAL ;
    PORT
      LAYER M5 ;
        RECT  9.888 25.728 9.912 25.92 ;
    END
  END i[88]
  PIN i[89]
    DIRECTION INPUT ;
    USE SIGNAL ;
    PORT
      LAYER M3 ;
        RECT  9.936 25.882 9.954 25.92 ;
    END
  END i[89]
  PIN i[8]
    DIRECTION INPUT ;
    USE SIGNAL ;
    PORT
      LAYER M5 ;
        RECT  2.928 25.728 2.952 25.92 ;
    END
  END i[8]
  PIN i[90]
    DIRECTION INPUT ;
    USE SIGNAL ;
    PORT
      LAYER M5 ;
        RECT  9.984 25.728 10.008 25.92 ;
    END
  END i[90]
  PIN i[91]
    DIRECTION INPUT ;
    USE SIGNAL ;
    PORT
      LAYER M3 ;
        RECT  10.08 25.882 10.098 25.92 ;
    END
  END i[91]
  PIN i[92]
    DIRECTION INPUT ;
    USE SIGNAL ;
    PORT
      LAYER M5 ;
        RECT  10.176 25.728 10.2 25.92 ;
    END
  END i[92]
  PIN i[93]
    DIRECTION INPUT ;
    USE SIGNAL ;
    PORT
      LAYER M3 ;
        RECT  10.296 25.882 10.314 25.92 ;
    END
  END i[93]
  PIN i[94]
    DIRECTION INPUT ;
    USE SIGNAL ;
    PORT
      LAYER M5 ;
        RECT  10.368 25.728 10.392 25.92 ;
    END
  END i[94]
  PIN i[95]
    DIRECTION INPUT ;
    USE SIGNAL ;
    PORT
      LAYER M3 ;
        RECT  10.44 25.882 10.458 25.92 ;
    END
  END i[95]
  PIN i[96]
    DIRECTION INPUT ;
    USE SIGNAL ;
    PORT
      LAYER M5 ;
        RECT  10.56 25.728 10.584 25.92 ;
    END
  END i[96]
  PIN i[97]
    DIRECTION INPUT ;
    USE SIGNAL ;
    PORT
      LAYER M3 ;
        RECT  10.656 25.882 10.674 25.92 ;
    END
  END i[97]
  PIN i[98]
    DIRECTION INPUT ;
    USE SIGNAL ;
    PORT
      LAYER M5 ;
        RECT  10.752 25.728 10.776 25.92 ;
    END
  END i[98]
  PIN i[99]
    DIRECTION INPUT ;
    USE SIGNAL ;
    PORT
      LAYER M3 ;
        RECT  10.8 25.882 10.818 25.92 ;
    END
  END i[99]
  PIN i[9]
    DIRECTION INPUT ;
    USE SIGNAL ;
    PORT
      LAYER M3 ;
        RECT  2.952 25.882 2.97 25.92 ;
    END
  END i[9]
  PIN i_v[0]
    DIRECTION INPUT ;
    USE SIGNAL ;
    PORT
      LAYER M3 ;
        RECT  36.864 25.882 36.882 25.92 ;
    END
  END i_v[0]
  PIN i_v[1]
    DIRECTION INPUT ;
    USE SIGNAL ;
    PORT
      LAYER M5 ;
        RECT  38.544 25.728 38.568 25.92 ;
    END
  END i_v[1]
  PIN i_v[2]
    DIRECTION INPUT ;
    USE SIGNAL ;
    PORT
      LAYER M5 ;
        RECT  39.6 25.728 39.624 25.92 ;
    END
  END i_v[2]
  PIN i_v[3]
    DIRECTION INPUT ;
    USE SIGNAL ;
    PORT
      LAYER M5 ;
        RECT  40.944 25.728 40.968 25.92 ;
    END
  END i_v[3]
  PIN o[0]
    DIRECTION OUTPUT ;
    USE SIGNAL ;
    PORT
      LAYER M5 ;
        RECT  2.16 0 2.184 0.192 ;
    END
  END o[0]
  PIN o[100]
    DIRECTION OUTPUT ;
    USE SIGNAL ;
    PORT
      LAYER M5 ;
        RECT  10.848 0 10.872 0.192 ;
    END
  END o[100]
  PIN o[101]
    DIRECTION OUTPUT ;
    USE SIGNAL ;
    PORT
      LAYER M3 ;
        RECT  10.944 0 10.962 0.038 ;
    END
  END o[101]
  PIN o[102]
    DIRECTION OUTPUT ;
    USE SIGNAL ;
    PORT
      LAYER M5 ;
        RECT  10.944 0 10.968 0.192 ;
    END
  END o[102]
  PIN o[103]
    DIRECTION OUTPUT ;
    USE SIGNAL ;
    PORT
      LAYER M3 ;
        RECT  11.592 0 11.61 0.038 ;
    END
  END o[103]
  PIN o[104]
    DIRECTION OUTPUT ;
    USE SIGNAL ;
    PORT
      LAYER M5 ;
        RECT  11.616 0 11.64 0.192 ;
    END
  END o[104]
  PIN o[105]
    DIRECTION OUTPUT ;
    USE SIGNAL ;
    PORT
      LAYER M3 ;
        RECT  11.664 0 11.682 0.038 ;
    END
  END o[105]
  PIN o[106]
    DIRECTION OUTPUT ;
    USE SIGNAL ;
    PORT
      LAYER M5 ;
        RECT  11.712 0 11.736 0.192 ;
    END
  END o[106]
  PIN o[107]
    DIRECTION OUTPUT ;
    USE SIGNAL ;
    PORT
      LAYER M3 ;
        RECT  11.736 0 11.754 0.038 ;
    END
  END o[107]
  PIN o[108]
    DIRECTION OUTPUT ;
    USE SIGNAL ;
    PORT
      LAYER M5 ;
        RECT  11.808 0 11.832 0.192 ;
    END
  END o[108]
  PIN o[109]
    DIRECTION OUTPUT ;
    USE SIGNAL ;
    PORT
      LAYER M3 ;
        RECT  11.808 0 11.826 0.038 ;
    END
  END o[109]
  PIN o[10]
    DIRECTION OUTPUT ;
    USE SIGNAL ;
    PORT
      LAYER M5 ;
        RECT  3.024 0 3.048 0.192 ;
    END
  END o[10]
  PIN o[110]
    DIRECTION OUTPUT ;
    USE SIGNAL ;
    PORT
      LAYER M5 ;
        RECT  11.904 0 11.928 0.192 ;
    END
  END o[110]
  PIN o[111]
    DIRECTION OUTPUT ;
    USE SIGNAL ;
    PORT
      LAYER M3 ;
        RECT  11.88 0 11.898 0.038 ;
    END
  END o[111]
  PIN o[112]
    DIRECTION OUTPUT ;
    USE SIGNAL ;
    PORT
      LAYER M5 ;
        RECT  12 0 12.024 0.192 ;
    END
  END o[112]
  PIN o[113]
    DIRECTION OUTPUT ;
    USE SIGNAL ;
    PORT
      LAYER M3 ;
        RECT  12.024 0 12.042 0.038 ;
    END
  END o[113]
  PIN o[114]
    DIRECTION OUTPUT ;
    USE SIGNAL ;
    PORT
      LAYER M5 ;
        RECT  12.096 0 12.12 0.192 ;
    END
  END o[114]
  PIN o[115]
    DIRECTION OUTPUT ;
    USE SIGNAL ;
    PORT
      LAYER M3 ;
        RECT  12.168 0 12.186 0.038 ;
    END
  END o[115]
  PIN o[116]
    DIRECTION OUTPUT ;
    USE SIGNAL ;
    PORT
      LAYER M5 ;
        RECT  12.288 0 12.312 0.192 ;
    END
  END o[116]
  PIN o[117]
    DIRECTION OUTPUT ;
    USE SIGNAL ;
    PORT
      LAYER M3 ;
        RECT  12.384 0 12.402 0.038 ;
    END
  END o[117]
  PIN o[118]
    DIRECTION OUTPUT ;
    USE SIGNAL ;
    PORT
      LAYER M5 ;
        RECT  12.48 0 12.504 0.192 ;
    END
  END o[118]
  PIN o[119]
    DIRECTION OUTPUT ;
    USE SIGNAL ;
    PORT
      LAYER M3 ;
        RECT  12.528 0 12.546 0.038 ;
    END
  END o[119]
  PIN o[11]
    DIRECTION OUTPUT ;
    USE SIGNAL ;
    PORT
      LAYER M3 ;
        RECT  3.168 0 3.186 0.038 ;
    END
  END o[11]
  PIN o[120]
    DIRECTION OUTPUT ;
    USE SIGNAL ;
    PORT
      LAYER M5 ;
        RECT  12.672 0 12.696 0.192 ;
    END
  END o[120]
  PIN o[121]
    DIRECTION OUTPUT ;
    USE SIGNAL ;
    PORT
      LAYER M3 ;
        RECT  12.744 0 12.762 0.038 ;
    END
  END o[121]
  PIN o[122]
    DIRECTION OUTPUT ;
    USE SIGNAL ;
    PORT
      LAYER M5 ;
        RECT  12.768 0 12.792 0.192 ;
    END
  END o[122]
  PIN o[123]
    DIRECTION OUTPUT ;
    USE SIGNAL ;
    PORT
      LAYER M3 ;
        RECT  12.888 0 12.906 0.038 ;
    END
  END o[123]
  PIN o[124]
    DIRECTION OUTPUT ;
    USE SIGNAL ;
    PORT
      LAYER M5 ;
        RECT  12.96 0 12.984 0.192 ;
    END
  END o[124]
  PIN o[125]
    DIRECTION OUTPUT ;
    USE SIGNAL ;
    PORT
      LAYER M3 ;
        RECT  13.032 0 13.05 0.038 ;
    END
  END o[125]
  PIN o[126]
    DIRECTION OUTPUT ;
    USE SIGNAL ;
    PORT
      LAYER M5 ;
        RECT  13.152 0 13.176 0.192 ;
    END
  END o[126]
  PIN o[127]
    DIRECTION OUTPUT ;
    USE SIGNAL ;
    PORT
      LAYER M3 ;
        RECT  13.248 0 13.266 0.038 ;
    END
  END o[127]
  PIN o[128]
    DIRECTION OUTPUT ;
    USE SIGNAL ;
    PORT
      LAYER M5 ;
        RECT  35.616 0 35.64 0.192 ;
    END
  END o[128]
  PIN o[129]
    DIRECTION OUTPUT ;
    USE SIGNAL ;
    PORT
      LAYER M3 ;
        RECT  35.712 0 35.73 0.038 ;
    END
  END o[129]
  PIN o[12]
    DIRECTION OUTPUT ;
    USE SIGNAL ;
    PORT
      LAYER M5 ;
        RECT  3.216 0 3.24 0.192 ;
    END
  END o[12]
  PIN o[130]
    DIRECTION OUTPUT ;
    USE SIGNAL ;
    PORT
      LAYER M5 ;
        RECT  35.808 0 35.832 0.192 ;
    END
  END o[130]
  PIN o[131]
    DIRECTION OUTPUT ;
    USE SIGNAL ;
    PORT
      LAYER M3 ;
        RECT  35.856 0 35.874 0.038 ;
    END
  END o[131]
  PIN o[132]
    DIRECTION OUTPUT ;
    USE SIGNAL ;
    PORT
      LAYER M5 ;
        RECT  35.904 0 35.928 0.192 ;
    END
  END o[132]
  PIN o[133]
    DIRECTION OUTPUT ;
    USE SIGNAL ;
    PORT
      LAYER M3 ;
        RECT  36 0 36.018 0.038 ;
    END
  END o[133]
  PIN o[134]
    DIRECTION OUTPUT ;
    USE SIGNAL ;
    PORT
      LAYER M5 ;
        RECT  36.096 0 36.12 0.192 ;
    END
  END o[134]
  PIN o[135]
    DIRECTION OUTPUT ;
    USE SIGNAL ;
    PORT
      LAYER M3 ;
        RECT  36.216 0 36.234 0.038 ;
    END
  END o[135]
  PIN o[136]
    DIRECTION OUTPUT ;
    USE SIGNAL ;
    PORT
      LAYER M5 ;
        RECT  36.288 0 36.312 0.192 ;
    END
  END o[136]
  PIN o[137]
    DIRECTION OUTPUT ;
    USE SIGNAL ;
    PORT
      LAYER M3 ;
        RECT  36.36 0 36.378 0.038 ;
    END
  END o[137]
  PIN o[138]
    DIRECTION OUTPUT ;
    USE SIGNAL ;
    PORT
      LAYER M5 ;
        RECT  36.48 0 36.504 0.192 ;
    END
  END o[138]
  PIN o[139]
    DIRECTION OUTPUT ;
    USE SIGNAL ;
    PORT
      LAYER M3 ;
        RECT  36.576 0 36.594 0.038 ;
    END
  END o[139]
  PIN o[13]
    DIRECTION OUTPUT ;
    USE SIGNAL ;
    PORT
      LAYER M3 ;
        RECT  3.312 0 3.33 0.038 ;
    END
  END o[13]
  PIN o[140]
    DIRECTION OUTPUT ;
    USE SIGNAL ;
    PORT
      LAYER M5 ;
        RECT  36.672 0 36.696 0.192 ;
    END
  END o[140]
  PIN o[141]
    DIRECTION OUTPUT ;
    USE SIGNAL ;
    PORT
      LAYER M3 ;
        RECT  36.72 0 36.738 0.038 ;
    END
  END o[141]
  PIN o[142]
    DIRECTION OUTPUT ;
    USE SIGNAL ;
    PORT
      LAYER M5 ;
        RECT  36.768 0 36.792 0.192 ;
    END
  END o[142]
  PIN o[143]
    DIRECTION OUTPUT ;
    USE SIGNAL ;
    PORT
      LAYER M5 ;
        RECT  36.96 0 36.984 0.192 ;
    END
  END o[143]
  PIN o[144]
    DIRECTION OUTPUT ;
    USE SIGNAL ;
    PORT
      LAYER M3 ;
        RECT  37.08 0 37.098 0.038 ;
    END
  END o[144]
  PIN o[145]
    DIRECTION OUTPUT ;
    USE SIGNAL ;
    PORT
      LAYER M5 ;
        RECT  37.152 0 37.176 0.192 ;
    END
  END o[145]
  PIN o[146]
    DIRECTION OUTPUT ;
    USE SIGNAL ;
    PORT
      LAYER M3 ;
        RECT  37.224 0 37.242 0.038 ;
    END
  END o[146]
  PIN o[147]
    DIRECTION OUTPUT ;
    USE SIGNAL ;
    PORT
      LAYER M5 ;
        RECT  37.344 0 37.368 0.192 ;
    END
  END o[147]
  PIN o[148]
    DIRECTION OUTPUT ;
    USE SIGNAL ;
    PORT
      LAYER M3 ;
        RECT  37.44 0 37.458 0.038 ;
    END
  END o[148]
  PIN o[149]
    DIRECTION OUTPUT ;
    USE SIGNAL ;
    PORT
      LAYER M5 ;
        RECT  37.536 0 37.56 0.192 ;
    END
  END o[149]
  PIN o[14]
    DIRECTION OUTPUT ;
    USE SIGNAL ;
    PORT
      LAYER M5 ;
        RECT  3.408 0 3.432 0.192 ;
    END
  END o[14]
  PIN o[150]
    DIRECTION OUTPUT ;
    USE SIGNAL ;
    PORT
      LAYER M3 ;
        RECT  37.584 0 37.602 0.038 ;
    END
  END o[150]
  PIN o[151]
    DIRECTION OUTPUT ;
    USE SIGNAL ;
    PORT
      LAYER M5 ;
        RECT  37.632 0 37.656 0.192 ;
    END
  END o[151]
  PIN o[152]
    DIRECTION OUTPUT ;
    USE SIGNAL ;
    PORT
      LAYER M3 ;
        RECT  37.8 0 37.818 0.038 ;
    END
  END o[152]
  PIN o[153]
    DIRECTION OUTPUT ;
    USE SIGNAL ;
    PORT
      LAYER M5 ;
        RECT  37.824 0 37.848 0.192 ;
    END
  END o[153]
  PIN o[154]
    DIRECTION OUTPUT ;
    USE SIGNAL ;
    PORT
      LAYER M3 ;
        RECT  37.944 0 37.962 0.038 ;
    END
  END o[154]
  PIN o[155]
    DIRECTION OUTPUT ;
    USE SIGNAL ;
    PORT
      LAYER M5 ;
        RECT  37.92 0 37.944 0.192 ;
    END
  END o[155]
  PIN o[156]
    DIRECTION OUTPUT ;
    USE SIGNAL ;
    PORT
      LAYER M3 ;
        RECT  38.592 0 38.61 0.038 ;
    END
  END o[156]
  PIN o[157]
    DIRECTION OUTPUT ;
    USE SIGNAL ;
    PORT
      LAYER M5 ;
        RECT  13.344 0 13.368 0.192 ;
    END
  END o[157]
  PIN o[158]
    DIRECTION OUTPUT ;
    USE SIGNAL ;
    PORT
      LAYER M3 ;
        RECT  13.392 0 13.41 0.038 ;
    END
  END o[158]
  PIN o[159]
    DIRECTION OUTPUT ;
    USE SIGNAL ;
    PORT
      LAYER M5 ;
        RECT  13.536 0 13.56 0.192 ;
    END
  END o[159]
  PIN o[15]
    DIRECTION OUTPUT ;
    USE SIGNAL ;
    PORT
      LAYER M3 ;
        RECT  3.528 0 3.546 0.038 ;
    END
  END o[15]
  PIN o[160]
    DIRECTION OUTPUT ;
    USE SIGNAL ;
    PORT
      LAYER M3 ;
        RECT  13.608 0 13.626 0.038 ;
    END
  END o[160]
  PIN o[161]
    DIRECTION OUTPUT ;
    USE SIGNAL ;
    PORT
      LAYER M5 ;
        RECT  13.632 0 13.656 0.192 ;
    END
  END o[161]
  PIN o[162]
    DIRECTION OUTPUT ;
    USE SIGNAL ;
    PORT
      LAYER M3 ;
        RECT  13.752 0 13.77 0.038 ;
    END
  END o[162]
  PIN o[163]
    DIRECTION OUTPUT ;
    USE SIGNAL ;
    PORT
      LAYER M5 ;
        RECT  13.824 0 13.848 0.192 ;
    END
  END o[163]
  PIN o[164]
    DIRECTION OUTPUT ;
    USE SIGNAL ;
    PORT
      LAYER M3 ;
        RECT  13.968 0 13.986 0.038 ;
    END
  END o[164]
  PIN o[165]
    DIRECTION OUTPUT ;
    USE SIGNAL ;
    PORT
      LAYER M5 ;
        RECT  14.016 0 14.04 0.192 ;
    END
  END o[165]
  PIN o[166]
    DIRECTION OUTPUT ;
    USE SIGNAL ;
    PORT
      LAYER M3 ;
        RECT  14.112 0 14.13 0.038 ;
    END
  END o[166]
  PIN o[167]
    DIRECTION OUTPUT ;
    USE SIGNAL ;
    PORT
      LAYER M5 ;
        RECT  14.208 0 14.232 0.192 ;
    END
  END o[167]
  PIN o[168]
    DIRECTION OUTPUT ;
    USE SIGNAL ;
    PORT
      LAYER M3 ;
        RECT  14.256 0 14.274 0.038 ;
    END
  END o[168]
  PIN o[169]
    DIRECTION OUTPUT ;
    USE SIGNAL ;
    PORT
      LAYER M5 ;
        RECT  14.4 0 14.424 0.192 ;
    END
  END o[169]
  PIN o[16]
    DIRECTION OUTPUT ;
    USE SIGNAL ;
    PORT
      LAYER M5 ;
        RECT  3.6 0 3.624 0.192 ;
    END
  END o[16]
  PIN o[170]
    DIRECTION OUTPUT ;
    USE SIGNAL ;
    PORT
      LAYER M3 ;
        RECT  14.472 0 14.49 0.038 ;
    END
  END o[170]
  PIN o[171]
    DIRECTION OUTPUT ;
    USE SIGNAL ;
    PORT
      LAYER M5 ;
        RECT  14.496 0 14.52 0.192 ;
    END
  END o[171]
  PIN o[172]
    DIRECTION OUTPUT ;
    USE SIGNAL ;
    PORT
      LAYER M3 ;
        RECT  14.616 0 14.634 0.038 ;
    END
  END o[172]
  PIN o[173]
    DIRECTION OUTPUT ;
    USE SIGNAL ;
    PORT
      LAYER M5 ;
        RECT  14.688 0 14.712 0.192 ;
    END
  END o[173]
  PIN o[174]
    DIRECTION OUTPUT ;
    USE SIGNAL ;
    PORT
      LAYER M3 ;
        RECT  14.832 0 14.85 0.038 ;
    END
  END o[174]
  PIN o[175]
    DIRECTION OUTPUT ;
    USE SIGNAL ;
    PORT
      LAYER M5 ;
        RECT  14.88 0 14.904 0.192 ;
    END
  END o[175]
  PIN o[176]
    DIRECTION OUTPUT ;
    USE SIGNAL ;
    PORT
      LAYER M3 ;
        RECT  14.976 0 14.994 0.038 ;
    END
  END o[176]
  PIN o[177]
    DIRECTION OUTPUT ;
    USE SIGNAL ;
    PORT
      LAYER M5 ;
        RECT  15.072 0 15.096 0.192 ;
    END
  END o[177]
  PIN o[178]
    DIRECTION OUTPUT ;
    USE SIGNAL ;
    PORT
      LAYER M3 ;
        RECT  15.12 0 15.138 0.038 ;
    END
  END o[178]
  PIN o[179]
    DIRECTION OUTPUT ;
    USE SIGNAL ;
    PORT
      LAYER M5 ;
        RECT  15.264 0 15.288 0.192 ;
    END
  END o[179]
  PIN o[17]
    DIRECTION OUTPUT ;
    USE SIGNAL ;
    PORT
      LAYER M3 ;
        RECT  3.672 0 3.69 0.038 ;
    END
  END o[17]
  PIN o[180]
    DIRECTION OUTPUT ;
    USE SIGNAL ;
    PORT
      LAYER M3 ;
        RECT  15.336 0 15.354 0.038 ;
    END
  END o[180]
  PIN o[181]
    DIRECTION OUTPUT ;
    USE SIGNAL ;
    PORT
      LAYER M5 ;
        RECT  15.456 0 15.48 0.192 ;
    END
  END o[181]
  PIN o[182]
    DIRECTION OUTPUT ;
    USE SIGNAL ;
    PORT
      LAYER M3 ;
        RECT  15.48 0 15.498 0.038 ;
    END
  END o[182]
  PIN o[183]
    DIRECTION OUTPUT ;
    USE SIGNAL ;
    PORT
      LAYER M5 ;
        RECT  15.552 0 15.576 0.192 ;
    END
  END o[183]
  PIN o[184]
    DIRECTION OUTPUT ;
    USE SIGNAL ;
    PORT
      LAYER M3 ;
        RECT  15.696 0 15.714 0.038 ;
    END
  END o[184]
  PIN o[185]
    DIRECTION OUTPUT ;
    USE SIGNAL ;
    PORT
      LAYER M5 ;
        RECT  15.744 0 15.768 0.192 ;
    END
  END o[185]
  PIN o[186]
    DIRECTION OUTPUT ;
    USE SIGNAL ;
    PORT
      LAYER M3 ;
        RECT  15.84 0 15.858 0.038 ;
    END
  END o[186]
  PIN o[187]
    DIRECTION OUTPUT ;
    USE SIGNAL ;
    PORT
      LAYER M5 ;
        RECT  15.936 0 15.96 0.192 ;
    END
  END o[187]
  PIN o[188]
    DIRECTION OUTPUT ;
    USE SIGNAL ;
    PORT
      LAYER M3 ;
        RECT  16.056 0 16.074 0.038 ;
    END
  END o[188]
  PIN o[189]
    DIRECTION OUTPUT ;
    USE SIGNAL ;
    PORT
      LAYER M5 ;
        RECT  16.128 0 16.152 0.192 ;
    END
  END o[189]
  PIN o[18]
    DIRECTION OUTPUT ;
    USE SIGNAL ;
    PORT
      LAYER M5 ;
        RECT  3.792 0 3.816 0.192 ;
    END
  END o[18]
  PIN o[190]
    DIRECTION OUTPUT ;
    USE SIGNAL ;
    PORT
      LAYER M3 ;
        RECT  16.2 0 16.218 0.038 ;
    END
  END o[190]
  PIN o[191]
    DIRECTION OUTPUT ;
    USE SIGNAL ;
    PORT
      LAYER M5 ;
        RECT  16.32 0 16.344 0.192 ;
    END
  END o[191]
  PIN o[192]
    DIRECTION OUTPUT ;
    USE SIGNAL ;
    PORT
      LAYER M3 ;
        RECT  16.344 0 16.362 0.038 ;
    END
  END o[192]
  PIN o[193]
    DIRECTION OUTPUT ;
    USE SIGNAL ;
    PORT
      LAYER M5 ;
        RECT  16.944 0 16.968 0.192 ;
    END
  END o[193]
  PIN o[194]
    DIRECTION OUTPUT ;
    USE SIGNAL ;
    PORT
      LAYER M3 ;
        RECT  16.992 0 17.01 0.038 ;
    END
  END o[194]
  PIN o[195]
    DIRECTION OUTPUT ;
    USE SIGNAL ;
    PORT
      LAYER M5 ;
        RECT  17.04 0 17.064 0.192 ;
    END
  END o[195]
  PIN o[196]
    DIRECTION OUTPUT ;
    USE SIGNAL ;
    PORT
      LAYER M3 ;
        RECT  17.064 0 17.082 0.038 ;
    END
  END o[196]
  PIN o[197]
    DIRECTION OUTPUT ;
    USE SIGNAL ;
    PORT
      LAYER M5 ;
        RECT  17.136 0 17.16 0.192 ;
    END
  END o[197]
  PIN o[198]
    DIRECTION OUTPUT ;
    USE SIGNAL ;
    PORT
      LAYER M3 ;
        RECT  17.136 0 17.154 0.038 ;
    END
  END o[198]
  PIN o[199]
    DIRECTION OUTPUT ;
    USE SIGNAL ;
    PORT
      LAYER M5 ;
        RECT  17.232 0 17.256 0.192 ;
    END
  END o[199]
  PIN o[19]
    DIRECTION OUTPUT ;
    USE SIGNAL ;
    PORT
      LAYER M3 ;
        RECT  3.816 0 3.834 0.038 ;
    END
  END o[19]
  PIN o[1]
    DIRECTION OUTPUT ;
    USE SIGNAL ;
    PORT
      LAYER M3 ;
        RECT  2.304 0 2.322 0.038 ;
    END
  END o[1]
  PIN o[200]
    DIRECTION OUTPUT ;
    USE SIGNAL ;
    PORT
      LAYER M3 ;
        RECT  17.208 0 17.226 0.038 ;
    END
  END o[200]
  PIN o[201]
    DIRECTION OUTPUT ;
    USE SIGNAL ;
    PORT
      LAYER M5 ;
        RECT  17.328 0 17.352 0.192 ;
    END
  END o[201]
  PIN o[202]
    DIRECTION OUTPUT ;
    USE SIGNAL ;
    PORT
      LAYER M3 ;
        RECT  17.28 0 17.298 0.038 ;
    END
  END o[202]
  PIN o[203]
    DIRECTION OUTPUT ;
    USE SIGNAL ;
    PORT
      LAYER M5 ;
        RECT  17.424 0 17.448 0.192 ;
    END
  END o[203]
  PIN o[204]
    DIRECTION OUTPUT ;
    USE SIGNAL ;
    PORT
      LAYER M3 ;
        RECT  17.424 0 17.442 0.038 ;
    END
  END o[204]
  PIN o[205]
    DIRECTION OUTPUT ;
    USE SIGNAL ;
    PORT
      LAYER M5 ;
        RECT  17.52 0 17.544 0.192 ;
    END
  END o[205]
  PIN o[206]
    DIRECTION OUTPUT ;
    USE SIGNAL ;
    PORT
      LAYER M3 ;
        RECT  17.568 0 17.586 0.038 ;
    END
  END o[206]
  PIN o[207]
    DIRECTION OUTPUT ;
    USE SIGNAL ;
    PORT
      LAYER M5 ;
        RECT  17.712 0 17.736 0.192 ;
    END
  END o[207]
  PIN o[208]
    DIRECTION OUTPUT ;
    USE SIGNAL ;
    PORT
      LAYER M3 ;
        RECT  17.784 0 17.802 0.038 ;
    END
  END o[208]
  PIN o[209]
    DIRECTION OUTPUT ;
    USE SIGNAL ;
    PORT
      LAYER M5 ;
        RECT  17.808 0 17.832 0.192 ;
    END
  END o[209]
  PIN o[20]
    DIRECTION OUTPUT ;
    USE SIGNAL ;
    PORT
      LAYER M5 ;
        RECT  3.888 0 3.912 0.192 ;
    END
  END o[20]
  PIN o[210]
    DIRECTION OUTPUT ;
    USE SIGNAL ;
    PORT
      LAYER M3 ;
        RECT  17.928 0 17.946 0.038 ;
    END
  END o[210]
  PIN o[211]
    DIRECTION OUTPUT ;
    USE SIGNAL ;
    PORT
      LAYER M5 ;
        RECT  18 0 18.024 0.192 ;
    END
  END o[211]
  PIN o[212]
    DIRECTION OUTPUT ;
    USE SIGNAL ;
    PORT
      LAYER M3 ;
        RECT  18.144 0 18.162 0.038 ;
    END
  END o[212]
  PIN o[213]
    DIRECTION OUTPUT ;
    USE SIGNAL ;
    PORT
      LAYER M5 ;
        RECT  18.192 0 18.216 0.192 ;
    END
  END o[213]
  PIN o[214]
    DIRECTION OUTPUT ;
    USE SIGNAL ;
    PORT
      LAYER M3 ;
        RECT  18.288 0 18.306 0.038 ;
    END
  END o[214]
  PIN o[215]
    DIRECTION OUTPUT ;
    USE SIGNAL ;
    PORT
      LAYER M5 ;
        RECT  18.384 0 18.408 0.192 ;
    END
  END o[215]
  PIN o[216]
    DIRECTION OUTPUT ;
    USE SIGNAL ;
    PORT
      LAYER M3 ;
        RECT  18.432 0 18.45 0.038 ;
    END
  END o[216]
  PIN o[217]
    DIRECTION OUTPUT ;
    USE SIGNAL ;
    PORT
      LAYER M5 ;
        RECT  18.576 0 18.6 0.192 ;
    END
  END o[217]
  PIN o[218]
    DIRECTION OUTPUT ;
    USE SIGNAL ;
    PORT
      LAYER M3 ;
        RECT  18.648 0 18.666 0.038 ;
    END
  END o[218]
  PIN o[219]
    DIRECTION OUTPUT ;
    USE SIGNAL ;
    PORT
      LAYER M5 ;
        RECT  18.672 0 18.696 0.192 ;
    END
  END o[219]
  PIN o[21]
    DIRECTION OUTPUT ;
    USE SIGNAL ;
    PORT
      LAYER M3 ;
        RECT  4.032 0 4.05 0.038 ;
    END
  END o[21]
  PIN o[220]
    DIRECTION OUTPUT ;
    USE SIGNAL ;
    PORT
      LAYER M3 ;
        RECT  18.792 0 18.81 0.038 ;
    END
  END o[220]
  PIN o[221]
    DIRECTION OUTPUT ;
    USE SIGNAL ;
    PORT
      LAYER M5 ;
        RECT  18.864 0 18.888 0.192 ;
    END
  END o[221]
  PIN o[222]
    DIRECTION OUTPUT ;
    USE SIGNAL ;
    PORT
      LAYER M3 ;
        RECT  19.008 0 19.026 0.038 ;
    END
  END o[222]
  PIN o[223]
    DIRECTION OUTPUT ;
    USE SIGNAL ;
    PORT
      LAYER M5 ;
        RECT  19.056 0 19.08 0.192 ;
    END
  END o[223]
  PIN o[224]
    DIRECTION OUTPUT ;
    USE SIGNAL ;
    PORT
      LAYER M3 ;
        RECT  19.152 0 19.17 0.038 ;
    END
  END o[224]
  PIN o[225]
    DIRECTION OUTPUT ;
    USE SIGNAL ;
    PORT
      LAYER M5 ;
        RECT  19.248 0 19.272 0.192 ;
    END
  END o[225]
  PIN o[226]
    DIRECTION OUTPUT ;
    USE SIGNAL ;
    PORT
      LAYER M3 ;
        RECT  19.296 0 19.314 0.038 ;
    END
  END o[226]
  PIN o[227]
    DIRECTION OUTPUT ;
    USE SIGNAL ;
    PORT
      LAYER M5 ;
        RECT  19.44 0 19.464 0.192 ;
    END
  END o[227]
  PIN o[228]
    DIRECTION OUTPUT ;
    USE SIGNAL ;
    PORT
      LAYER M3 ;
        RECT  19.512 0 19.53 0.038 ;
    END
  END o[228]
  PIN o[229]
    DIRECTION OUTPUT ;
    USE SIGNAL ;
    PORT
      LAYER M5 ;
        RECT  19.632 0 19.656 0.192 ;
    END
  END o[229]
  PIN o[22]
    DIRECTION OUTPUT ;
    USE SIGNAL ;
    PORT
      LAYER M5 ;
        RECT  4.08 0 4.104 0.192 ;
    END
  END o[22]
  PIN o[230]
    DIRECTION OUTPUT ;
    USE SIGNAL ;
    PORT
      LAYER M3 ;
        RECT  19.656 0 19.674 0.038 ;
    END
  END o[230]
  PIN o[231]
    DIRECTION OUTPUT ;
    USE SIGNAL ;
    PORT
      LAYER M5 ;
        RECT  19.728 0 19.752 0.192 ;
    END
  END o[231]
  PIN o[232]
    DIRECTION OUTPUT ;
    USE SIGNAL ;
    PORT
      LAYER M3 ;
        RECT  19.872 0 19.89 0.038 ;
    END
  END o[232]
  PIN o[233]
    DIRECTION OUTPUT ;
    USE SIGNAL ;
    PORT
      LAYER M5 ;
        RECT  19.92 0 19.944 0.192 ;
    END
  END o[233]
  PIN o[234]
    DIRECTION OUTPUT ;
    USE SIGNAL ;
    PORT
      LAYER M3 ;
        RECT  20.016 0 20.034 0.038 ;
    END
  END o[234]
  PIN o[235]
    DIRECTION OUTPUT ;
    USE SIGNAL ;
    PORT
      LAYER M5 ;
        RECT  20.112 0 20.136 0.192 ;
    END
  END o[235]
  PIN o[236]
    DIRECTION OUTPUT ;
    USE SIGNAL ;
    PORT
      LAYER M3 ;
        RECT  20.232 0 20.25 0.038 ;
    END
  END o[236]
  PIN o[237]
    DIRECTION OUTPUT ;
    USE SIGNAL ;
    PORT
      LAYER M5 ;
        RECT  20.304 0 20.328 0.192 ;
    END
  END o[237]
  PIN o[238]
    DIRECTION OUTPUT ;
    USE SIGNAL ;
    PORT
      LAYER M3 ;
        RECT  20.376 0 20.394 0.038 ;
    END
  END o[238]
  PIN o[239]
    DIRECTION OUTPUT ;
    USE SIGNAL ;
    PORT
      LAYER M5 ;
        RECT  20.496 0 20.52 0.192 ;
    END
  END o[239]
  PIN o[23]
    DIRECTION OUTPUT ;
    USE SIGNAL ;
    PORT
      LAYER M3 ;
        RECT  4.176 0 4.194 0.038 ;
    END
  END o[23]
  PIN o[240]
    DIRECTION OUTPUT ;
    USE SIGNAL ;
    PORT
      LAYER M3 ;
        RECT  20.52 0 20.538 0.038 ;
    END
  END o[240]
  PIN o[241]
    DIRECTION OUTPUT ;
    USE SIGNAL ;
    PORT
      LAYER M5 ;
        RECT  20.592 0 20.616 0.192 ;
    END
  END o[241]
  PIN o[242]
    DIRECTION OUTPUT ;
    USE SIGNAL ;
    PORT
      LAYER M3 ;
        RECT  20.736 0 20.754 0.038 ;
    END
  END o[242]
  PIN o[243]
    DIRECTION OUTPUT ;
    USE SIGNAL ;
    PORT
      LAYER M5 ;
        RECT  20.784 0 20.808 0.192 ;
    END
  END o[243]
  PIN o[244]
    DIRECTION OUTPUT ;
    USE SIGNAL ;
    PORT
      LAYER M3 ;
        RECT  20.88 0 20.898 0.038 ;
    END
  END o[244]
  PIN o[245]
    DIRECTION OUTPUT ;
    USE SIGNAL ;
    PORT
      LAYER M5 ;
        RECT  20.976 0 21 0.192 ;
    END
  END o[245]
  PIN o[246]
    DIRECTION OUTPUT ;
    USE SIGNAL ;
    PORT
      LAYER M3 ;
        RECT  21.096 0 21.114 0.038 ;
    END
  END o[246]
  PIN o[247]
    DIRECTION OUTPUT ;
    USE SIGNAL ;
    PORT
      LAYER M5 ;
        RECT  21.168 0 21.192 0.192 ;
    END
  END o[247]
  PIN o[248]
    DIRECTION OUTPUT ;
    USE SIGNAL ;
    PORT
      LAYER M3 ;
        RECT  21.24 0 21.258 0.038 ;
    END
  END o[248]
  PIN o[249]
    DIRECTION OUTPUT ;
    USE SIGNAL ;
    PORT
      LAYER M5 ;
        RECT  21.36 0 21.384 0.192 ;
    END
  END o[249]
  PIN o[24]
    DIRECTION OUTPUT ;
    USE SIGNAL ;
    PORT
      LAYER M5 ;
        RECT  4.272 0 4.296 0.192 ;
    END
  END o[24]
  PIN o[250]
    DIRECTION OUTPUT ;
    USE SIGNAL ;
    PORT
      LAYER M3 ;
        RECT  21.384 0 21.402 0.038 ;
    END
  END o[250]
  PIN o[251]
    DIRECTION OUTPUT ;
    USE SIGNAL ;
    PORT
      LAYER M5 ;
        RECT  21.456 0 21.48 0.192 ;
    END
  END o[251]
  PIN o[252]
    DIRECTION OUTPUT ;
    USE SIGNAL ;
    PORT
      LAYER M3 ;
        RECT  21.6 0 21.618 0.038 ;
    END
  END o[252]
  PIN o[253]
    DIRECTION OUTPUT ;
    USE SIGNAL ;
    PORT
      LAYER M5 ;
        RECT  21.648 0 21.672 0.192 ;
    END
  END o[253]
  PIN o[254]
    DIRECTION OUTPUT ;
    USE SIGNAL ;
    PORT
      LAYER M3 ;
        RECT  21.744 0 21.762 0.038 ;
    END
  END o[254]
  PIN o[255]
    DIRECTION OUTPUT ;
    USE SIGNAL ;
    PORT
      LAYER M5 ;
        RECT  21.744 0 21.768 0.192 ;
    END
  END o[255]
  PIN o[256]
    DIRECTION OUTPUT ;
    USE SIGNAL ;
    PORT
      LAYER M3 ;
        RECT  22.392 0 22.41 0.038 ;
    END
  END o[256]
  PIN o[257]
    DIRECTION OUTPUT ;
    USE SIGNAL ;
    PORT
      LAYER M5 ;
        RECT  22.416 0 22.44 0.192 ;
    END
  END o[257]
  PIN o[258]
    DIRECTION OUTPUT ;
    USE SIGNAL ;
    PORT
      LAYER M3 ;
        RECT  22.464 0 22.482 0.038 ;
    END
  END o[258]
  PIN o[259]
    DIRECTION OUTPUT ;
    USE SIGNAL ;
    PORT
      LAYER M5 ;
        RECT  22.512 0 22.536 0.192 ;
    END
  END o[259]
  PIN o[25]
    DIRECTION OUTPUT ;
    USE SIGNAL ;
    PORT
      LAYER M3 ;
        RECT  4.392 0 4.41 0.038 ;
    END
  END o[25]
  PIN o[260]
    DIRECTION OUTPUT ;
    USE SIGNAL ;
    PORT
      LAYER M3 ;
        RECT  22.536 0 22.554 0.038 ;
    END
  END o[260]
  PIN o[261]
    DIRECTION OUTPUT ;
    USE SIGNAL ;
    PORT
      LAYER M5 ;
        RECT  22.608 0 22.632 0.192 ;
    END
  END o[261]
  PIN o[262]
    DIRECTION OUTPUT ;
    USE SIGNAL ;
    PORT
      LAYER M3 ;
        RECT  22.608 0 22.626 0.038 ;
    END
  END o[262]
  PIN o[263]
    DIRECTION OUTPUT ;
    USE SIGNAL ;
    PORT
      LAYER M5 ;
        RECT  22.704 0 22.728 0.192 ;
    END
  END o[263]
  PIN o[264]
    DIRECTION OUTPUT ;
    USE SIGNAL ;
    PORT
      LAYER M3 ;
        RECT  22.68 0 22.698 0.038 ;
    END
  END o[264]
  PIN o[265]
    DIRECTION OUTPUT ;
    USE SIGNAL ;
    PORT
      LAYER M5 ;
        RECT  22.8 0 22.824 0.192 ;
    END
  END o[265]
  PIN o[266]
    DIRECTION OUTPUT ;
    USE SIGNAL ;
    PORT
      LAYER M3 ;
        RECT  22.824 0 22.842 0.038 ;
    END
  END o[266]
  PIN o[267]
    DIRECTION OUTPUT ;
    USE SIGNAL ;
    PORT
      LAYER M5 ;
        RECT  22.896 0 22.92 0.192 ;
    END
  END o[267]
  PIN o[268]
    DIRECTION OUTPUT ;
    USE SIGNAL ;
    PORT
      LAYER M3 ;
        RECT  22.968 0 22.986 0.038 ;
    END
  END o[268]
  PIN o[269]
    DIRECTION OUTPUT ;
    USE SIGNAL ;
    PORT
      LAYER M5 ;
        RECT  23.088 0 23.112 0.192 ;
    END
  END o[269]
  PIN o[26]
    DIRECTION OUTPUT ;
    USE SIGNAL ;
    PORT
      LAYER M5 ;
        RECT  4.464 0 4.488 0.192 ;
    END
  END o[26]
  PIN o[270]
    DIRECTION OUTPUT ;
    USE SIGNAL ;
    PORT
      LAYER M3 ;
        RECT  23.184 0 23.202 0.038 ;
    END
  END o[270]
  PIN o[271]
    DIRECTION OUTPUT ;
    USE SIGNAL ;
    PORT
      LAYER M5 ;
        RECT  23.28 0 23.304 0.192 ;
    END
  END o[271]
  PIN o[272]
    DIRECTION OUTPUT ;
    USE SIGNAL ;
    PORT
      LAYER M3 ;
        RECT  23.328 0 23.346 0.038 ;
    END
  END o[272]
  PIN o[273]
    DIRECTION OUTPUT ;
    USE SIGNAL ;
    PORT
      LAYER M5 ;
        RECT  23.376 0 23.4 0.192 ;
    END
  END o[273]
  PIN o[274]
    DIRECTION OUTPUT ;
    USE SIGNAL ;
    PORT
      LAYER M3 ;
        RECT  23.472 0 23.49 0.038 ;
    END
  END o[274]
  PIN o[275]
    DIRECTION OUTPUT ;
    USE SIGNAL ;
    PORT
      LAYER M5 ;
        RECT  23.568 0 23.592 0.192 ;
    END
  END o[275]
  PIN o[276]
    DIRECTION OUTPUT ;
    USE SIGNAL ;
    PORT
      LAYER M3 ;
        RECT  23.688 0 23.706 0.038 ;
    END
  END o[276]
  PIN o[277]
    DIRECTION OUTPUT ;
    USE SIGNAL ;
    PORT
      LAYER M5 ;
        RECT  23.76 0 23.784 0.192 ;
    END
  END o[277]
  PIN o[278]
    DIRECTION OUTPUT ;
    USE SIGNAL ;
    PORT
      LAYER M3 ;
        RECT  23.832 0 23.85 0.038 ;
    END
  END o[278]
  PIN o[279]
    DIRECTION OUTPUT ;
    USE SIGNAL ;
    PORT
      LAYER M5 ;
        RECT  23.952 0 23.976 0.192 ;
    END
  END o[279]
  PIN o[27]
    DIRECTION OUTPUT ;
    USE SIGNAL ;
    PORT
      LAYER M3 ;
        RECT  4.536 0 4.554 0.038 ;
    END
  END o[27]
  PIN o[280]
    DIRECTION OUTPUT ;
    USE SIGNAL ;
    PORT
      LAYER M3 ;
        RECT  24.048 0 24.066 0.038 ;
    END
  END o[280]
  PIN o[281]
    DIRECTION OUTPUT ;
    USE SIGNAL ;
    PORT
      LAYER M5 ;
        RECT  24.144 0 24.168 0.192 ;
    END
  END o[281]
  PIN o[282]
    DIRECTION OUTPUT ;
    USE SIGNAL ;
    PORT
      LAYER M3 ;
        RECT  24.192 0 24.21 0.038 ;
    END
  END o[282]
  PIN o[283]
    DIRECTION OUTPUT ;
    USE SIGNAL ;
    PORT
      LAYER M5 ;
        RECT  24.24 0 24.264 0.192 ;
    END
  END o[283]
  PIN o[284]
    DIRECTION OUTPUT ;
    USE SIGNAL ;
    PORT
      LAYER M3 ;
        RECT  24.408 0 24.426 0.038 ;
    END
  END o[284]
  PIN o[285]
    DIRECTION OUTPUT ;
    USE SIGNAL ;
    PORT
      LAYER M3 ;
        RECT  38.664 0 38.682 0.038 ;
    END
  END o[285]
  PIN o[286]
    DIRECTION OUTPUT ;
    USE SIGNAL ;
    PORT
      LAYER M5 ;
        RECT  38.64 0 38.664 0.192 ;
    END
  END o[286]
  PIN o[287]
    DIRECTION OUTPUT ;
    USE SIGNAL ;
    PORT
      LAYER M3 ;
        RECT  38.736 0 38.754 0.038 ;
    END
  END o[287]
  PIN o[288]
    DIRECTION OUTPUT ;
    USE SIGNAL ;
    PORT
      LAYER M5 ;
        RECT  38.736 0 38.76 0.192 ;
    END
  END o[288]
  PIN o[289]
    DIRECTION OUTPUT ;
    USE SIGNAL ;
    PORT
      LAYER M3 ;
        RECT  38.808 0 38.826 0.038 ;
    END
  END o[289]
  PIN o[28]
    DIRECTION OUTPUT ;
    USE SIGNAL ;
    PORT
      LAYER M5 ;
        RECT  4.656 0 4.68 0.192 ;
    END
  END o[28]
  PIN o[290]
    DIRECTION OUTPUT ;
    USE SIGNAL ;
    PORT
      LAYER M5 ;
        RECT  38.832 0 38.856 0.192 ;
    END
  END o[290]
  PIN o[291]
    DIRECTION OUTPUT ;
    USE SIGNAL ;
    PORT
      LAYER M3 ;
        RECT  38.88 0 38.898 0.038 ;
    END
  END o[291]
  PIN o[292]
    DIRECTION OUTPUT ;
    USE SIGNAL ;
    PORT
      LAYER M5 ;
        RECT  38.928 0 38.952 0.192 ;
    END
  END o[292]
  PIN o[293]
    DIRECTION OUTPUT ;
    USE SIGNAL ;
    PORT
      LAYER M3 ;
        RECT  38.952 0 38.97 0.038 ;
    END
  END o[293]
  PIN o[294]
    DIRECTION OUTPUT ;
    USE SIGNAL ;
    PORT
      LAYER M5 ;
        RECT  39.024 0 39.048 0.192 ;
    END
  END o[294]
  PIN o[295]
    DIRECTION OUTPUT ;
    USE SIGNAL ;
    PORT
      LAYER M3 ;
        RECT  39.168 0 39.186 0.038 ;
    END
  END o[295]
  PIN o[296]
    DIRECTION OUTPUT ;
    USE SIGNAL ;
    PORT
      LAYER M5 ;
        RECT  39.216 0 39.24 0.192 ;
    END
  END o[296]
  PIN o[297]
    DIRECTION OUTPUT ;
    USE SIGNAL ;
    PORT
      LAYER M3 ;
        RECT  39.312 0 39.33 0.038 ;
    END
  END o[297]
  PIN o[298]
    DIRECTION OUTPUT ;
    USE SIGNAL ;
    PORT
      LAYER M5 ;
        RECT  39.408 0 39.432 0.192 ;
    END
  END o[298]
  PIN o[299]
    DIRECTION OUTPUT ;
    USE SIGNAL ;
    PORT
      LAYER M3 ;
        RECT  39.528 0 39.546 0.038 ;
    END
  END o[299]
  PIN o[29]
    DIRECTION OUTPUT ;
    USE SIGNAL ;
    PORT
      LAYER M3 ;
        RECT  4.752 0 4.77 0.038 ;
    END
  END o[29]
  PIN o[2]
    DIRECTION OUTPUT ;
    USE SIGNAL ;
    PORT
      LAYER M5 ;
        RECT  2.352 0 2.376 0.192 ;
    END
  END o[2]
  PIN o[300]
    DIRECTION OUTPUT ;
    USE SIGNAL ;
    PORT
      LAYER M5 ;
        RECT  24.432 0 24.456 0.192 ;
    END
  END o[300]
  PIN o[301]
    DIRECTION OUTPUT ;
    USE SIGNAL ;
    PORT
      LAYER M3 ;
        RECT  24.552 0 24.57 0.038 ;
    END
  END o[301]
  PIN o[302]
    DIRECTION OUTPUT ;
    USE SIGNAL ;
    PORT
      LAYER M5 ;
        RECT  24.624 0 24.648 0.192 ;
    END
  END o[302]
  PIN o[303]
    DIRECTION OUTPUT ;
    USE SIGNAL ;
    PORT
      LAYER M3 ;
        RECT  24.696 0 24.714 0.038 ;
    END
  END o[303]
  PIN o[304]
    DIRECTION OUTPUT ;
    USE SIGNAL ;
    PORT
      LAYER M5 ;
        RECT  24.816 0 24.84 0.192 ;
    END
  END o[304]
  PIN o[305]
    DIRECTION OUTPUT ;
    USE SIGNAL ;
    PORT
      LAYER M3 ;
        RECT  24.912 0 24.93 0.038 ;
    END
  END o[305]
  PIN o[306]
    DIRECTION OUTPUT ;
    USE SIGNAL ;
    PORT
      LAYER M5 ;
        RECT  25.008 0 25.032 0.192 ;
    END
  END o[306]
  PIN o[307]
    DIRECTION OUTPUT ;
    USE SIGNAL ;
    PORT
      LAYER M3 ;
        RECT  25.056 0 25.074 0.038 ;
    END
  END o[307]
  PIN o[308]
    DIRECTION OUTPUT ;
    USE SIGNAL ;
    PORT
      LAYER M5 ;
        RECT  25.2 0 25.224 0.192 ;
    END
  END o[308]
  PIN o[309]
    DIRECTION OUTPUT ;
    USE SIGNAL ;
    PORT
      LAYER M3 ;
        RECT  25.272 0 25.29 0.038 ;
    END
  END o[309]
  PIN o[30]
    DIRECTION OUTPUT ;
    USE SIGNAL ;
    PORT
      LAYER M5 ;
        RECT  4.848 0 4.872 0.192 ;
    END
  END o[30]
  PIN o[310]
    DIRECTION OUTPUT ;
    USE SIGNAL ;
    PORT
      LAYER M5 ;
        RECT  25.296 0 25.32 0.192 ;
    END
  END o[310]
  PIN o[311]
    DIRECTION OUTPUT ;
    USE SIGNAL ;
    PORT
      LAYER M3 ;
        RECT  25.416 0 25.434 0.038 ;
    END
  END o[311]
  PIN o[312]
    DIRECTION OUTPUT ;
    USE SIGNAL ;
    PORT
      LAYER M5 ;
        RECT  25.488 0 25.512 0.192 ;
    END
  END o[312]
  PIN o[313]
    DIRECTION OUTPUT ;
    USE SIGNAL ;
    PORT
      LAYER M3 ;
        RECT  25.56 0 25.578 0.038 ;
    END
  END o[313]
  PIN o[314]
    DIRECTION OUTPUT ;
    USE SIGNAL ;
    PORT
      LAYER M5 ;
        RECT  25.68 0 25.704 0.192 ;
    END
  END o[314]
  PIN o[315]
    DIRECTION OUTPUT ;
    USE SIGNAL ;
    PORT
      LAYER M3 ;
        RECT  25.776 0 25.794 0.038 ;
    END
  END o[315]
  PIN o[316]
    DIRECTION OUTPUT ;
    USE SIGNAL ;
    PORT
      LAYER M5 ;
        RECT  25.872 0 25.896 0.192 ;
    END
  END o[316]
  PIN o[317]
    DIRECTION OUTPUT ;
    USE SIGNAL ;
    PORT
      LAYER M3 ;
        RECT  25.92 0 25.938 0.038 ;
    END
  END o[317]
  PIN o[318]
    DIRECTION OUTPUT ;
    USE SIGNAL ;
    PORT
      LAYER M5 ;
        RECT  26.064 0 26.088 0.192 ;
    END
  END o[318]
  PIN o[319]
    DIRECTION OUTPUT ;
    USE SIGNAL ;
    PORT
      LAYER M3 ;
        RECT  26.136 0 26.154 0.038 ;
    END
  END o[319]
  PIN o[31]
    DIRECTION OUTPUT ;
    USE SIGNAL ;
    PORT
      LAYER M3 ;
        RECT  4.896 0 4.914 0.038 ;
    END
  END o[31]
  PIN o[320]
    DIRECTION OUTPUT ;
    USE SIGNAL ;
    PORT
      LAYER M5 ;
        RECT  26.16 0 26.184 0.192 ;
    END
  END o[320]
  PIN o[321]
    DIRECTION OUTPUT ;
    USE SIGNAL ;
    PORT
      LAYER M3 ;
        RECT  26.28 0 26.298 0.038 ;
    END
  END o[321]
  PIN o[322]
    DIRECTION OUTPUT ;
    USE SIGNAL ;
    PORT
      LAYER M5 ;
        RECT  26.352 0 26.376 0.192 ;
    END
  END o[322]
  PIN o[323]
    DIRECTION OUTPUT ;
    USE SIGNAL ;
    PORT
      LAYER M3 ;
        RECT  26.496 0 26.514 0.038 ;
    END
  END o[323]
  PIN o[324]
    DIRECTION OUTPUT ;
    USE SIGNAL ;
    PORT
      LAYER M5 ;
        RECT  26.544 0 26.568 0.192 ;
    END
  END o[324]
  PIN o[325]
    DIRECTION OUTPUT ;
    USE SIGNAL ;
    PORT
      LAYER M3 ;
        RECT  26.64 0 26.658 0.038 ;
    END
  END o[325]
  PIN o[326]
    DIRECTION OUTPUT ;
    USE SIGNAL ;
    PORT
      LAYER M5 ;
        RECT  26.736 0 26.76 0.192 ;
    END
  END o[326]
  PIN o[327]
    DIRECTION OUTPUT ;
    USE SIGNAL ;
    PORT
      LAYER M3 ;
        RECT  26.784 0 26.802 0.038 ;
    END
  END o[327]
  PIN o[328]
    DIRECTION OUTPUT ;
    USE SIGNAL ;
    PORT
      LAYER M5 ;
        RECT  26.928 0 26.952 0.192 ;
    END
  END o[328]
  PIN o[329]
    DIRECTION OUTPUT ;
    USE SIGNAL ;
    PORT
      LAYER M3 ;
        RECT  27 0 27.018 0.038 ;
    END
  END o[329]
  PIN o[32]
    DIRECTION OUTPUT ;
    USE SIGNAL ;
    PORT
      LAYER M5 ;
        RECT  4.944 0 4.968 0.192 ;
    END
  END o[32]
  PIN o[330]
    DIRECTION OUTPUT ;
    USE SIGNAL ;
    PORT
      LAYER M5 ;
        RECT  27.024 0 27.048 0.192 ;
    END
  END o[330]
  PIN o[331]
    DIRECTION OUTPUT ;
    USE SIGNAL ;
    PORT
      LAYER M3 ;
        RECT  27.144 0 27.162 0.038 ;
    END
  END o[331]
  PIN o[332]
    DIRECTION OUTPUT ;
    USE SIGNAL ;
    PORT
      LAYER M5 ;
        RECT  27.12 0 27.144 0.192 ;
    END
  END o[332]
  PIN o[333]
    DIRECTION OUTPUT ;
    USE SIGNAL ;
    PORT
      LAYER M3 ;
        RECT  27.792 0 27.81 0.038 ;
    END
  END o[333]
  PIN o[334]
    DIRECTION OUTPUT ;
    USE SIGNAL ;
    PORT
      LAYER M5 ;
        RECT  27.744 0 27.768 0.192 ;
    END
  END o[334]
  PIN o[335]
    DIRECTION OUTPUT ;
    USE SIGNAL ;
    PORT
      LAYER M3 ;
        RECT  27.864 0 27.882 0.038 ;
    END
  END o[335]
  PIN o[336]
    DIRECTION OUTPUT ;
    USE SIGNAL ;
    PORT
      LAYER M5 ;
        RECT  27.84 0 27.864 0.192 ;
    END
  END o[336]
  PIN o[337]
    DIRECTION OUTPUT ;
    USE SIGNAL ;
    PORT
      LAYER M3 ;
        RECT  27.936 0 27.954 0.038 ;
    END
  END o[337]
  PIN o[338]
    DIRECTION OUTPUT ;
    USE SIGNAL ;
    PORT
      LAYER M5 ;
        RECT  27.936 0 27.96 0.192 ;
    END
  END o[338]
  PIN o[339]
    DIRECTION OUTPUT ;
    USE SIGNAL ;
    PORT
      LAYER M3 ;
        RECT  28.008 0 28.026 0.038 ;
    END
  END o[339]
  PIN o[33]
    DIRECTION OUTPUT ;
    USE SIGNAL ;
    PORT
      LAYER M3 ;
        RECT  5.04 0 5.058 0.038 ;
    END
  END o[33]
  PIN o[340]
    DIRECTION OUTPUT ;
    USE SIGNAL ;
    PORT
      LAYER M5 ;
        RECT  28.032 0 28.056 0.192 ;
    END
  END o[340]
  PIN o[341]
    DIRECTION OUTPUT ;
    USE SIGNAL ;
    PORT
      LAYER M3 ;
        RECT  28.08 0 28.098 0.038 ;
    END
  END o[341]
  PIN o[342]
    DIRECTION OUTPUT ;
    USE SIGNAL ;
    PORT
      LAYER M5 ;
        RECT  28.128 0 28.152 0.192 ;
    END
  END o[342]
  PIN o[343]
    DIRECTION OUTPUT ;
    USE SIGNAL ;
    PORT
      LAYER M3 ;
        RECT  28.224 0 28.242 0.038 ;
    END
  END o[343]
  PIN o[344]
    DIRECTION OUTPUT ;
    USE SIGNAL ;
    PORT
      LAYER M5 ;
        RECT  28.32 0 28.344 0.192 ;
    END
  END o[344]
  PIN o[345]
    DIRECTION OUTPUT ;
    USE SIGNAL ;
    PORT
      LAYER M3 ;
        RECT  28.368 0 28.386 0.038 ;
    END
  END o[345]
  PIN o[346]
    DIRECTION OUTPUT ;
    USE SIGNAL ;
    PORT
      LAYER M5 ;
        RECT  28.416 0 28.44 0.192 ;
    END
  END o[346]
  PIN o[347]
    DIRECTION OUTPUT ;
    USE SIGNAL ;
    PORT
      LAYER M3 ;
        RECT  28.584 0 28.602 0.038 ;
    END
  END o[347]
  PIN o[348]
    DIRECTION OUTPUT ;
    USE SIGNAL ;
    PORT
      LAYER M5 ;
        RECT  28.608 0 28.632 0.192 ;
    END
  END o[348]
  PIN o[349]
    DIRECTION OUTPUT ;
    USE SIGNAL ;
    PORT
      LAYER M3 ;
        RECT  28.728 0 28.746 0.038 ;
    END
  END o[349]
  PIN o[34]
    DIRECTION OUTPUT ;
    USE SIGNAL ;
    PORT
      LAYER M5 ;
        RECT  5.136 0 5.16 0.192 ;
    END
  END o[34]
  PIN o[350]
    DIRECTION OUTPUT ;
    USE SIGNAL ;
    PORT
      LAYER M5 ;
        RECT  28.8 0 28.824 0.192 ;
    END
  END o[350]
  PIN o[351]
    DIRECTION OUTPUT ;
    USE SIGNAL ;
    PORT
      LAYER M3 ;
        RECT  28.872 0 28.89 0.038 ;
    END
  END o[351]
  PIN o[352]
    DIRECTION OUTPUT ;
    USE SIGNAL ;
    PORT
      LAYER M5 ;
        RECT  28.992 0 29.016 0.192 ;
    END
  END o[352]
  PIN o[353]
    DIRECTION OUTPUT ;
    USE SIGNAL ;
    PORT
      LAYER M3 ;
        RECT  29.088 0 29.106 0.038 ;
    END
  END o[353]
  PIN o[354]
    DIRECTION OUTPUT ;
    USE SIGNAL ;
    PORT
      LAYER M5 ;
        RECT  29.184 0 29.208 0.192 ;
    END
  END o[354]
  PIN o[355]
    DIRECTION OUTPUT ;
    USE SIGNAL ;
    PORT
      LAYER M3 ;
        RECT  29.232 0 29.25 0.038 ;
    END
  END o[355]
  PIN o[356]
    DIRECTION OUTPUT ;
    USE SIGNAL ;
    PORT
      LAYER M5 ;
        RECT  29.376 0 29.4 0.192 ;
    END
  END o[356]
  PIN o[357]
    DIRECTION OUTPUT ;
    USE SIGNAL ;
    PORT
      LAYER M3 ;
        RECT  29.448 0 29.466 0.038 ;
    END
  END o[357]
  PIN o[358]
    DIRECTION OUTPUT ;
    USE SIGNAL ;
    PORT
      LAYER M5 ;
        RECT  29.472 0 29.496 0.192 ;
    END
  END o[358]
  PIN o[359]
    DIRECTION OUTPUT ;
    USE SIGNAL ;
    PORT
      LAYER M3 ;
        RECT  29.592 0 29.61 0.038 ;
    END
  END o[359]
  PIN o[35]
    DIRECTION OUTPUT ;
    USE SIGNAL ;
    PORT
      LAYER M3 ;
        RECT  5.256 0 5.274 0.038 ;
    END
  END o[35]
  PIN o[360]
    DIRECTION OUTPUT ;
    USE SIGNAL ;
    PORT
      LAYER M5 ;
        RECT  29.664 0 29.688 0.192 ;
    END
  END o[360]
  PIN o[361]
    DIRECTION OUTPUT ;
    USE SIGNAL ;
    PORT
      LAYER M3 ;
        RECT  29.736 0 29.754 0.038 ;
    END
  END o[361]
  PIN o[362]
    DIRECTION OUTPUT ;
    USE SIGNAL ;
    PORT
      LAYER M5 ;
        RECT  29.856 0 29.88 0.192 ;
    END
  END o[362]
  PIN o[363]
    DIRECTION OUTPUT ;
    USE SIGNAL ;
    PORT
      LAYER M3 ;
        RECT  29.952 0 29.97 0.038 ;
    END
  END o[363]
  PIN o[364]
    DIRECTION OUTPUT ;
    USE SIGNAL ;
    PORT
      LAYER M5 ;
        RECT  30.048 0 30.072 0.192 ;
    END
  END o[364]
  PIN o[365]
    DIRECTION OUTPUT ;
    USE SIGNAL ;
    PORT
      LAYER M3 ;
        RECT  30.096 0 30.114 0.038 ;
    END
  END o[365]
  PIN o[366]
    DIRECTION OUTPUT ;
    USE SIGNAL ;
    PORT
      LAYER M5 ;
        RECT  30.24 0 30.264 0.192 ;
    END
  END o[366]
  PIN o[367]
    DIRECTION OUTPUT ;
    USE SIGNAL ;
    PORT
      LAYER M3 ;
        RECT  30.312 0 30.33 0.038 ;
    END
  END o[367]
  PIN o[368]
    DIRECTION OUTPUT ;
    USE SIGNAL ;
    PORT
      LAYER M5 ;
        RECT  30.336 0 30.36 0.192 ;
    END
  END o[368]
  PIN o[369]
    DIRECTION OUTPUT ;
    USE SIGNAL ;
    PORT
      LAYER M3 ;
        RECT  30.456 0 30.474 0.038 ;
    END
  END o[369]
  PIN o[36]
    DIRECTION OUTPUT ;
    USE SIGNAL ;
    PORT
      LAYER M5 ;
        RECT  5.328 0 5.352 0.192 ;
    END
  END o[36]
  PIN o[370]
    DIRECTION OUTPUT ;
    USE SIGNAL ;
    PORT
      LAYER M5 ;
        RECT  30.528 0 30.552 0.192 ;
    END
  END o[370]
  PIN o[371]
    DIRECTION OUTPUT ;
    USE SIGNAL ;
    PORT
      LAYER M3 ;
        RECT  30.672 0 30.69 0.038 ;
    END
  END o[371]
  PIN o[372]
    DIRECTION OUTPUT ;
    USE SIGNAL ;
    PORT
      LAYER M5 ;
        RECT  30.72 0 30.744 0.192 ;
    END
  END o[372]
  PIN o[373]
    DIRECTION OUTPUT ;
    USE SIGNAL ;
    PORT
      LAYER M3 ;
        RECT  30.816 0 30.834 0.038 ;
    END
  END o[373]
  PIN o[374]
    DIRECTION OUTPUT ;
    USE SIGNAL ;
    PORT
      LAYER M5 ;
        RECT  30.912 0 30.936 0.192 ;
    END
  END o[374]
  PIN o[375]
    DIRECTION OUTPUT ;
    USE SIGNAL ;
    PORT
      LAYER M3 ;
        RECT  30.96 0 30.978 0.038 ;
    END
  END o[375]
  PIN o[376]
    DIRECTION OUTPUT ;
    USE SIGNAL ;
    PORT
      LAYER M5 ;
        RECT  31.104 0 31.128 0.192 ;
    END
  END o[376]
  PIN o[377]
    DIRECTION OUTPUT ;
    USE SIGNAL ;
    PORT
      LAYER M3 ;
        RECT  31.176 0 31.194 0.038 ;
    END
  END o[377]
  PIN o[378]
    DIRECTION OUTPUT ;
    USE SIGNAL ;
    PORT
      LAYER M5 ;
        RECT  31.2 0 31.224 0.192 ;
    END
  END o[378]
  PIN o[379]
    DIRECTION OUTPUT ;
    USE SIGNAL ;
    PORT
      LAYER M3 ;
        RECT  31.32 0 31.338 0.038 ;
    END
  END o[379]
  PIN o[37]
    DIRECTION OUTPUT ;
    USE SIGNAL ;
    PORT
      LAYER M3 ;
        RECT  5.4 0 5.418 0.038 ;
    END
  END o[37]
  PIN o[380]
    DIRECTION OUTPUT ;
    USE SIGNAL ;
    PORT
      LAYER M5 ;
        RECT  31.392 0 31.416 0.192 ;
    END
  END o[380]
  PIN o[381]
    DIRECTION OUTPUT ;
    USE SIGNAL ;
    PORT
      LAYER M3 ;
        RECT  31.536 0 31.554 0.038 ;
    END
  END o[381]
  PIN o[382]
    DIRECTION OUTPUT ;
    USE SIGNAL ;
    PORT
      LAYER M5 ;
        RECT  31.584 0 31.608 0.192 ;
    END
  END o[382]
  PIN o[383]
    DIRECTION OUTPUT ;
    USE SIGNAL ;
    PORT
      LAYER M3 ;
        RECT  31.68 0 31.698 0.038 ;
    END
  END o[383]
  PIN o[384]
    DIRECTION OUTPUT ;
    USE SIGNAL ;
    PORT
      LAYER M5 ;
        RECT  31.776 0 31.8 0.192 ;
    END
  END o[384]
  PIN o[385]
    DIRECTION OUTPUT ;
    USE SIGNAL ;
    PORT
      LAYER M3 ;
        RECT  31.824 0 31.842 0.038 ;
    END
  END o[385]
  PIN o[386]
    DIRECTION OUTPUT ;
    USE SIGNAL ;
    PORT
      LAYER M5 ;
        RECT  31.968 0 31.992 0.192 ;
    END
  END o[386]
  PIN o[387]
    DIRECTION OUTPUT ;
    USE SIGNAL ;
    PORT
      LAYER M3 ;
        RECT  32.04 0 32.058 0.038 ;
    END
  END o[387]
  PIN o[388]
    DIRECTION OUTPUT ;
    USE SIGNAL ;
    PORT
      LAYER M5 ;
        RECT  32.16 0 32.184 0.192 ;
    END
  END o[388]
  PIN o[389]
    DIRECTION OUTPUT ;
    USE SIGNAL ;
    PORT
      LAYER M3 ;
        RECT  32.184 0 32.202 0.038 ;
    END
  END o[389]
  PIN o[38]
    DIRECTION OUTPUT ;
    USE SIGNAL ;
    PORT
      LAYER M5 ;
        RECT  5.52 0 5.544 0.192 ;
    END
  END o[38]
  PIN o[390]
    DIRECTION OUTPUT ;
    USE SIGNAL ;
    PORT
      LAYER M5 ;
        RECT  32.256 0 32.28 0.192 ;
    END
  END o[390]
  PIN o[391]
    DIRECTION OUTPUT ;
    USE SIGNAL ;
    PORT
      LAYER M3 ;
        RECT  32.4 0 32.418 0.038 ;
    END
  END o[391]
  PIN o[392]
    DIRECTION OUTPUT ;
    USE SIGNAL ;
    PORT
      LAYER M5 ;
        RECT  32.448 0 32.472 0.192 ;
    END
  END o[392]
  PIN o[393]
    DIRECTION OUTPUT ;
    USE SIGNAL ;
    PORT
      LAYER M3 ;
        RECT  32.544 0 32.562 0.038 ;
    END
  END o[393]
  PIN o[394]
    DIRECTION OUTPUT ;
    USE SIGNAL ;
    PORT
      LAYER M5 ;
        RECT  32.544 0 32.568 0.192 ;
    END
  END o[394]
  PIN o[395]
    DIRECTION OUTPUT ;
    USE SIGNAL ;
    PORT
      LAYER M3 ;
        RECT  33.192 0 33.21 0.038 ;
    END
  END o[395]
  PIN o[396]
    DIRECTION OUTPUT ;
    USE SIGNAL ;
    PORT
      LAYER M5 ;
        RECT  33.216 0 33.24 0.192 ;
    END
  END o[396]
  PIN o[397]
    DIRECTION OUTPUT ;
    USE SIGNAL ;
    PORT
      LAYER M3 ;
        RECT  33.264 0 33.282 0.038 ;
    END
  END o[397]
  PIN o[398]
    DIRECTION OUTPUT ;
    USE SIGNAL ;
    PORT
      LAYER M5 ;
        RECT  33.312 0 33.336 0.192 ;
    END
  END o[398]
  PIN o[399]
    DIRECTION OUTPUT ;
    USE SIGNAL ;
    PORT
      LAYER M3 ;
        RECT  33.336 0 33.354 0.038 ;
    END
  END o[399]
  PIN o[39]
    DIRECTION OUTPUT ;
    USE SIGNAL ;
    PORT
      LAYER M3 ;
        RECT  5.544 0 5.562 0.038 ;
    END
  END o[39]
  PIN o[3]
    DIRECTION OUTPUT ;
    USE SIGNAL ;
    PORT
      LAYER M3 ;
        RECT  2.448 0 2.466 0.038 ;
    END
  END o[3]
  PIN o[400]
    DIRECTION OUTPUT ;
    USE SIGNAL ;
    PORT
      LAYER M5 ;
        RECT  33.408 0 33.432 0.192 ;
    END
  END o[400]
  PIN o[401]
    DIRECTION OUTPUT ;
    USE SIGNAL ;
    PORT
      LAYER M3 ;
        RECT  33.408 0 33.426 0.038 ;
    END
  END o[401]
  PIN o[402]
    DIRECTION OUTPUT ;
    USE SIGNAL ;
    PORT
      LAYER M5 ;
        RECT  33.504 0 33.528 0.192 ;
    END
  END o[402]
  PIN o[403]
    DIRECTION OUTPUT ;
    USE SIGNAL ;
    PORT
      LAYER M3 ;
        RECT  33.48 0 33.498 0.038 ;
    END
  END o[403]
  PIN o[404]
    DIRECTION OUTPUT ;
    USE SIGNAL ;
    PORT
      LAYER M5 ;
        RECT  33.6 0 33.624 0.192 ;
    END
  END o[404]
  PIN o[405]
    DIRECTION OUTPUT ;
    USE SIGNAL ;
    PORT
      LAYER M3 ;
        RECT  33.624 0 33.642 0.038 ;
    END
  END o[405]
  PIN o[406]
    DIRECTION OUTPUT ;
    USE SIGNAL ;
    PORT
      LAYER M5 ;
        RECT  33.696 0 33.72 0.192 ;
    END
  END o[406]
  PIN o[407]
    DIRECTION OUTPUT ;
    USE SIGNAL ;
    PORT
      LAYER M3 ;
        RECT  33.768 0 33.786 0.038 ;
    END
  END o[407]
  PIN o[408]
    DIRECTION OUTPUT ;
    USE SIGNAL ;
    PORT
      LAYER M5 ;
        RECT  33.888 0 33.912 0.192 ;
    END
  END o[408]
  PIN o[409]
    DIRECTION OUTPUT ;
    USE SIGNAL ;
    PORT
      LAYER M3 ;
        RECT  33.912 0 33.93 0.038 ;
    END
  END o[409]
  PIN o[40]
    DIRECTION OUTPUT ;
    USE SIGNAL ;
    PORT
      LAYER M5 ;
        RECT  6.144 0 6.168 0.192 ;
    END
  END o[40]
  PIN o[410]
    DIRECTION OUTPUT ;
    USE SIGNAL ;
    PORT
      LAYER M5 ;
        RECT  33.984 0 34.008 0.192 ;
    END
  END o[410]
  PIN o[411]
    DIRECTION OUTPUT ;
    USE SIGNAL ;
    PORT
      LAYER M3 ;
        RECT  34.128 0 34.146 0.038 ;
    END
  END o[411]
  PIN o[412]
    DIRECTION OUTPUT ;
    USE SIGNAL ;
    PORT
      LAYER M5 ;
        RECT  34.176 0 34.2 0.192 ;
    END
  END o[412]
  PIN o[413]
    DIRECTION OUTPUT ;
    USE SIGNAL ;
    PORT
      LAYER M3 ;
        RECT  34.272 0 34.29 0.038 ;
    END
  END o[413]
  PIN o[414]
    DIRECTION OUTPUT ;
    USE SIGNAL ;
    PORT
      LAYER M5 ;
        RECT  34.368 0 34.392 0.192 ;
    END
  END o[414]
  PIN o[415]
    DIRECTION OUTPUT ;
    USE SIGNAL ;
    PORT
      LAYER M3 ;
        RECT  34.488 0 34.506 0.038 ;
    END
  END o[415]
  PIN o[416]
    DIRECTION OUTPUT ;
    USE SIGNAL ;
    PORT
      LAYER M5 ;
        RECT  34.56 0 34.584 0.192 ;
    END
  END o[416]
  PIN o[417]
    DIRECTION OUTPUT ;
    USE SIGNAL ;
    PORT
      LAYER M3 ;
        RECT  34.632 0 34.65 0.038 ;
    END
  END o[417]
  PIN o[418]
    DIRECTION OUTPUT ;
    USE SIGNAL ;
    PORT
      LAYER M5 ;
        RECT  34.752 0 34.776 0.192 ;
    END
  END o[418]
  PIN o[419]
    DIRECTION OUTPUT ;
    USE SIGNAL ;
    PORT
      LAYER M3 ;
        RECT  34.776 0 34.794 0.038 ;
    END
  END o[419]
  PIN o[41]
    DIRECTION OUTPUT ;
    USE SIGNAL ;
    PORT
      LAYER M3 ;
        RECT  6.192 0 6.21 0.038 ;
    END
  END o[41]
  PIN o[420]
    DIRECTION OUTPUT ;
    USE SIGNAL ;
    PORT
      LAYER M5 ;
        RECT  34.848 0 34.872 0.192 ;
    END
  END o[420]
  PIN o[421]
    DIRECTION OUTPUT ;
    USE SIGNAL ;
    PORT
      LAYER M3 ;
        RECT  34.992 0 35.01 0.038 ;
    END
  END o[421]
  PIN o[422]
    DIRECTION OUTPUT ;
    USE SIGNAL ;
    PORT
      LAYER M5 ;
        RECT  35.04 0 35.064 0.192 ;
    END
  END o[422]
  PIN o[423]
    DIRECTION OUTPUT ;
    USE SIGNAL ;
    PORT
      LAYER M3 ;
        RECT  35.136 0 35.154 0.038 ;
    END
  END o[423]
  PIN o[424]
    DIRECTION OUTPUT ;
    USE SIGNAL ;
    PORT
      LAYER M5 ;
        RECT  35.232 0 35.256 0.192 ;
    END
  END o[424]
  PIN o[425]
    DIRECTION OUTPUT ;
    USE SIGNAL ;
    PORT
      LAYER M3 ;
        RECT  35.352 0 35.37 0.038 ;
    END
  END o[425]
  PIN o[426]
    DIRECTION OUTPUT ;
    USE SIGNAL ;
    PORT
      LAYER M5 ;
        RECT  35.424 0 35.448 0.192 ;
    END
  END o[426]
  PIN o[427]
    DIRECTION OUTPUT ;
    USE SIGNAL ;
    PORT
      LAYER M3 ;
        RECT  35.496 0 35.514 0.038 ;
    END
  END o[427]
  PIN o[428]
    DIRECTION OUTPUT ;
    USE SIGNAL ;
    PORT
      LAYER M3 ;
        RECT  39.672 0 39.69 0.038 ;
    END
  END o[428]
  PIN o[429]
    DIRECTION OUTPUT ;
    USE SIGNAL ;
    PORT
      LAYER M5 ;
        RECT  39.792 0 39.816 0.192 ;
    END
  END o[429]
  PIN o[42]
    DIRECTION OUTPUT ;
    USE SIGNAL ;
    PORT
      LAYER M5 ;
        RECT  6.24 0 6.264 0.192 ;
    END
  END o[42]
  PIN o[430]
    DIRECTION OUTPUT ;
    USE SIGNAL ;
    PORT
      LAYER M3 ;
        RECT  39.888 0 39.906 0.038 ;
    END
  END o[430]
  PIN o[431]
    DIRECTION OUTPUT ;
    USE SIGNAL ;
    PORT
      LAYER M5 ;
        RECT  39.984 0 40.008 0.192 ;
    END
  END o[431]
  PIN o[432]
    DIRECTION OUTPUT ;
    USE SIGNAL ;
    PORT
      LAYER M3 ;
        RECT  40.032 0 40.05 0.038 ;
    END
  END o[432]
  PIN o[433]
    DIRECTION OUTPUT ;
    USE SIGNAL ;
    PORT
      LAYER M5 ;
        RECT  40.08 0 40.104 0.192 ;
    END
  END o[433]
  PIN o[434]
    DIRECTION OUTPUT ;
    USE SIGNAL ;
    PORT
      LAYER M3 ;
        RECT  40.176 0 40.194 0.038 ;
    END
  END o[434]
  PIN o[435]
    DIRECTION OUTPUT ;
    USE SIGNAL ;
    PORT
      LAYER M5 ;
        RECT  40.272 0 40.296 0.192 ;
    END
  END o[435]
  PIN o[436]
    DIRECTION OUTPUT ;
    USE SIGNAL ;
    PORT
      LAYER M3 ;
        RECT  40.392 0 40.41 0.038 ;
    END
  END o[436]
  PIN o[437]
    DIRECTION OUTPUT ;
    USE SIGNAL ;
    PORT
      LAYER M5 ;
        RECT  40.464 0 40.488 0.192 ;
    END
  END o[437]
  PIN o[438]
    DIRECTION OUTPUT ;
    USE SIGNAL ;
    PORT
      LAYER M3 ;
        RECT  40.536 0 40.554 0.038 ;
    END
  END o[438]
  PIN o[439]
    DIRECTION OUTPUT ;
    USE SIGNAL ;
    PORT
      LAYER M5 ;
        RECT  40.656 0 40.68 0.192 ;
    END
  END o[439]
  PIN o[43]
    DIRECTION OUTPUT ;
    USE SIGNAL ;
    PORT
      LAYER M3 ;
        RECT  6.264 0 6.282 0.038 ;
    END
  END o[43]
  PIN o[440]
    DIRECTION OUTPUT ;
    USE SIGNAL ;
    PORT
      LAYER M3 ;
        RECT  40.752 0 40.77 0.038 ;
    END
  END o[440]
  PIN o[441]
    DIRECTION OUTPUT ;
    USE SIGNAL ;
    PORT
      LAYER M5 ;
        RECT  40.848 0 40.872 0.192 ;
    END
  END o[441]
  PIN o[442]
    DIRECTION OUTPUT ;
    USE SIGNAL ;
    PORT
      LAYER M3 ;
        RECT  40.896 0 40.914 0.038 ;
    END
  END o[442]
  PIN o[44]
    DIRECTION OUTPUT ;
    USE SIGNAL ;
    PORT
      LAYER M5 ;
        RECT  6.336 0 6.36 0.192 ;
    END
  END o[44]
  PIN o[45]
    DIRECTION OUTPUT ;
    USE SIGNAL ;
    PORT
      LAYER M3 ;
        RECT  6.336 0 6.354 0.038 ;
    END
  END o[45]
  PIN o[46]
    DIRECTION OUTPUT ;
    USE SIGNAL ;
    PORT
      LAYER M5 ;
        RECT  6.432 0 6.456 0.192 ;
    END
  END o[46]
  PIN o[47]
    DIRECTION OUTPUT ;
    USE SIGNAL ;
    PORT
      LAYER M3 ;
        RECT  6.408 0 6.426 0.038 ;
    END
  END o[47]
  PIN o[48]
    DIRECTION OUTPUT ;
    USE SIGNAL ;
    PORT
      LAYER M5 ;
        RECT  6.528 0 6.552 0.192 ;
    END
  END o[48]
  PIN o[49]
    DIRECTION OUTPUT ;
    USE SIGNAL ;
    PORT
      LAYER M3 ;
        RECT  6.48 0 6.498 0.038 ;
    END
  END o[49]
  PIN o[4]
    DIRECTION OUTPUT ;
    USE SIGNAL ;
    PORT
      LAYER M5 ;
        RECT  2.544 0 2.568 0.192 ;
    END
  END o[4]
  PIN o[50]
    DIRECTION OUTPUT ;
    USE SIGNAL ;
    PORT
      LAYER M5 ;
        RECT  6.624 0 6.648 0.192 ;
    END
  END o[50]
  PIN o[51]
    DIRECTION OUTPUT ;
    USE SIGNAL ;
    PORT
      LAYER M3 ;
        RECT  6.624 0 6.642 0.038 ;
    END
  END o[51]
  PIN o[52]
    DIRECTION OUTPUT ;
    USE SIGNAL ;
    PORT
      LAYER M5 ;
        RECT  6.72 0 6.744 0.192 ;
    END
  END o[52]
  PIN o[53]
    DIRECTION OUTPUT ;
    USE SIGNAL ;
    PORT
      LAYER M3 ;
        RECT  6.84 0 6.858 0.038 ;
    END
  END o[53]
  PIN o[54]
    DIRECTION OUTPUT ;
    USE SIGNAL ;
    PORT
      LAYER M5 ;
        RECT  6.912 0 6.936 0.192 ;
    END
  END o[54]
  PIN o[55]
    DIRECTION OUTPUT ;
    USE SIGNAL ;
    PORT
      LAYER M3 ;
        RECT  6.984 0 7.002 0.038 ;
    END
  END o[55]
  PIN o[56]
    DIRECTION OUTPUT ;
    USE SIGNAL ;
    PORT
      LAYER M5 ;
        RECT  7.104 0 7.128 0.192 ;
    END
  END o[56]
  PIN o[57]
    DIRECTION OUTPUT ;
    USE SIGNAL ;
    PORT
      LAYER M3 ;
        RECT  7.128 0 7.146 0.038 ;
    END
  END o[57]
  PIN o[58]
    DIRECTION OUTPUT ;
    USE SIGNAL ;
    PORT
      LAYER M5 ;
        RECT  7.2 0 7.224 0.192 ;
    END
  END o[58]
  PIN o[59]
    DIRECTION OUTPUT ;
    USE SIGNAL ;
    PORT
      LAYER M3 ;
        RECT  7.344 0 7.362 0.038 ;
    END
  END o[59]
  PIN o[5]
    DIRECTION OUTPUT ;
    USE SIGNAL ;
    PORT
      LAYER M3 ;
        RECT  2.664 0 2.682 0.038 ;
    END
  END o[5]
  PIN o[60]
    DIRECTION OUTPUT ;
    USE SIGNAL ;
    PORT
      LAYER M5 ;
        RECT  7.392 0 7.416 0.192 ;
    END
  END o[60]
  PIN o[61]
    DIRECTION OUTPUT ;
    USE SIGNAL ;
    PORT
      LAYER M3 ;
        RECT  7.488 0 7.506 0.038 ;
    END
  END o[61]
  PIN o[62]
    DIRECTION OUTPUT ;
    USE SIGNAL ;
    PORT
      LAYER M5 ;
        RECT  7.584 0 7.608 0.192 ;
    END
  END o[62]
  PIN o[63]
    DIRECTION OUTPUT ;
    USE SIGNAL ;
    PORT
      LAYER M3 ;
        RECT  7.704 0 7.722 0.038 ;
    END
  END o[63]
  PIN o[64]
    DIRECTION OUTPUT ;
    USE SIGNAL ;
    PORT
      LAYER M5 ;
        RECT  7.776 0 7.8 0.192 ;
    END
  END o[64]
  PIN o[65]
    DIRECTION OUTPUT ;
    USE SIGNAL ;
    PORT
      LAYER M3 ;
        RECT  7.848 0 7.866 0.038 ;
    END
  END o[65]
  PIN o[66]
    DIRECTION OUTPUT ;
    USE SIGNAL ;
    PORT
      LAYER M5 ;
        RECT  7.968 0 7.992 0.192 ;
    END
  END o[66]
  PIN o[67]
    DIRECTION OUTPUT ;
    USE SIGNAL ;
    PORT
      LAYER M3 ;
        RECT  7.992 0 8.01 0.038 ;
    END
  END o[67]
  PIN o[68]
    DIRECTION OUTPUT ;
    USE SIGNAL ;
    PORT
      LAYER M5 ;
        RECT  8.064 0 8.088 0.192 ;
    END
  END o[68]
  PIN o[69]
    DIRECTION OUTPUT ;
    USE SIGNAL ;
    PORT
      LAYER M3 ;
        RECT  8.208 0 8.226 0.038 ;
    END
  END o[69]
  PIN o[6]
    DIRECTION OUTPUT ;
    USE SIGNAL ;
    PORT
      LAYER M5 ;
        RECT  2.736 0 2.76 0.192 ;
    END
  END o[6]
  PIN o[70]
    DIRECTION OUTPUT ;
    USE SIGNAL ;
    PORT
      LAYER M5 ;
        RECT  8.256 0 8.28 0.192 ;
    END
  END o[70]
  PIN o[71]
    DIRECTION OUTPUT ;
    USE SIGNAL ;
    PORT
      LAYER M3 ;
        RECT  8.352 0 8.37 0.038 ;
    END
  END o[71]
  PIN o[72]
    DIRECTION OUTPUT ;
    USE SIGNAL ;
    PORT
      LAYER M5 ;
        RECT  8.448 0 8.472 0.192 ;
    END
  END o[72]
  PIN o[73]
    DIRECTION OUTPUT ;
    USE SIGNAL ;
    PORT
      LAYER M3 ;
        RECT  8.568 0 8.586 0.038 ;
    END
  END o[73]
  PIN o[74]
    DIRECTION OUTPUT ;
    USE SIGNAL ;
    PORT
      LAYER M5 ;
        RECT  8.64 0 8.664 0.192 ;
    END
  END o[74]
  PIN o[75]
    DIRECTION OUTPUT ;
    USE SIGNAL ;
    PORT
      LAYER M3 ;
        RECT  8.712 0 8.73 0.038 ;
    END
  END o[75]
  PIN o[76]
    DIRECTION OUTPUT ;
    USE SIGNAL ;
    PORT
      LAYER M5 ;
        RECT  8.832 0 8.856 0.192 ;
    END
  END o[76]
  PIN o[77]
    DIRECTION OUTPUT ;
    USE SIGNAL ;
    PORT
      LAYER M3 ;
        RECT  8.856 0 8.874 0.038 ;
    END
  END o[77]
  PIN o[78]
    DIRECTION OUTPUT ;
    USE SIGNAL ;
    PORT
      LAYER M5 ;
        RECT  8.928 0 8.952 0.192 ;
    END
  END o[78]
  PIN o[79]
    DIRECTION OUTPUT ;
    USE SIGNAL ;
    PORT
      LAYER M3 ;
        RECT  9.072 0 9.09 0.038 ;
    END
  END o[79]
  PIN o[7]
    DIRECTION OUTPUT ;
    USE SIGNAL ;
    PORT
      LAYER M3 ;
        RECT  2.808 0 2.826 0.038 ;
    END
  END o[7]
  PIN o[80]
    DIRECTION OUTPUT ;
    USE SIGNAL ;
    PORT
      LAYER M5 ;
        RECT  9.12 0 9.144 0.192 ;
    END
  END o[80]
  PIN o[81]
    DIRECTION OUTPUT ;
    USE SIGNAL ;
    PORT
      LAYER M3 ;
        RECT  9.216 0 9.234 0.038 ;
    END
  END o[81]
  PIN o[82]
    DIRECTION OUTPUT ;
    USE SIGNAL ;
    PORT
      LAYER M5 ;
        RECT  9.312 0 9.336 0.192 ;
    END
  END o[82]
  PIN o[83]
    DIRECTION OUTPUT ;
    USE SIGNAL ;
    PORT
      LAYER M3 ;
        RECT  9.432 0 9.45 0.038 ;
    END
  END o[83]
  PIN o[84]
    DIRECTION OUTPUT ;
    USE SIGNAL ;
    PORT
      LAYER M5 ;
        RECT  9.504 0 9.528 0.192 ;
    END
  END o[84]
  PIN o[85]
    DIRECTION OUTPUT ;
    USE SIGNAL ;
    PORT
      LAYER M3 ;
        RECT  9.576 0 9.594 0.038 ;
    END
  END o[85]
  PIN o[86]
    DIRECTION OUTPUT ;
    USE SIGNAL ;
    PORT
      LAYER M5 ;
        RECT  9.696 0 9.72 0.192 ;
    END
  END o[86]
  PIN o[87]
    DIRECTION OUTPUT ;
    USE SIGNAL ;
    PORT
      LAYER M3 ;
        RECT  9.792 0 9.81 0.038 ;
    END
  END o[87]
  PIN o[88]
    DIRECTION OUTPUT ;
    USE SIGNAL ;
    PORT
      LAYER M5 ;
        RECT  9.888 0 9.912 0.192 ;
    END
  END o[88]
  PIN o[89]
    DIRECTION OUTPUT ;
    USE SIGNAL ;
    PORT
      LAYER M3 ;
        RECT  9.936 0 9.954 0.038 ;
    END
  END o[89]
  PIN o[8]
    DIRECTION OUTPUT ;
    USE SIGNAL ;
    PORT
      LAYER M5 ;
        RECT  2.928 0 2.952 0.192 ;
    END
  END o[8]
  PIN o[90]
    DIRECTION OUTPUT ;
    USE SIGNAL ;
    PORT
      LAYER M5 ;
        RECT  9.984 0 10.008 0.192 ;
    END
  END o[90]
  PIN o[91]
    DIRECTION OUTPUT ;
    USE SIGNAL ;
    PORT
      LAYER M3 ;
        RECT  10.08 0 10.098 0.038 ;
    END
  END o[91]
  PIN o[92]
    DIRECTION OUTPUT ;
    USE SIGNAL ;
    PORT
      LAYER M5 ;
        RECT  10.176 0 10.2 0.192 ;
    END
  END o[92]
  PIN o[93]
    DIRECTION OUTPUT ;
    USE SIGNAL ;
    PORT
      LAYER M3 ;
        RECT  10.296 0 10.314 0.038 ;
    END
  END o[93]
  PIN o[94]
    DIRECTION OUTPUT ;
    USE SIGNAL ;
    PORT
      LAYER M5 ;
        RECT  10.368 0 10.392 0.192 ;
    END
  END o[94]
  PIN o[95]
    DIRECTION OUTPUT ;
    USE SIGNAL ;
    PORT
      LAYER M3 ;
        RECT  10.44 0 10.458 0.038 ;
    END
  END o[95]
  PIN o[96]
    DIRECTION OUTPUT ;
    USE SIGNAL ;
    PORT
      LAYER M5 ;
        RECT  10.56 0 10.584 0.192 ;
    END
  END o[96]
  PIN o[97]
    DIRECTION OUTPUT ;
    USE SIGNAL ;
    PORT
      LAYER M3 ;
        RECT  10.656 0 10.674 0.038 ;
    END
  END o[97]
  PIN o[98]
    DIRECTION OUTPUT ;
    USE SIGNAL ;
    PORT
      LAYER M5 ;
        RECT  10.752 0 10.776 0.192 ;
    END
  END o[98]
  PIN o[99]
    DIRECTION OUTPUT ;
    USE SIGNAL ;
    PORT
      LAYER M3 ;
        RECT  10.8 0 10.818 0.038 ;
    END
  END o[99]
  PIN o[9]
    DIRECTION OUTPUT ;
    USE SIGNAL ;
    PORT
      LAYER M3 ;
        RECT  2.952 0 2.97 0.038 ;
    END
  END o[9]
  PIN o_v[0]
    DIRECTION OUTPUT ;
    USE SIGNAL ;
    PORT
      LAYER M3 ;
        RECT  36.864 0 36.882 0.038 ;
    END
  END o_v[0]
  PIN o_v[1]
    DIRECTION OUTPUT ;
    USE SIGNAL ;
    PORT
      LAYER M5 ;
        RECT  38.544 0 38.568 0.192 ;
    END
  END o_v[1]
  PIN o_v[2]
    DIRECTION OUTPUT ;
    USE SIGNAL ;
    PORT
      LAYER M5 ;
        RECT  39.6 0 39.624 0.192 ;
    END
  END o_v[2]
  PIN o_v[3]
    DIRECTION OUTPUT ;
    USE SIGNAL ;
    PORT
      LAYER M5 ;
        RECT  40.944 0 40.968 0.192 ;
    END
  END o_v[3]
  PIN rn_o[0]
    DIRECTION OUTPUT ;
    USE SIGNAL ;
    PORT
      LAYER M4 ;
        RECT  43.008 7.536 43.2 7.56 ;
    END
    PORT
      LAYER M4 ;
        RECT  42.145 7.536 43.02 7.56 ;
    END
  END rn_o[0]
  PIN rn_o[1]
    DIRECTION OUTPUT ;
    USE SIGNAL ;
    PORT
      LAYER M4 ;
        RECT  43.008 18.384 43.2 18.408 ;
    END
    PORT
      LAYER M4 ;
        RECT  42.973 18.384 43.02 18.408 ;
    END
  END rn_o[1]
  PIN rni
    DIRECTION INPUT ;
    USE SIGNAL ;
    PORT
      LAYER M4 ;
        RECT  0 18.384 0.192 18.408 ;
    END
    PORT
      LAYER M4 ;
        RECT  0.156 18.384 2.408 18.408 ;
    END
  END rni
  PIN VDD
    DIRECTION INOUT ;
    USE POWER ;
    PORT
      LAYER M5 ;
        RECT  40.392 2.151 40.512 23.769 ;
        RECT  34.992 2.151 35.112 23.769 ;
        RECT  29.592 2.151 29.712 23.769 ;
        RECT  24.192 2.151 24.312 23.769 ;
        RECT  18.792 2.151 18.912 23.769 ;
        RECT  13.392 2.151 13.512 23.769 ;
        RECT  7.992 2.151 8.112 23.769 ;
        RECT  2.592 2.151 2.712 23.769 ;
    END
  END VDD
  PIN VSS
    DIRECTION INOUT ;
    USE GROUND ;
    PORT
      LAYER M5 ;
        RECT  40.2 2.137 40.32 23.783 ;
        RECT  34.8 2.137 34.92 23.783 ;
        RECT  29.4 2.137 29.52 23.783 ;
        RECT  24 2.137 24.12 23.783 ;
        RECT  18.6 2.137 18.72 23.783 ;
        RECT  13.2 2.137 13.32 23.783 ;
        RECT  7.8 2.137 7.92 23.783 ;
        RECT  2.4 2.137 2.52 23.783 ;
    END
  END VSS
  # OT_OBS_CLOSED layer=M5 d_um=1.536 added=105
  OBS
    LAYER RVTN ;
     RECT  2.16 2.16 41.04 2.295 ;
     RECT  2.16 2.565 41.04 2.835 ;
     RECT  2.16 3.105 41.04 3.375 ;
     RECT  2.16 3.645 41.04 3.915 ;
     RECT  2.16 4.185 41.04 4.455 ;
     RECT  2.16 4.725 41.04 4.995 ;
     RECT  2.16 5.265 41.04 5.535 ;
     RECT  2.16 5.805 41.04 6.075 ;
     RECT  2.16 6.345 41.04 6.615 ;
     RECT  2.16 6.885 41.04 7.155 ;
     RECT  2.16 7.425 41.04 7.695 ;
     RECT  2.16 7.965 41.04 8.235 ;
     RECT  2.16 8.505 41.04 8.775 ;
     RECT  2.16 9.045 41.04 9.315 ;
     RECT  2.16 9.585 41.04 9.855 ;
     RECT  2.16 10.125 41.04 10.395 ;
     RECT  2.16 10.665 41.04 10.935 ;
     RECT  2.16 11.205 41.04 11.475 ;
     RECT  2.16 11.745 41.04 12.015 ;
     RECT  2.16 12.285 41.04 12.555 ;
     RECT  2.16 12.825 41.04 13.095 ;
     RECT  2.16 13.365 41.04 13.635 ;
     RECT  2.16 13.905 41.04 14.175 ;
     RECT  2.16 14.445 41.04 14.715 ;
     RECT  2.16 14.985 41.04 15.255 ;
     RECT  2.16 15.525 41.04 15.795 ;
     RECT  2.16 16.065 41.04 16.335 ;
     RECT  2.16 16.605 41.04 16.875 ;
     RECT  2.16 17.145 41.04 17.415 ;
     RECT  2.16 17.685 41.04 17.955 ;
     RECT  2.16 18.225 41.04 18.495 ;
     RECT  2.16 18.765 41.04 19.035 ;
     RECT  2.16 19.305 41.04 19.575 ;
     RECT  2.16 19.845 41.04 20.115 ;
     RECT  2.16 20.385 41.04 20.655 ;
     RECT  2.16 20.925 41.04 21.195 ;
     RECT  2.16 21.465 41.04 21.735 ;
     RECT  2.16 22.005 41.04 22.275 ;
     RECT  2.16 22.545 41.04 22.815 ;
     RECT  2.16 23.085 41.04 23.355 ;
     RECT  2.16 23.625 41.04 23.76 ;
    LAYER RVTP ;
     RECT  2.16 2.295 41.04 2.565 ;
     RECT  2.16 2.835 41.04 3.105 ;
     RECT  2.16 3.375 41.04 3.645 ;
     RECT  2.16 3.915 41.04 4.185 ;
     RECT  2.16 4.455 41.04 4.725 ;
     RECT  2.16 4.995 41.04 5.265 ;
     RECT  2.16 5.535 41.04 5.805 ;
     RECT  2.16 6.075 41.04 6.345 ;
     RECT  2.16 6.615 41.04 6.885 ;
     RECT  2.16 7.155 41.04 7.425 ;
     RECT  2.16 7.695 41.04 7.965 ;
     RECT  2.16 8.235 41.04 8.505 ;
     RECT  2.16 8.775 41.04 9.045 ;
     RECT  2.16 9.315 41.04 9.585 ;
     RECT  2.16 9.855 41.04 10.125 ;
     RECT  2.16 10.395 41.04 10.665 ;
     RECT  2.16 10.935 41.04 11.205 ;
     RECT  2.16 11.475 41.04 11.745 ;
     RECT  2.16 12.015 41.04 12.285 ;
     RECT  2.16 12.555 41.04 12.825 ;
     RECT  2.16 13.095 41.04 13.365 ;
     RECT  2.16 13.635 41.04 13.905 ;
     RECT  2.16 14.175 41.04 14.445 ;
     RECT  2.16 14.715 41.04 14.985 ;
     RECT  2.16 15.255 41.04 15.525 ;
     RECT  2.16 15.795 41.04 16.065 ;
     RECT  2.16 16.335 41.04 16.605 ;
     RECT  2.16 16.875 41.04 17.145 ;
     RECT  2.16 17.415 41.04 17.685 ;
     RECT  2.16 17.955 41.04 18.225 ;
     RECT  2.16 18.495 41.04 18.765 ;
     RECT  2.16 19.035 41.04 19.305 ;
     RECT  2.16 19.575 41.04 19.845 ;
     RECT  2.16 20.115 41.04 20.385 ;
     RECT  2.16 20.655 41.04 20.925 ;
     RECT  2.16 21.195 41.04 21.465 ;
     RECT  2.16 21.735 41.04 22.005 ;
     RECT  2.16 22.275 41.04 22.545 ;
     RECT  2.16 22.815 41.04 23.085 ;
     RECT  2.16 23.355 41.04 23.625 ;
    LAYER M1 ;
     RECT  2.16 2.151 41.04 23.769 ;
    LAYER M2 ;
     RECT  2.16 2.151 2.443 23.769 ;
     RECT  2.443 0.108 2.731 0.126 ;
     RECT  2.443 2.151 2.731 23.85 ;
     RECT  2.731 0.036 2.831 0.126 ;
     RECT  2.731 2.151 2.831 23.958 ;
     RECT  2.831 0.036 3.667 0.054 ;
     RECT  3.667 0.036 3.811 0.09 ;
     RECT  3.811 0.036 3.947 0.126 ;
     RECT  2.831 2.151 4.171 23.769 ;
     RECT  4.171 1.728 4.559 23.769 ;
     RECT  3.947 0.036 5.395 0.054 ;
     RECT  5.395 0.036 5.459 0.126 ;
     RECT  4.559 2.106 5.539 23.769 ;
     RECT  5.459 0.108 5.675 0.126 ;
     RECT  5.539 1.728 5.711 23.769 ;
     RECT  6.403 0.18 6.475 0.198 ;
     RECT  6.475 0.036 6.647 0.198 ;
     RECT  5.711 2.106 6.755 23.769 ;
     RECT  6.647 0.036 7.447 0.054 ;
     RECT  6.755 2.151 7.627 23.769 ;
     RECT  7.447 0.036 7.699 0.09 ;
     RECT  7.627 2.151 7.771 23.886 ;
     RECT  7.771 1.728 7.871 23.886 ;
     RECT  7.871 2.151 7.979 23.814 ;
     RECT  7.699 0.036 8.195 0.126 ;
     RECT  7.979 2.151 8.851 23.769 ;
     RECT  8.851 2.151 8.987 23.814 ;
     RECT  8.195 0.036 9.283 0.054 ;
     RECT  9.211 24.984 9.355 25.002 ;
     RECT  9.355 24.984 9.455 25.074 ;
     RECT  8.987 2.151 9.499 23.769 ;
     RECT  9.283 0.036 9.527 0.126 ;
     RECT  9.527 0.108 9.599 0.126 ;
     RECT  9.499 2.106 9.787 23.769 ;
     RECT  9.787 2.034 10.535 23.769 ;
     RECT  10.579 1.152 10.679 1.17 ;
     RECT  10.579 0.036 10.823 0.054 ;
     RECT  11.587 24.984 11.623 25.002 ;
     RECT  11.623 24.984 11.831 25.074 ;
     RECT  10.535 2.151 12.379 23.769 ;
     RECT  12.379 1.728 12.451 23.769 ;
     RECT  12.451 1.728 12.551 23.814 ;
     RECT  12.739 1.224 12.955 1.242 ;
     RECT  12.955 1.152 12.983 1.242 ;
     RECT  12.983 1.152 13.091 1.17 ;
     RECT  12.551 2.151 13.099 23.814 ;
     RECT  13.099 2.151 13.271 23.85 ;
     RECT  11.767 0.036 13.559 0.054 ;
     RECT  13.271 2.151 13.603 23.769 ;
     RECT  13.963 1.152 14.099 1.17 ;
     RECT  13.603 2.106 14.251 23.769 ;
     RECT  14.251 25.056 14.603 25.074 ;
     RECT  14.251 1.728 14.863 23.769 ;
     RECT  14.863 1.224 14.899 23.769 ;
     RECT  14.899 1.152 14.999 23.769 ;
     RECT  15.475 25.056 15.683 25.074 ;
     RECT  14.999 1.728 16.195 23.769 ;
     RECT  16.195 1.152 16.367 23.769 ;
     RECT  16.267 25.866 16.367 25.884 ;
     RECT  16.367 1.152 17.087 1.17 ;
     RECT  16.367 2.151 17.275 23.769 ;
     RECT  14.971 0.036 17.347 0.054 ;
     RECT  17.347 0.036 17.663 0.198 ;
     RECT  17.275 1.728 17.663 23.769 ;
     RECT  17.663 2.151 18.355 23.769 ;
     RECT  18.355 2.151 18.643 23.85 ;
     RECT  18.643 1.728 18.779 23.85 ;
     RECT  18.779 2.106 18.851 23.85 ;
     RECT  18.851 2.151 19.183 23.85 ;
     RECT  19.183 2.151 19.319 23.958 ;
     RECT  17.663 0.036 19.787 0.126 ;
     RECT  19.787 0.036 20.327 0.054 ;
     RECT  19.319 2.151 21.091 23.769 ;
     RECT  21.091 1.728 21.515 23.769 ;
     RECT  21.235 0.036 21.623 0.054 ;
     RECT  21.667 25.056 21.767 25.074 ;
     RECT  22.387 0.18 22.531 0.198 ;
     RECT  22.531 0.108 22.595 0.198 ;
     RECT  22.595 0.108 22.603 0.126 ;
     RECT  21.515 2.106 22.603 23.769 ;
     RECT  22.603 0.036 22.631 0.126 ;
     RECT  22.603 2.106 22.675 23.994 ;
     RECT  22.675 1.728 22.703 23.994 ;
     RECT  22.703 1.728 22.775 23.769 ;
     RECT  22.819 25.866 22.919 25.884 ;
     RECT  22.675 25.056 23.495 25.074 ;
     RECT  22.631 0.036 23.827 0.054 ;
     RECT  23.827 0.036 23.927 0.126 ;
     RECT  22.775 2.034 23.971 23.769 ;
     RECT  23.971 2.034 24.071 23.922 ;
     RECT  24.071 2.034 24.187 23.769 ;
     RECT  24.187 1.728 24.467 23.769 ;
     RECT  24.467 2.151 25.771 23.769 ;
     RECT  23.927 0.036 26.159 0.054 ;
     RECT  25.771 1.728 26.159 23.769 ;
     RECT  26.159 2.106 26.843 23.769 ;
     RECT  26.923 0.036 27.023 0.054 ;
     RECT  27.751 0.036 27.787 0.054 ;
     RECT  27.787 0.036 27.887 0.126 ;
     RECT  26.843 2.151 28.075 23.769 ;
     RECT  28.075 1.728 28.319 23.769 ;
     RECT  28.219 25.101 28.355 25.119 ;
     RECT  27.887 0.108 28.723 0.126 ;
     RECT  28.723 0.036 28.751 0.126 ;
     RECT  28.319 2.106 29.003 23.769 ;
     RECT  29.003 2.151 29.299 23.769 ;
     RECT  29.299 2.151 29.471 23.85 ;
     RECT  29.471 2.151 29.731 23.769 ;
     RECT  29.731 1.728 29.911 23.769 ;
     RECT  29.911 1.152 29.975 23.769 ;
     RECT  28.751 0.036 30.155 0.054 ;
     RECT  29.975 1.152 30.155 1.242 ;
     RECT  30.739 25.182 30.839 25.2 ;
     RECT  31.099 0.036 31.207 0.054 ;
     RECT  30.155 1.152 31.235 1.17 ;
     RECT  29.975 2.151 31.891 23.769 ;
     RECT  31.207 0.036 31.919 0.126 ;
     RECT  31.891 2.106 32.035 23.769 ;
     RECT  31.919 0.036 32.423 0.054 ;
     RECT  32.035 1.728 32.719 23.769 ;
     RECT  32.719 1.152 32.819 23.769 ;
     RECT  32.819 1.728 32.927 23.769 ;
     RECT  32.927 2.151 33.079 23.769 ;
     RECT  33.259 0.108 33.331 0.126 ;
     RECT  33.331 0.036 33.359 0.126 ;
     RECT  33.079 2.151 33.503 23.994 ;
     RECT  33.619 25.056 34.043 25.074 ;
     RECT  33.359 0.036 34.483 0.09 ;
     RECT  34.483 0.036 34.555 0.126 ;
     RECT  33.503 2.151 35.131 23.769 ;
     RECT  34.555 0.036 35.339 0.162 ;
     RECT  35.339 0.036 35.375 0.126 ;
     RECT  35.131 2.106 35.411 23.769 ;
     RECT  35.375 0.036 36.095 0.054 ;
     RECT  35.411 2.151 36.211 23.769 ;
     RECT  36.139 24.561 36.239 24.579 ;
     RECT  36.211 1.728 36.455 23.769 ;
     RECT  36.715 0.108 36.859 0.126 ;
     RECT  36.859 0.036 36.887 0.126 ;
     RECT  36.455 2.151 37.507 23.769 ;
     RECT  36.887 0.036 37.535 0.054 ;
     RECT  38.515 0.036 38.551 0.054 ;
     RECT  38.551 0.036 38.615 0.09 ;
     RECT  38.615 0.072 38.659 0.09 ;
     RECT  37.507 2.106 38.687 23.769 ;
     RECT  38.551 25.056 38.687 25.074 ;
     RECT  38.659 0.072 38.759 0.198 ;
     RECT  39.595 0.036 39.695 0.054 ;
     RECT  38.687 2.151 39.739 23.769 ;
     RECT  39.991 25.866 40.199 25.884 ;
     RECT  39.739 2.034 40.747 23.769 ;
     RECT  40.747 1.728 41.04 23.769 ;
     RECT  41.04 1.728 41.099 1.746 ;
     RECT  41.04 4.896 41.099 4.914 ;
     RECT  41.04 8.946 42.179 8.964 ;
     RECT  41.04 19.746 43.007 19.764 ;
    LAYER M3 ;
     RECT  2.304 0.012 40.914 0.187 ;
     RECT  2.304 0.187 40.95 1.723 ;
     RECT  2.304 1.723 41.094 2.219 ;
     RECT  2.34 2.219 41.094 3.979 ;
     RECT  2.196 3.979 41.094 4.919 ;
     RECT  2.196 4.919 41.022 5.099 ;
     RECT  2.196 5.099 40.986 5.189 ;
     RECT  2.34 5.189 40.986 5.999 ;
     RECT  2.376 5.999 40.986 7.195 ;
     RECT  42.156 7.531 42.174 8.969 ;
     RECT  2.376 7.195 41.022 11.273 ;
     RECT  2.415 11.273 41.022 11.939 ;
     RECT  2.415 11.939 40.986 13.559 ;
     RECT  2.415 13.559 40.95 14.521 ;
     RECT  2.415 14.521 40.986 16.645 ;
     RECT  2.415 16.645 41.022 18.379 ;
     RECT  42.984 18.379 43.002 19.769 ;
     RECT  2.304 18.379 41.022 20.587 ;
     RECT  2.268 20.587 41.022 20.651 ;
     RECT  2.268 20.651 40.986 22.739 ;
     RECT  2.304 22.739 40.986 23.081 ;
     RECT  2.304 23.081 40.914 25.901 ;
    LAYER M4 ;
     RECT  2.149 23.376 2.285 23.4 ;
     RECT  2.257 20.592 2.293 20.616 ;
     RECT  2.285 23.376 2.3 23.688 ;
     RECT  2.293 20.592 2.329 21.528 ;
     RECT  2.3 2.016 2.408 2.04 ;
     RECT  2.141 3.984 2.408 4.008 ;
     RECT  0.229 12.816 2.408 12.84 ;
     RECT  2.329 20.064 2.408 21.528 ;
     RECT  2.3 23.376 2.408 23.928 ;
     RECT  2.408 2.016 2.62 23.928 ;
     RECT  2.62 2.016 2.704 23.88 ;
     RECT  2.533 0.288 2.725 0.312 ;
     RECT  2.704 20.064 2.798 20.616 ;
     RECT  2.704 22.08 2.812 23.88 ;
     RECT  2.725 0.192 2.819 0.312 ;
     RECT  2.704 2.832 2.819 5.784 ;
     RECT  2.798 20.064 2.819 20.568 ;
     RECT  2.812 22.08 2.845 23.784 ;
     RECT  2.704 17.088 3.413 18.792 ;
     RECT  3.413 17.088 3.443 18.024 ;
     RECT  2.819 2.832 3.529 5.352 ;
     RECT  2.819 0.192 3.557 0.216 ;
     RECT  2.704 7.392 3.565 8.76 ;
     RECT  3.205 1.728 3.733 1.848 ;
     RECT  3.529 2.832 3.733 3.768 ;
     RECT  2.845 22.08 3.881 23.736 ;
     RECT  3.733 1.728 3.953 3.768 ;
     RECT  2.704 11.376 3.973 13.704 ;
     RECT  2.704 14.784 3.973 15.432 ;
     RECT  2.819 20.544 3.973 20.568 ;
     RECT  2.704 10.224 4.025 10.248 ;
     RECT  3.973 11.376 4.025 15.432 ;
     RECT  4.025 12.816 4.061 15.432 ;
     RECT  3.881 22.176 4.061 23.736 ;
     RECT  4.061 14.784 4.067 15.432 ;
     RECT  4.061 23.376 4.115 23.736 ;
     RECT  4.067 15.408 4.125 15.432 ;
     RECT  3.529 4.8 4.345 5.352 ;
     RECT  3.443 17.616 4.385 18.024 ;
     RECT  3.953 1.728 4.412 1.8 ;
     RECT  4.412 1.104 4.499 1.8 ;
     RECT  3.973 19.968 4.517 20.568 ;
     RECT  4.517 19.344 4.565 20.568 ;
     RECT  3.953 2.88 4.601 3.768 ;
     RECT  3.565 8.496 4.601 8.76 ;
     RECT  4.565 19.344 4.601 19.368 ;
     RECT  4.273 25.104 4.691 25.128 ;
     RECT  4.345 4.8 4.741 5.688 ;
     RECT  4.549 18.192 4.745 18.216 ;
     RECT  4.601 3.408 4.781 3.768 ;
     RECT  4.741 4.8 4.787 6.312 ;
     RECT  4.769 25.68 4.852 25.8 ;
     RECT  4.061 22.176 4.861 22.2 ;
     RECT  4.787 6.288 4.925 6.312 ;
     RECT  4.499 1.728 4.933 1.8 ;
     RECT  3.565 7.392 4.957 7.416 ;
     RECT  4.885 21.648 4.969 21.672 ;
     RECT  4.852 25.68 5.075 25.848 ;
     RECT  4.957 6.864 5.141 7.416 ;
     RECT  4.115 23.376 5.173 23.448 ;
     RECT  5.173 23.376 5.317 23.496 ;
     RECT  5.317 23.376 5.389 23.736 ;
     RECT  5.141 7.248 5.425 7.416 ;
     RECT  4.601 8.496 5.425 8.52 ;
     RECT  4.787 4.8 5.465 4.824 ;
     RECT  4.025 11.808 5.533 11.832 ;
     RECT  5.389 22.8 5.555 23.736 ;
     RECT  5.425 7.248 5.573 8.52 ;
     RECT  5.101 18.816 5.653 18.84 ;
     RECT  5.573 7.248 5.681 8.424 ;
     RECT  5.681 7.248 5.789 7.416 ;
     RECT  5.653 18.816 5.825 19.416 ;
     RECT  5.789 7.248 5.897 7.272 ;
     RECT  5.555 22.8 5.996 23.496 ;
     RECT  4.933 1.728 6.001 1.848 ;
     RECT  5.825 18.816 6.005 18.84 ;
     RECT  5.533 10.848 6.029 11.832 ;
     RECT  4.565 20.544 6.037 20.568 ;
     RECT  5.996 22.128 6.037 23.496 ;
     RECT  6.037 20.544 6.083 23.496 ;
     RECT  6.001 1.728 6.179 2.28 ;
     RECT  6.029 10.8 6.217 11.832 ;
     RECT  4.061 12.816 6.217 13.704 ;
     RECT  6.217 10.8 6.316 13.704 ;
     RECT  6.316 10.8 6.373 10.872 ;
     RECT  4.781 3.408 6.401 3.432 ;
     RECT  6.373 10.608 6.419 10.872 ;
     RECT  6.325 0.576 6.613 0.6 ;
     RECT  6.083 22.704 6.668 23.496 ;
     RECT  6.613 4.56 6.721 4.584 ;
     RECT  6.613 0.096 6.725 0.6 ;
     RECT  6.505 18.72 6.761 18.744 ;
     RECT  6.721 4.512 6.793 4.584 ;
     RECT  5.681 8.4 6.803 8.424 ;
     RECT  5.353 15.696 6.829 15.72 ;
     RECT  6.793 4.368 6.833 4.584 ;
     RECT  6.829 15.696 6.901 16.584 ;
     RECT  6.668 22.704 6.901 23.544 ;
     RECT  6.181 6.288 6.973 6.84 ;
     RECT  6.901 15.696 7.009 16.632 ;
     RECT  6.316 11.904 7.093 13.704 ;
     RECT  7.009 15.456 7.093 16.632 ;
     RECT  6.973 6.288 7.189 6.888 ;
     RECT  6.179 1.728 7.34 1.848 ;
     RECT  7.117 2.88 7.34 2.904 ;
     RECT  7.189 5.712 7.585 6.888 ;
     RECT  6.901 22.704 7.724 23.736 ;
     RECT  7.724 22.704 7.729 23.928 ;
     RECT  7.34 1.728 7.808 2.904 ;
     RECT  6.833 4.368 7.808 4.536 ;
     RECT  7.585 5.712 7.808 7.224 ;
     RECT  6.901 8.496 7.808 8.52 ;
     RECT  6.419 10.608 7.808 10.68 ;
     RECT  7.093 11.904 7.808 16.632 ;
     RECT  7.093 18.048 7.808 18.072 ;
     RECT  6.083 20.544 7.808 21.432 ;
     RECT  7.729 22.704 7.808 24.552 ;
     RECT  7.808 1.728 8.003 24.552 ;
     RECT  6.725 0.192 8.053 0.6 ;
     RECT  8.003 1.728 8.053 23.976 ;
     RECT  8.053 0.192 8.104 23.976 ;
     RECT  8.104 20.592 8.317 21.672 ;
     RECT  8.104 4.512 8.339 6.936 ;
     RECT  8.104 22.8 8.345 23.976 ;
     RECT  8.104 0.192 8.417 1.752 ;
     RECT  8.345 22.848 8.525 23.976 ;
     RECT  8.104 8.496 8.533 10.776 ;
     RECT  8.339 6.864 8.561 6.936 ;
     RECT  8.104 16.464 8.579 19.224 ;
     RECT  8.579 17.04 8.633 19.224 ;
     RECT  8.633 17.088 8.669 19.224 ;
     RECT  8.525 23.376 8.675 23.976 ;
     RECT  8.533 8.496 8.741 9.096 ;
     RECT  8.104 15.456 9.097 15.48 ;
     RECT  8.533 10.608 9.208 10.776 ;
     RECT  8.339 4.512 9.245 5.736 ;
     RECT  8.104 11.904 9.281 13.08 ;
     RECT  8.317 20.592 9.301 21 ;
     RECT  9.097 15.36 9.385 15.48 ;
     RECT  9.245 4.512 9.389 5.16 ;
     RECT  8.417 0.24 9.461 1.752 ;
     RECT  8.675 23.376 9.565 23.736 ;
     RECT  9.385 14.832 9.641 15.48 ;
     RECT  8.561 6.912 9.781 6.936 ;
     RECT  8.669 17.088 9.817 18.744 ;
     RECT  9.781 6.912 9.821 7.416 ;
     RECT  9.461 1.728 9.845 1.752 ;
     RECT  8.741 9.072 9.853 9.096 ;
     RECT  9.565 22.512 9.923 23.736 ;
     RECT  9.817 17.088 9.925 19.416 ;
     RECT  9.845 1.728 9.928 1.8 ;
     RECT  9.301 20.592 10.037 21.288 ;
     RECT  10.037 21.12 10.141 21.288 ;
     RECT  9.923 23.376 10.141 23.736 ;
     RECT  9.208 10.608 10.177 10.824 ;
     RECT  9.928 1.728 10.225 1.848 ;
     RECT  9.853 9.024 10.249 9.096 ;
     RECT  10.177 10.608 10.249 11.016 ;
     RECT  10.249 9.024 10.333 11.016 ;
     RECT  9.641 15.36 10.355 15.48 ;
     RECT  10.141 21.12 10.361 22.104 ;
     RECT  9.281 12.816 10.393 13.08 ;
     RECT  9.925 17.04 10.577 19.416 ;
     RECT  10.361 21.168 10.649 22.104 ;
     RECT  9.821 7.392 10.652 7.416 ;
     RECT  10.333 9.024 10.652 9.096 ;
     RECT  10.393 12.816 10.652 13.128 ;
     RECT  10.333 10.368 10.739 11.016 ;
     RECT  10.652 12.144 10.739 13.128 ;
     RECT  9.493 0.192 10.741 0.216 ;
     RECT  10.717 25.104 10.853 25.128 ;
     RECT  9.389 4.512 10.865 4.536 ;
     RECT  10.652 7.392 10.883 9.096 ;
     RECT  10.393 14.208 10.901 14.232 ;
     RECT  10.741 0.192 10.937 0.264 ;
     RECT  10.649 22.08 10.973 22.104 ;
     RECT  10.844 19.632 11.041 19.656 ;
     RECT  11.041 19.632 11.125 19.992 ;
     RECT  10.883 7.392 11.293 7.656 ;
     RECT  10.933 5.712 11.437 5.736 ;
     RECT  11.293 7.344 11.437 7.656 ;
     RECT  10.225 1.728 11.473 1.752 ;
     RECT  10.355 15.456 11.509 15.48 ;
     RECT  10.577 17.04 11.581 17.88 ;
     RECT  10.937 0.24 11.605 0.264 ;
     RECT  10.141 23.376 11.651 23.928 ;
     RECT  11.581 17.04 11.653 18.168 ;
     RECT  11.437 5.712 11.765 7.656 ;
     RECT  10.739 12.816 11.765 13.128 ;
     RECT  10.853 25.104 11.801 25.8 ;
     RECT  11.801 25.104 11.843 25.704 ;
     RECT  10.883 8.736 11.905 9.096 ;
     RECT  11.653 17.04 11.905 19.128 ;
     RECT  11.605 0.24 11.989 0.6 ;
     RECT  10.739 10.368 12.085 10.632 ;
     RECT  12.085 10.368 12.125 10.824 ;
     RECT  11.843 25.104 12.131 25.128 ;
     RECT  11.765 5.712 12.193 7.368 ;
     RECT  11.509 15.456 12.193 15.672 ;
     RECT  11.905 16.656 12.193 19.128 ;
     RECT  12.193 5.232 12.373 7.368 ;
     RECT  12.469 20.976 12.517 21 ;
     RECT  11.473 1.728 12.521 2.28 ;
     RECT  12.373 5.136 12.553 7.368 ;
     RECT  11.765 12.816 12.553 13.08 ;
     RECT  11.905 8.448 12.565 9.096 ;
     RECT  11.989 0.192 12.661 0.6 ;
     RECT  11.651 23.376 12.661 23.736 ;
     RECT  12.193 15.456 12.769 19.128 ;
     RECT  12.517 20.976 12.985 21.144 ;
     RECT  12.661 0.192 13.025 1.176 ;
     RECT  12.553 12.528 13.085 13.08 ;
     RECT  12.553 4.512 13.093 7.368 ;
     RECT  12.125 10.608 13.093 10.824 ;
     RECT  13.085 12.528 13.093 13.896 ;
     RECT  12.521 2.148 13.208 2.28 ;
     RECT  13.093 4.512 13.208 7.416 ;
     RECT  12.565 8.448 13.208 9.432 ;
     RECT  13.093 10.608 13.208 10.92 ;
     RECT  13.093 12.528 13.208 14.232 ;
     RECT  12.769 15.312 13.208 19.128 ;
     RECT  12.985 20.976 13.208 21.576 ;
     RECT  12.661 23.376 13.208 23.928 ;
     RECT  13.208 2.148 13.504 23.928 ;
     RECT  13.025 0.192 13.673 0.6 ;
     RECT  13.504 3.6 13.673 5.832 ;
     RECT  13.504 18.144 13.681 18.84 ;
     RECT  13.504 6.912 13.709 11.064 ;
     RECT  13.709 10.32 13.715 11.064 ;
     RECT  13.673 4.464 13.817 5.832 ;
     RECT  13.504 15.312 13.817 15.384 ;
     RECT  13.681 18.144 13.817 18.456 ;
     RECT  13.504 2.148 14.005 2.28 ;
     RECT  14.005 1.728 14.177 2.28 ;
     RECT  14.177 2.256 14.243 2.28 ;
     RECT  13.715 10.32 14.321 10.344 ;
     RECT  13.817 15.36 14.339 15.384 ;
     RECT  13.504 16.656 14.357 16.68 ;
     RECT  13.504 20.736 14.393 21.672 ;
     RECT  13.673 0.192 14.435 0.552 ;
     RECT  13.504 22.8 14.435 23.928 ;
     RECT  13.709 8.4 14.465 9.096 ;
     RECT  13.709 6.912 14.501 7.416 ;
     RECT  14.465 8.4 14.501 8.808 ;
     RECT  14.425 25.104 14.531 25.128 ;
     RECT  13.817 4.464 14.681 5.112 ;
     RECT  14.435 0.192 15.005 0.312 ;
     RECT  13.504 12.528 15.113 13.08 ;
     RECT  15.217 17.088 15.253 17.112 ;
     RECT  13.817 18.144 15.253 18.168 ;
     RECT  14.393 20.736 15.257 21.144 ;
     RECT  15.245 1.728 15.533 1.752 ;
     RECT  15.005 0.192 15.545 0.264 ;
     RECT  14.681 4.896 15.649 5.112 ;
     RECT  14.501 6.912 15.649 6.936 ;
     RECT  14.501 8.784 15.649 8.808 ;
     RECT  15.649 6.816 15.689 6.936 ;
     RECT  15.253 17.088 15.721 18.168 ;
     RECT  14.677 19.488 15.721 19.512 ;
     RECT  15.721 17.088 15.725 19.512 ;
     RECT  15.725 17.616 15.761 19.512 ;
     RECT  15.113 12.816 15.901 13.08 ;
     RECT  15.649 4.896 16.157 5.688 ;
     RECT  15.257 20.736 16.229 21.096 ;
     RECT  16.229 21.024 16.333 21.096 ;
     RECT  15.901 12.816 16.369 13.704 ;
     RECT  16.333 21.024 16.369 21.672 ;
     RECT  14.435 23.376 16.369 23.928 ;
     RECT  16.369 12.384 16.373 13.704 ;
     RECT  15.217 14.832 16.373 14.856 ;
     RECT  15.073 11.376 16.553 11.4 ;
     RECT  16.369 21.024 16.553 23.928 ;
     RECT  16.553 21.024 16.589 21.672 ;
     RECT  16.553 22.8 16.729 23.928 ;
     RECT  15.829 16.416 16.949 16.44 ;
     RECT  16.373 12.384 17.017 13.176 ;
     RECT  15.545 0.192 17.125 0.216 ;
     RECT  15.533 1.728 17.125 1.8 ;
     RECT  15.649 8.544 17.171 8.808 ;
     RECT  17.017 11.952 17.173 13.176 ;
     RECT  16.729 22.8 17.267 24.552 ;
     RECT  17.125 0.192 17.345 1.8 ;
     RECT  17.171 8.544 17.345 8.664 ;
     RECT  17.345 1.728 17.509 1.8 ;
     RECT  17.269 2.88 17.509 2.904 ;
     RECT  16.589 21.024 17.516 21.576 ;
     RECT  15.761 17.616 17.593 19.224 ;
     RECT  17.516 20.544 17.593 21.576 ;
     RECT  17.509 1.728 17.596 2.904 ;
     RECT  17.173 11.952 17.597 13.08 ;
     RECT  17.345 0.192 17.747 0.552 ;
     RECT  17.125 16.512 17.953 16.536 ;
     RECT  17.593 17.616 17.953 21.576 ;
     RECT  15.689 6.816 17.989 6.84 ;
     RECT  16.157 4.896 18.037 5.16 ;
     RECT  17.953 16.512 18.053 21.576 ;
     RECT  18.037 3.984 18.085 5.16 ;
     RECT  17.989 6.816 18.097 6.888 ;
     RECT  18.053 15.984 18.133 21.576 ;
     RECT  17.596 1.728 18.209 2.952 ;
     RECT  18.133 15.504 18.277 21.576 ;
     RECT  17.267 22.8 18.277 23.736 ;
     RECT  17.881 14.208 18.385 14.232 ;
     RECT  18.277 15.504 18.385 23.736 ;
     RECT  18.385 14.208 18.493 23.736 ;
     RECT  18.209 2.148 18.608 2.952 ;
     RECT  18.085 3.984 18.608 5.4 ;
     RECT  18.097 6.816 18.608 7.416 ;
     RECT  17.345 8.544 18.608 8.568 ;
     RECT  17.629 9.648 18.608 9.672 ;
     RECT  17.701 10.656 18.608 10.68 ;
     RECT  17.597 12.384 18.608 13.08 ;
     RECT  18.493 14.208 18.608 23.928 ;
     RECT  17.747 0.192 18.853 0.312 ;
     RECT  18.608 2.148 18.904 23.928 ;
     RECT  18.904 12.816 19.001 17.688 ;
     RECT  18.904 10.08 19.037 11.352 ;
     RECT  18.853 0.192 19.045 0.36 ;
     RECT  19.001 14.688 19.109 17.688 ;
     RECT  18.904 18.768 19.139 23.928 ;
     RECT  18.904 6.864 19.153 7.992 ;
     RECT  19.139 21.168 19.249 23.928 ;
     RECT  17.521 25.104 19.249 25.128 ;
     RECT  19.045 0.192 19.253 0.456 ;
     RECT  19.253 0.192 19.361 0.264 ;
     RECT  19.139 18.768 19.379 19.8 ;
     RECT  18.904 5.04 19.397 5.064 ;
     RECT  19.379 18.864 19.42 19.8 ;
     RECT  18.904 2.148 19.429 2.856 ;
     RECT  19.249 21.168 19.475 25.128 ;
     RECT  19.475 21.168 19.477 23.736 ;
     RECT  19.153 6.864 19.505 7.416 ;
     RECT  19.037 10.08 19.505 10.104 ;
     RECT  19.477 21.168 19.577 22.2 ;
     RECT  19.109 17.664 19.613 17.688 ;
     RECT  19.429 1.728 19.757 2.856 ;
     RECT  19.109 14.688 19.757 16.68 ;
     RECT  19.001 12.816 19.865 13.656 ;
     RECT  19.757 2.736 19.955 2.856 ;
     RECT  19.757 14.832 19.973 16.68 ;
     RECT  19.037 11.328 20.005 11.352 ;
     RECT  20.005 11.328 20.045 11.448 ;
     RECT  19.955 2.736 20.117 2.76 ;
     RECT  19.577 21.168 20.149 21.432 ;
     RECT  20.149 20.688 20.153 21.432 ;
     RECT  19.973 16.368 20.221 16.68 ;
     RECT  19.505 6.864 20.245 6.888 ;
     RECT  20.153 20.688 20.291 20.712 ;
     RECT  19.973 14.832 20.369 14.952 ;
     RECT  19.361 0.192 20.485 0.216 ;
     RECT  20.369 14.928 20.513 14.952 ;
     RECT  19.477 23.376 20.531 23.736 ;
     RECT  20.245 6.816 20.581 6.888 ;
     RECT  20.221 16.368 20.585 17.112 ;
     RECT  19.475 25.104 20.627 25.128 ;
     RECT  18.904 3.984 20.729 4.008 ;
     RECT  19.42 18.864 20.773 18.888 ;
     RECT  20.581 6.816 21.013 6.936 ;
     RECT  20.725 7.968 21.013 7.992 ;
     RECT  20.773 18.864 21.049 19.368 ;
     RECT  20.941 5.664 21.061 5.688 ;
     RECT  21.013 6.768 21.061 7.992 ;
     RECT  21.061 5.664 21.107 7.992 ;
     RECT  21.107 5.808 21.161 7.992 ;
     RECT  21.161 5.808 21.341 6.936 ;
     RECT  20.485 0.192 21.349 0.264 ;
     RECT  21.341 5.808 21.377 6.552 ;
     RECT  19.757 1.728 21.445 1.752 ;
     RECT  20.585 16.464 21.445 17.112 ;
     RECT  19.865 12.816 21.485 13.08 ;
     RECT  21.049 18.864 21.548 19.8 ;
     RECT  21.349 0.192 21.557 0.6 ;
     RECT  21.409 14.832 21.557 14.856 ;
     RECT  21.445 1.728 21.593 1.848 ;
     RECT  21.548 18.72 21.593 19.8 ;
     RECT  21.593 18.72 21.635 18.744 ;
     RECT  20.531 23.376 21.637 23.4 ;
     RECT  21.013 24.528 21.697 24.552 ;
     RECT  21.553 3.84 21.845 3.864 ;
     RECT  21.377 5.808 22.129 5.832 ;
     RECT  21.733 9.696 22.205 9.72 ;
     RECT  20.045 11.424 22.273 11.448 ;
     RECT  21.697 24.528 22.451 25.08 ;
     RECT  21.485 12.96 22.489 13.08 ;
     RECT  21.637 23.376 22.501 23.448 ;
     RECT  21.557 0.192 22.525 0.264 ;
     RECT  22.451 25.056 22.547 25.08 ;
     RECT  22.501 22.8 22.561 23.448 ;
     RECT  22.261 4.08 22.597 4.104 ;
     RECT  22.129 5.136 22.597 5.832 ;
     RECT  22.561 22.176 22.597 23.448 ;
     RECT  22.489 12.96 22.633 13.656 ;
     RECT  22.597 4.08 22.637 5.832 ;
     RECT  22.637 4.512 22.741 5.832 ;
     RECT  21.445 16.464 22.787 17.688 ;
     RECT  22.741 4.512 22.789 5.88 ;
     RECT  22.633 12.96 22.789 14.568 ;
     RECT  21.593 1.728 22.817 1.752 ;
     RECT  22.787 16.464 22.835 17.016 ;
     RECT  22.057 2.88 22.853 2.904 ;
     RECT  22.789 12.96 22.876 15.48 ;
     RECT  22.273 11.424 22.993 11.544 ;
     RECT  21.593 19.728 22.993 19.8 ;
     RECT  22.993 19.728 22.997 20.568 ;
     RECT  22.997 19.824 23.101 20.568 ;
     RECT  22.741 18.672 23.137 18.696 ;
     RECT  21.695 8.544 23.209 8.568 ;
     RECT  23.137 18.672 23.209 18.84 ;
     RECT  23.101 19.824 23.221 21 ;
     RECT  22.597 22.176 23.221 23.928 ;
     RECT  22.876 12.96 23.245 14.856 ;
     RECT  23.065 25.104 23.411 25.128 ;
     RECT  22.789 4.512 23.461 5.976 ;
     RECT  22.993 11.04 23.497 11.544 ;
     RECT  23.209 8.544 23.708 9.096 ;
     RECT  22.525 0.192 23.749 0.312 ;
     RECT  23.221 19.824 23.929 23.928 ;
     RECT  23.317 2.688 23.941 2.712 ;
     RECT  23.461 4.512 23.965 6.264 ;
     RECT  23.941 1.728 24.008 2.712 ;
     RECT  23.965 4.512 24.008 6.84 ;
     RECT  23.708 8.352 24.008 9.096 ;
     RECT  23.497 10.704 24.008 11.544 ;
     RECT  23.245 12.528 24.008 14.856 ;
     RECT  22.835 16.8 24.008 17.016 ;
     RECT  23.209 18.192 24.008 18.84 ;
     RECT  23.929 19.824 24.008 23.976 ;
     RECT  23.749 0.192 24.133 0.36 ;
     RECT  24.008 1.728 24.179 23.976 ;
     RECT  24.179 1.728 24.185 23.928 ;
     RECT  24.185 1.728 24.275 23.88 ;
     RECT  24.275 1.728 24.304 23.502 ;
     RECT  24.304 12.528 24.365 13.656 ;
     RECT  24.133 0.192 24.467 0.456 ;
     RECT  24.304 9.072 24.467 10.632 ;
     RECT  24.304 19.824 24.509 22.296 ;
     RECT  24.467 0.336 24.515 0.36 ;
     RECT  24.304 1.728 24.545 5.16 ;
     RECT  24.545 4.128 24.563 5.16 ;
     RECT  24.545 1.728 24.581 2.952 ;
     RECT  24.563 4.464 24.581 5.16 ;
     RECT  24.304 6.816 24.581 7.464 ;
     RECT  24.581 2.928 24.617 2.952 ;
     RECT  24.467 10.272 24.941 10.632 ;
     RECT  24.467 9.072 25.157 9.096 ;
     RECT  24.581 7.392 25.333 7.464 ;
     RECT  24.304 17.04 25.333 17.064 ;
     RECT  24.509 20.496 25.381 22.296 ;
     RECT  24.304 23.376 25.381 23.448 ;
     RECT  25.333 16.992 25.445 17.64 ;
     RECT  25.381 20.496 25.477 23.448 ;
     RECT  25.477 20.208 25.523 23.448 ;
     RECT  25.523 20.208 25.564 21.672 ;
     RECT  24.581 4.464 25.657 4.536 ;
     RECT  25.333 7.392 25.657 7.992 ;
     RECT  24.581 1.728 25.669 1.848 ;
     RECT  24.469 25.104 25.715 25.128 ;
     RECT  25.564 20.496 25.769 21.672 ;
     RECT  25.669 1.152 25.837 1.848 ;
     RECT  24.365 12.528 25.877 13.08 ;
     RECT  25.657 4.464 25.909 4.872 ;
     RECT  25.657 7.008 25.981 7.992 ;
     RECT  25.909 4.224 26.053 4.872 ;
     RECT  25.837 1.152 26.161 2.28 ;
     RECT  26.161 1.152 26.195 3.24 ;
     RECT  25.981 6.192 26.197 7.992 ;
     RECT  26.195 3.216 26.273 3.24 ;
     RECT  24.304 18.72 26.273 18.744 ;
     RECT  26.197 6.192 26.309 8.184 ;
     RECT  26.195 1.152 26.341 1.752 ;
     RECT  25.445 17.04 26.341 17.64 ;
     RECT  25.801 24.528 26.387 24.552 ;
     RECT  25.523 23.376 26.521 23.448 ;
     RECT  26.341 17.04 26.557 17.688 ;
     RECT  26.309 6.192 26.627 7.032 ;
     RECT  26.627 6.288 26.741 7.032 ;
     RECT  25.729 9.6 26.771 9.624 ;
     RECT  26.665 15.984 26.771 16.008 ;
     RECT  26.053 4.224 26.773 5.16 ;
     RECT  26.773 3.408 26.813 5.16 ;
     RECT  26.813 3.408 26.819 4.632 ;
     RECT  26.819 3.408 26.885 3.432 ;
     RECT  24.941 10.608 26.981 10.632 ;
     RECT  25.909 11.904 26.981 11.928 ;
     RECT  26.819 4.608 26.993 4.632 ;
     RECT  26.341 0.192 27.029 1.752 ;
     RECT  26.981 10.608 27.065 11.928 ;
     RECT  27.029 1.104 27.245 1.752 ;
     RECT  25.769 21.648 27.317 21.672 ;
     RECT  27.065 11.904 27.353 11.928 ;
     RECT  26.521 19.392 27.353 19.416 ;
     RECT  25.369 14.928 27.457 14.952 ;
     RECT  26.741 6.672 27.491 7.032 ;
     RECT  25.769 20.496 27.605 20.52 ;
     RECT  27.457 14.832 27.641 14.952 ;
     RECT  27.491 6.672 27.853 6.84 ;
     RECT  25.877 13.056 27.853 13.08 ;
     RECT  26.521 23.376 27.925 23.736 ;
     RECT  27.853 5.712 27.997 6.84 ;
     RECT  27.925 22.848 28.012 24.552 ;
     RECT  27.788 2.256 28.021 2.28 ;
     RECT  28.012 22.848 28.021 23.976 ;
     RECT  27.817 3.504 28.217 3.528 ;
     RECT  27.997 5.664 28.253 6.84 ;
     RECT  28.021 2.256 28.289 2.328 ;
     RECT  27.245 1.104 28.309 1.176 ;
     RECT  28.309 0.192 28.361 1.176 ;
     RECT  28.117 25.056 28.361 25.128 ;
     RECT  28.289 2.256 28.405 2.28 ;
     RECT  28.285 11.616 28.429 11.64 ;
     RECT  28.253 6.672 28.433 6.84 ;
     RECT  28.405 1.68 28.643 2.28 ;
     RECT  28.021 22.608 28.643 23.976 ;
     RECT  28.493 21.12 28.681 21.144 ;
     RECT  28.643 22.608 28.681 23.928 ;
     RECT  28.433 6.816 28.825 6.84 ;
     RECT  27.641 14.928 28.861 14.952 ;
     RECT  28.717 15.984 28.861 16.008 ;
     RECT  28.861 14.928 29.149 16.008 ;
     RECT  29.041 19.536 29.221 19.56 ;
     RECT  28.361 25.104 29.221 25.128 ;
     RECT  28.361 0.192 29.297 0.6 ;
     RECT  29.149 14.496 29.329 16.008 ;
     RECT  26.557 17.04 29.329 18.264 ;
     RECT  28.643 1.776 29.408 2.28 ;
     RECT  28.609 5.04 29.408 5.112 ;
     RECT  28.825 6.816 29.408 6.888 ;
     RECT  26.309 8.16 29.408 8.184 ;
     RECT  29.173 9.504 29.408 9.528 ;
     RECT  27.065 10.608 29.408 10.632 ;
     RECT  28.429 11.616 29.408 11.976 ;
     RECT  27.853 13.056 29.408 13.464 ;
     RECT  29.329 14.496 29.408 18.264 ;
     RECT  29.221 19.536 29.408 19.896 ;
     RECT  28.681 21.12 29.408 23.928 ;
     RECT  29.408 1.776 29.585 23.928 ;
     RECT  29.585 1.776 29.704 23.502 ;
     RECT  29.704 19.872 29.765 21.672 ;
     RECT  29.221 25.104 29.837 25.224 ;
     RECT  29.837 25.152 29.845 25.224 ;
     RECT  29.845 25.152 29.869 25.704 ;
     RECT  29.704 4.512 29.891 5.208 ;
     RECT  29.704 12.48 29.987 13.08 ;
     RECT  29.765 19.92 30.025 21.672 ;
     RECT  29.704 16.512 30.061 18.84 ;
     RECT  29.297 0.192 30.089 0.36 ;
     RECT  29.704 1.776 30.229 1.848 ;
     RECT  29.704 8.544 30.269 11.304 ;
     RECT  30.089 0.288 30.305 0.36 ;
     RECT  30.025 19.92 30.349 21.096 ;
     RECT  29.704 22.8 30.371 23.448 ;
     RECT  30.305 0.288 30.377 0.312 ;
     RECT  29.869 25.152 30.377 25.8 ;
     RECT  30.377 25.152 30.412 25.704 ;
     RECT  30.349 19.92 30.413 20.472 ;
     RECT  29.891 5.184 30.419 5.208 ;
     RECT  30.061 16.512 30.563 18.408 ;
     RECT  29.704 6.24 30.659 6.264 ;
     RECT  30.269 8.544 30.659 10.632 ;
     RECT  29.987 12.528 30.659 13.08 ;
     RECT  30.659 12.528 30.665 12.552 ;
     RECT  30.563 16.512 30.665 17.88 ;
     RECT  30.229 1.728 30.697 1.848 ;
     RECT  30.371 23.136 30.733 23.448 ;
     RECT  30.665 16.512 30.86 17.736 ;
     RECT  30.697 1.728 30.901 1.896 ;
     RECT  30.733 23.136 30.947 23.976 ;
     RECT  30.659 8.544 31.004 9.096 ;
     RECT  31.004 8.448 31.091 9.096 ;
     RECT  30.901 1.728 31.169 2.328 ;
     RECT  30.412 25.152 31.237 25.176 ;
     RECT  31.189 0.192 31.381 0.216 ;
     RECT  31.381 0.192 31.489 0.264 ;
     RECT  30.413 20.448 31.561 20.472 ;
     RECT  31.561 20.448 31.601 20.568 ;
     RECT  31.237 25.104 31.619 25.176 ;
     RECT  31.489 0.192 31.673 0.552 ;
     RECT  30.86 16.416 31.777 17.736 ;
     RECT  31.091 9.072 31.853 9.096 ;
     RECT  31.673 0.24 31.889 0.552 ;
     RECT  31.777 15.84 31.907 17.736 ;
     RECT  31.601 20.544 32.012 20.568 ;
     RECT  30.947 23.136 32.053 23.448 ;
     RECT  32.053 22.8 32.108 23.448 ;
     RECT  32.012 20.544 32.156 21 ;
     RECT  32.108 22.8 32.195 23.736 ;
     RECT  32.156 20.544 32.243 21.672 ;
     RECT  31.169 1.728 32.245 1.752 ;
     RECT  31.309 3.408 32.245 3.432 ;
     RECT  31.057 6 32.317 6.024 ;
     RECT  32.245 1.728 32.437 1.848 ;
     RECT  31.907 16.512 32.537 17.448 ;
     RECT  32.437 1.728 32.645 2.184 ;
     RECT  31.619 25.104 32.857 25.128 ;
     RECT  32.389 12 32.965 12.024 ;
     RECT  32.195 22.8 33.037 23.16 ;
     RECT  32.317 5.664 33.061 6.024 ;
     RECT  33.061 5.088 33.149 6.024 ;
     RECT  32.965 12 33.155 12.552 ;
     RECT  31.957 0.576 33.205 0.6 ;
     RECT  30.659 10.608 33.253 10.632 ;
     RECT  32.245 3.36 33.289 3.432 ;
     RECT  33.037 18.72 33.308 18.744 ;
     RECT  32.857 24.528 33.325 25.128 ;
     RECT  33.037 22.224 33.329 23.16 ;
     RECT  33.325 24.528 33.347 25.656 ;
     RECT  32.243 20.544 33.349 21.096 ;
     RECT  33.308 18.72 33.397 19.368 ;
     RECT  33.349 20.544 33.397 21.144 ;
     RECT  33.347 25.104 33.491 25.656 ;
     RECT  33.149 6 33.505 6.024 ;
     RECT  33.491 25.104 33.581 25.128 ;
     RECT  33.505 6 33.589 6.696 ;
     RECT  33.289 2.88 33.613 3.432 ;
     RECT  33.037 9.12 33.613 9.144 ;
     RECT  32.605 13.632 33.653 13.656 ;
     RECT  33.205 0.192 33.685 0.6 ;
     RECT  32.645 1.728 33.685 1.752 ;
     RECT  33.613 9.072 33.692 9.144 ;
     RECT  33.589 6 33.761 7.464 ;
     RECT  33.692 9.072 33.779 9.384 ;
     RECT  33.397 18.72 33.781 21.144 ;
     RECT  33.155 12 33.797 12.024 ;
     RECT  33.685 0.192 33.833 1.752 ;
     RECT  33.253 10.608 33.901 10.728 ;
     RECT  33.833 1.152 33.905 1.752 ;
     RECT  33.905 1.728 33.94 1.752 ;
     RECT  33.94 1.728 34.124 1.8 ;
     RECT  33.613 2.88 34.124 4.296 ;
     RECT  33.289 15.264 34.165 15.288 ;
     RECT  32.537 17.424 34.213 17.448 ;
     RECT  33.781 18.72 34.213 21.192 ;
     RECT  33.469 23.376 34.501 23.928 ;
     RECT  34.213 17.424 34.549 21.192 ;
     RECT  34.124 1.728 34.729 4.296 ;
     RECT  33.761 6 34.729 6.696 ;
     RECT  34.729 1.728 34.808 6.696 ;
     RECT  33.925 7.776 34.808 7.8 ;
     RECT  33.779 9.072 34.808 9.096 ;
     RECT  33.901 10.608 34.808 10.968 ;
     RECT  34.621 14.112 34.808 14.136 ;
     RECT  34.165 15.264 34.808 15.672 ;
     RECT  34.549 16.896 34.808 21.192 ;
     RECT  33.329 22.224 34.808 22.248 ;
     RECT  34.501 23.376 34.808 24.024 ;
     RECT  34.808 1.728 35.104 24.024 ;
     RECT  35.104 1.728 35.219 6.84 ;
     RECT  34.837 25.056 35.219 25.08 ;
     RECT  35.104 9.648 35.267 11.208 ;
     RECT  35.104 23.376 35.305 24.024 ;
     RECT  35.104 12.864 35.363 15.288 ;
     RECT  35.363 12.864 35.404 13.656 ;
     RECT  35.219 4.848 35.603 6.84 ;
     RECT  35.219 1.728 35.669 3.672 ;
     RECT  35.669 2.256 35.843 3.672 ;
     RECT  35.603 4.848 35.987 5.256 ;
     RECT  35.104 16.896 36.028 21.912 ;
     RECT  35.893 0.192 36.085 0.216 ;
     RECT  35.267 10.608 36.085 11.208 ;
     RECT  36.028 16.896 36.085 21.192 ;
     RECT  36.085 10.608 36.173 11.304 ;
     RECT  35.843 2.64 36.179 3.672 ;
     RECT  35.603 6.24 36.245 6.84 ;
     RECT  35.305 23.376 36.245 24.552 ;
     RECT  36.085 16.56 36.317 21.192 ;
     RECT  36.317 17.088 36.353 21.192 ;
     RECT  36.085 0.192 36.469 0.6 ;
     RECT  35.987 5.232 36.569 5.256 ;
     RECT  36.469 0.192 36.661 1.176 ;
     RECT  35.363 14.88 36.668 15.288 ;
     RECT  36.661 0.192 36.677 1.224 ;
     RECT  36.668 14.304 36.709 15.288 ;
     RECT  36.229 22.224 36.709 22.248 ;
     RECT  36.245 23.376 36.709 23.928 ;
     RECT  36.173 10.608 36.821 11.208 ;
     RECT  35.404 12.864 36.853 13.08 ;
     RECT  36.853 12.528 36.929 13.08 ;
     RECT  36.677 0.576 36.949 1.224 ;
     RECT  36.179 2.64 36.949 2.664 ;
     RECT  36.949 0.576 37.001 2.664 ;
     RECT  36.661 25.056 37.043 25.08 ;
     RECT  37.001 0.576 37.109 2.184 ;
     RECT  36.353 20.544 37.109 21.192 ;
     RECT  36.929 12.528 37.285 12.936 ;
     RECT  36.353 17.088 37.285 19.368 ;
     RECT  37.285 12 37.331 12.936 ;
     RECT  37.285 16.512 37.333 19.368 ;
     RECT  37.109 20.688 37.357 21.192 ;
     RECT  36.709 22.224 37.357 23.928 ;
     RECT  37.333 16.512 37.369 19.416 ;
     RECT  36.245 6.24 37.381 6.696 ;
     RECT  36.421 7.968 37.381 7.992 ;
     RECT  37.381 6.24 37.427 7.992 ;
     RECT  36.709 14.112 37.427 15.288 ;
     RECT  37.427 6.816 37.469 7.992 ;
     RECT  37.357 20.688 37.505 23.928 ;
     RECT  37.109 0.576 37.577 1.8 ;
     RECT  36.821 10.608 37.669 10.872 ;
     RECT  37.369 17.136 37.685 19.416 ;
     RECT  37.685 17.136 37.757 19.224 ;
     RECT  37.669 10.224 37.861 10.872 ;
     RECT  37.577 0.576 37.901 1.176 ;
     RECT  37.757 17.136 37.901 18.552 ;
     RECT  37.901 0.576 37.909 0.6 ;
     RECT  37.909 0.192 37.937 0.6 ;
     RECT  37.469 7.968 37.969 7.992 ;
     RECT  36.179 3.648 38.009 3.672 ;
     RECT  37.331 12 38.189 12.552 ;
     RECT  38.149 5.232 38.233 5.736 ;
     RECT  37.861 9.936 38.243 10.872 ;
     RECT  38.243 10.272 38.297 10.872 ;
     RECT  38.149 3.936 38.435 3.96 ;
     RECT  38.396 2.688 38.483 2.712 ;
     RECT  37.469 6.816 38.509 6.84 ;
     RECT  37.969 7.968 38.509 8.568 ;
     RECT  37.427 15.264 38.549 15.288 ;
     RECT  37.505 21.12 38.579 23.928 ;
     RECT  38.509 6.816 38.581 8.568 ;
     RECT  38.579 21.12 38.581 22.824 ;
     RECT  37.393 25.104 38.617 25.128 ;
     RECT  38.581 6.816 38.621 8.76 ;
     RECT  38.581 21.072 38.765 22.824 ;
     RECT  38.189 12.528 38.801 12.552 ;
     RECT  37.901 17.136 38.833 18.312 ;
     RECT  38.617 25.104 38.861 25.176 ;
     RECT  38.833 16.752 38.869 18.312 ;
     RECT  37.937 0.192 38.917 0.312 ;
     RECT  38.861 25.104 38.945 25.8 ;
     RECT  38.945 25.104 38.963 25.704 ;
     RECT  37.427 14.112 39.157 14.136 ;
     RECT  38.917 0.192 39.205 0.36 ;
     RECT  38.233 5.232 39.301 5.4 ;
     RECT  38.621 8.736 39.329 8.76 ;
     RECT  38.297 10.272 39.329 10.296 ;
     RECT  39.157 14.112 39.337 14.28 ;
     RECT  38.869 16.512 39.356 18.312 ;
     RECT  39.205 0.192 39.377 0.408 ;
     RECT  39.377 0.24 39.445 0.408 ;
     RECT  39.445 0.24 39.449 1.128 ;
     RECT  39.449 0.288 39.521 1.128 ;
     RECT  39.356 15.888 39.553 18.312 ;
     RECT  38.765 21.648 39.589 22.824 ;
     RECT  38.579 23.904 39.589 23.928 ;
     RECT  38.621 6.816 39.697 7.704 ;
     RECT  39.329 8.736 39.697 10.296 ;
     RECT  39.521 0.336 39.761 1.128 ;
     RECT  39.589 21.648 39.841 23.928 ;
     RECT  38.963 25.104 39.841 25.128 ;
     RECT  39.301 5.136 39.877 5.4 ;
     RECT  39.697 6.816 39.877 10.296 ;
     RECT  39.337 14.112 39.925 14.904 ;
     RECT  39.925 13.824 39.949 14.904 ;
     RECT  39.553 15.888 39.949 18.84 ;
     RECT  39.841 21.648 40.019 25.128 ;
     RECT  39.949 13.824 40.049 18.84 ;
     RECT  39.761 0.336 40.115 1.752 ;
     RECT  39.589 2.88 40.165 2.904 ;
     RECT  40.115 1.728 40.208 1.752 ;
     RECT  40.165 2.88 40.208 3.432 ;
     RECT  39.877 5.136 40.208 10.296 ;
     RECT  39.841 12.528 40.208 12.552 ;
     RECT  40.049 13.824 40.208 19.416 ;
     RECT  40.019 21.648 40.208 23.928 ;
     RECT  40.208 1.728 40.307 23.928 ;
     RECT  40.307 1.728 40.385 23.88 ;
     RECT  40.385 2.418 40.504 23.88 ;
     RECT  40.115 0.336 40.537 0.6 ;
     RECT  40.504 2.976 40.601 4.248 ;
     RECT  40.504 5.568 40.643 6.12 ;
     RECT  40.504 20.544 40.643 22.008 ;
     RECT  40.504 23.376 40.643 23.88 ;
     RECT  40.537 0.336 40.645 0.552 ;
     RECT  40.504 11.376 40.691 12.552 ;
     RECT  40.643 23.376 40.691 23.496 ;
     RECT  40.504 14.208 40.739 14.76 ;
     RECT  40.601 2.976 40.745 4.152 ;
     RECT  40.691 11.376 40.753 12.024 ;
     RECT  40.745 3.648 40.781 4.152 ;
     RECT  40.643 20.544 40.781 21.768 ;
     RECT  40.643 5.568 40.787 5.592 ;
     RECT  40.781 20.544 40.825 21.144 ;
     RECT  40.781 3.648 40.853 4.008 ;
     RECT  40.753 11.376 40.883 11.4 ;
     RECT  40.691 23.472 40.883 23.496 ;
     RECT  40.504 17.136 40.897 17.16 ;
     RECT  40.739 14.736 40.931 14.76 ;
     RECT  40.825 20.544 40.933 20.568 ;
     RECT  40.645 0.192 40.961 0.552 ;
     RECT  40.853 3.984 40.961 4.008 ;
     RECT  40.961 0.528 40.979 0.552 ;
     RECT  40.019 25.104 40.979 25.128 ;
    LAYER M5 ;
     RECT  2.16 0.144 40.968 0.323 ;
     RECT  18.864 0.323 37.848 0.371 ;
     RECT  38.928 0.323 40.968 0.371 ;
     RECT  39.216 0.371 40.968 0.419 ;
     RECT  2.16 0.323 17.832 0.563 ;
     RECT  39.6 0.419 40.968 0.563 ;
     RECT  19.008 0.371 37.848 1.187 ;
     RECT  19.008 1.187 37.56 1.235 ;
     RECT  2.16 0.563 14.232 1.763 ;
     RECT  15.264 0.563 17.832 1.763 ;
     RECT  19.008 1.235 35.832 1.763 ;
     RECT  2.16 1.763 8.856 1.811 ;
     RECT  9.888 1.763 14.232 1.811 ;
     RECT  15.552 1.763 17.832 1.811 ;
     RECT  36.96 1.235 37.56 1.811 ;
     RECT  4.944 1.811 4.968 1.859 ;
     RECT  6.144 1.811 8.856 1.859 ;
     RECT  9.984 1.811 14.232 1.859 ;
     RECT  19.008 1.763 21.48 1.859 ;
     RECT  22.512 1.763 26.568 1.859 ;
     RECT  27.84 1.763 30.936 1.859 ;
     RECT  32.256 1.763 32.472 1.859 ;
     RECT  30.72 1.859 30.936 1.907 ;
     RECT  17.52 1.811 17.832 2.137 ;
     RECT  19.008 1.859 20.616 2.137 ;
     RECT  32.448 1.859 32.472 2.195 ;
     RECT  36.96 1.811 36.984 2.195 ;
     RECT  6.144 1.859 6.168 2.291 ;
     RECT  10.944 1.859 14.232 2.291 ;
     RECT  17.52 2.137 20.616 2.291 ;
     RECT  27.84 1.859 29.712 2.291 ;
     RECT  33.6 1.763 35.832 2.291 ;
     RECT  28.032 2.291 28.056 2.339 ;
     RECT  30.912 1.907 30.936 2.339 ;
     RECT  18.048 2.291 20.616 2.867 ;
     RECT  22.512 1.859 24.552 2.869 ;
     RECT  2.16 1.811 3.912 2.915 ;
     RECT  39.6 0.563 40.872 2.915 ;
     RECT  33.6 2.291 33.624 3.349 ;
     RECT  34.8 2.291 35.64 3.349 ;
     RECT  26.064 1.859 26.568 3.397 ;
     RECT  38.448 2.677 38.472 3.925 ;
     RECT  2.16 2.915 3.48 4.019 ;
     RECT  39.984 2.915 40.872 4.019 ;
     RECT  2.4 4.019 3.48 4.211 ;
     RECT  33.168 3.349 33.624 4.261 ;
     RECT  22.272 2.869 24.552 4.453 ;
     RECT  26.064 3.397 26.808 4.453 ;
     RECT  7.2 1.859 8.856 4.501 ;
     RECT  13.104 2.291 13.608 4.501 ;
     RECT  29.4 2.291 29.712 4.501 ;
     RECT  22.272 4.453 26.808 4.643 ;
     RECT  13.104 4.501 13.656 4.837 ;
     RECT  13.104 4.837 14.376 5.077 ;
     RECT  18.048 2.867 19.128 5.077 ;
     RECT  29.4 4.501 29.88 5.077 ;
     RECT  33.168 4.261 33.816 5.077 ;
     RECT  2.4 4.211 2.856 5.171 ;
     RECT  22.272 4.643 26.568 5.171 ;
     RECT  28.8 5.077 29.88 5.173 ;
     RECT  38.4 3.925 38.472 5.221 ;
     RECT  39.984 4.019 40.728 5.365 ;
     RECT  39.696 5.365 40.728 5.557 ;
     RECT  20.592 2.867 20.616 5.653 ;
     RECT  28.8 5.173 30.408 5.653 ;
     RECT  6.768 4.501 8.856 5.747 ;
     RECT  10.944 2.291 10.968 5.747 ;
     RECT  22.512 5.171 25.32 5.747 ;
     RECT  38.16 5.221 38.472 5.747 ;
     RECT  2.4 5.171 2.808 5.795 ;
     RECT  13.104 5.077 14.808 5.795 ;
     RECT  22.656 5.747 25.32 5.795 ;
     RECT  22.752 5.795 25.32 5.891 ;
     RECT  22.8 5.891 25.32 5.987 ;
     RECT  26.352 5.171 26.568 6.181 ;
     RECT  28.032 5.653 30.408 6.229 ;
     RECT  4.752 5.653 4.776 6.323 ;
     RECT  26.352 6.181 26.616 6.661 ;
     RECT  28.032 6.229 30.648 6.661 ;
     RECT  20.592 5.653 21.096 6.803 ;
     RECT  20.592 6.803 20.616 6.805 ;
     RECT  20.256 6.805 20.616 6.947 ;
     RECT  26.352 6.661 30.648 7.043 ;
     RECT  6.768 5.747 6.792 7.189 ;
     RECT  7.8 5.747 8.328 7.189 ;
     RECT  13.2 5.795 14.808 7.333 ;
     RECT  5.568 7.333 5.592 7.381 ;
     RECT  23.04 5.987 25.32 7.381 ;
     RECT  26.352 7.043 26.616 7.381 ;
     RECT  33.072 5.077 33.816 7.765 ;
     RECT  34.8 3.349 36.168 7.765 ;
     RECT  2.4 5.795 2.712 7.957 ;
     RECT  17.712 5.077 19.128 8.003 ;
     RECT  23.04 7.381 26.616 8.195 ;
     RECT  10.848 7.381 10.872 8.341 ;
     RECT  28.032 7.043 30.648 8.437 ;
     RECT  10.704 8.341 10.872 8.483 ;
     RECT  4.704 7.381 5.592 8.531 ;
     RECT  6.768 7.189 8.328 8.531 ;
     RECT  17.712 8.003 18.912 8.533 ;
     RECT  12.768 7.333 14.808 8.819 ;
     RECT  10.704 8.483 10.728 9.061 ;
     RECT  12.768 8.819 14.376 9.061 ;
     RECT  10.272 9.061 10.728 9.107 ;
     RECT  28.032 8.437 31.08 9.107 ;
     RECT  33.072 7.765 36.168 9.107 ;
     RECT  12.672 9.061 14.376 9.397 ;
     RECT  26.352 8.195 26.616 9.589 ;
     RECT  7.8 8.531 8.328 9.637 ;
     RECT  38.4 5.747 38.472 9.637 ;
     RECT  39.696 5.557 40.776 9.637 ;
     RECT  10.272 9.107 10.296 9.731 ;
     RECT  21.744 8.533 21.768 9.731 ;
     RECT  37.392 6.229 37.416 9.925 ;
     RECT  38.4 9.637 40.776 9.925 ;
     RECT  23.04 8.195 25.32 10.307 ;
     RECT  37.392 9.925 40.776 10.307 ;
     RECT  5.568 8.531 5.592 10.597 ;
     RECT  6.768 8.531 6.792 10.597 ;
     RECT  26.352 9.589 26.76 10.597 ;
     RECT  37.392 10.307 38.472 10.597 ;
     RECT  5.568 10.597 6.792 10.643 ;
     RECT  12.576 9.397 14.376 10.643 ;
     RECT  5.568 10.643 6.408 10.883 ;
     RECT  39.696 10.307 40.776 11.365 ;
     RECT  26.352 10.597 27.048 11.459 ;
     RECT  10.704 10.357 10.728 12.179 ;
     RECT  5.568 10.883 6.264 12.611 ;
     RECT  0.24 7.525 0.264 12.851 ;
     RECT  17.136 8.533 18.912 12.901 ;
     RECT  20.256 6.947 20.28 12.901 ;
     RECT  12.672 10.643 14.376 12.949 ;
     RECT  23.04 10.307 24.312 12.949 ;
     RECT  25.296 10.307 25.32 12.949 ;
     RECT  26.352 11.459 26.76 12.949 ;
     RECT  34.8 9.107 36.168 13.045 ;
     RECT  37.296 10.597 38.472 13.045 ;
     RECT  5.568 12.611 5.592 13.139 ;
     RECT  17.136 12.901 20.28 13.187 ;
     RECT  17.568 13.187 20.28 13.667 ;
     RECT  7.8 9.637 8.52 13.669 ;
     RECT  2.4 7.957 3.528 13.715 ;
     RECT  7.584 13.669 8.52 14.533 ;
     RECT  39.696 11.365 40.872 14.725 ;
     RECT  3.984 14.197 4.008 14.773 ;
     RECT  17.568 13.667 18.912 14.773 ;
     RECT  16.32 13.669 16.344 14.867 ;
     RECT  25.296 12.949 26.76 14.963 ;
     RECT  34.8 13.045 38.472 15.059 ;
     RECT  3.984 14.773 4.056 15.443 ;
     RECT  7.104 14.533 8.52 15.445 ;
     RECT  33.072 9.107 33.816 15.637 ;
     RECT  34.8 15.059 36.168 15.637 ;
     RECT  37.392 15.059 38.472 15.877 ;
     RECT  39.696 14.725 40.92 15.877 ;
     RECT  26.352 14.963 26.76 16.019 ;
     RECT  17.568 14.773 19.08 16.309 ;
     RECT  20.256 13.667 20.28 16.309 ;
     RECT  28.032 9.107 30.648 16.405 ;
     RECT  31.872 15.829 31.896 16.405 ;
     RECT  22.32 12.949 24.312 16.453 ;
     RECT  17.568 16.309 20.28 16.501 ;
     RECT  37.392 15.877 40.92 16.501 ;
     RECT  25.296 14.963 25.32 16.981 ;
     RECT  7.104 15.445 8.568 17.075 ;
     RECT  2.4 13.715 2.712 17.077 ;
     RECT  3.984 15.443 4.008 17.077 ;
     RECT  10.32 15.349 10.344 17.077 ;
     RECT  21.552 16.453 24.312 17.171 ;
     RECT  33.072 15.637 36.168 17.605 ;
     RECT  37.296 16.501 40.92 17.605 ;
     RECT  2.4 17.077 4.008 17.651 ;
     RECT  10.224 17.077 10.344 17.699 ;
     RECT  15.84 16.405 15.864 17.699 ;
     RECT  26.352 16.019 26.616 17.699 ;
     RECT  28.032 16.405 31.896 17.699 ;
     RECT  31.872 17.699 31.896 17.747 ;
     RECT  10.32 17.699 10.344 17.845 ;
     RECT  7.104 17.075 8.52 18.083 ;
     RECT  3.984 17.651 4.008 18.181 ;
     RECT  7.392 18.083 8.52 18.275 ;
     RECT  26.592 17.699 26.616 18.275 ;
     RECT  28.032 17.699 30.552 18.419 ;
     RECT  22.32 17.171 24.312 18.709 ;
     RECT  10.32 17.845 11.112 18.757 ;
     RECT  12.528 12.949 14.376 18.757 ;
     RECT  28.032 18.419 30.024 18.851 ;
     RECT  17.136 16.501 20.28 19.333 ;
     RECT  21.6 18.709 24.312 19.333 ;
     RECT  3.984 18.181 4.584 19.379 ;
     RECT  5.664 13.621 5.688 19.427 ;
     RECT  17.136 19.333 24.312 19.811 ;
     RECT  22.32 19.811 24.312 19.813 ;
     RECT  25.296 16.981 25.368 19.813 ;
     RECT  28.032 18.851 29.976 19.909 ;
     RECT  3.984 19.379 4.008 20.003 ;
     RECT  2.4 17.651 2.712 20.053 ;
     RECT  22.32 19.813 25.368 20.197 ;
     RECT  33.072 17.605 40.92 20.579 ;
     RECT  17.136 19.811 20.808 20.723 ;
     RECT  7.392 18.275 8.328 20.965 ;
     RECT  33.072 20.579 40.776 20.965 ;
     RECT  10.32 18.757 14.376 21.155 ;
     RECT  32.064 20.965 40.776 21.155 ;
     RECT  6.816 20.965 8.328 21.397 ;
     RECT  2.4 20.053 2.808 21.493 ;
     RECT  10.896 21.155 14.376 21.683 ;
     RECT  32.064 21.155 40.728 21.683 ;
     RECT  32.064 21.683 40.632 21.923 ;
     RECT  4.896 21.637 4.92 22.165 ;
     RECT  22.32 20.197 25.512 22.259 ;
     RECT  36.24 21.923 40.632 22.259 ;
     RECT  9.312 21.253 9.336 22.501 ;
     RECT  2.304 21.493 2.808 22.741 ;
     RECT  10.896 21.683 14.328 22.789 ;
     RECT  2.304 22.741 3.432 22.981 ;
     RECT  4.8 22.165 4.92 22.981 ;
     RECT  2.304 22.981 4.92 23.365 ;
     RECT  6.048 21.397 8.328 23.365 ;
     RECT  9.312 22.501 9.912 23.365 ;
     RECT  10.896 22.789 14.424 23.365 ;
     RECT  17.136 20.723 19.464 23.365 ;
     RECT  20.784 20.723 20.808 23.365 ;
     RECT  22.32 22.259 24.312 23.365 ;
     RECT  25.392 22.259 25.512 23.365 ;
     RECT  28.032 19.909 30.36 23.365 ;
     RECT  32.064 21.923 35.208 23.365 ;
     RECT  36.72 22.259 40.632 23.365 ;
     RECT  36.288 23.365 40.68 23.461 ;
     RECT  2.16 23.365 35.208 23.701 ;
     RECT  36.288 23.461 40.872 23.701 ;
     RECT  2.16 23.701 40.872 25.093 ;
     RECT  2.16 25.093 40.968 25.744 ;
     RECT  4.8 25.744 5.064 25.811 ;
     RECT  10.896 25.744 11.784 25.811 ;
     RECT  29.904 25.744 30.312 25.811 ;
     RECT  38.88 25.744 38.904 25.811 ;
     RECT  17.832 0.323 18.864 0.371 ;
     RECT  37.848 0.323 38.928 0.371 ;
     RECT  17.832 0.371 19.008 2.137 ;
     RECT  37.848 0.371 39.216 0.419 ;
     RECT  14.232 0.563 15.264 1.763 ;
     RECT  35.832 1.235 36.96 2.195 ;
     RECT  8.856 1.763 9.888 1.811 ;
     RECT  14.232 1.763 15.552 1.811 ;
     RECT  21.48 1.763 22.512 1.859 ;
     RECT  26.568 1.763 27.84 2.291 ;
     RECT  30.936 1.763 32.256 1.859 ;
     RECT  32.472 1.763 33.6 2.195 ;
     RECT  3.912 1.811 4.944 1.859 ;
     RECT  4.968 1.811 6.144 1.859 ;
     RECT  8.856 1.811 9.984 1.859 ;
     RECT  6.168 1.859 7.2 2.291 ;
     RECT  22.272 1.859 22.512 2.869 ;
     RECT  24.552 1.859 26.064 4.453 ;
     RECT  29.712 1.859 30.72 1.907 ;
     RECT  30.936 1.859 32.448 2.195 ;
     RECT  29.712 1.907 30.912 2.339 ;
     RECT  33.168 2.195 33.6 3.349 ;
     RECT  35.832 2.195 36.168 2.291 ;
     RECT  26.568 2.291 28.032 2.339 ;
     RECT  28.056 2.291 29.4 2.339 ;
     RECT  33.624 2.291 34.8 4.261 ;
     RECT  35.64 2.291 36.168 3.349 ;
     RECT  26.568 2.339 26.808 3.397 ;
     RECT  38.472 2.677 39.6 2.915 ;
     RECT  19.128 2.867 20.592 6.805 ;
     RECT  38.472 2.915 39.984 5.365 ;
     RECT  33.816 4.261 34.8 7.765 ;
     RECT  26.568 4.643 26.808 5.653 ;
     RECT  22.272 5.171 22.512 5.653 ;
     RECT  25.32 5.171 26.352 7.381 ;
     RECT  38.472 5.365 39.696 9.637 ;
     RECT  21.096 5.653 22.512 5.747 ;
     RECT  26.568 5.653 28.032 6.181 ;
     RECT  6.792 5.747 7.8 7.189 ;
     RECT  38.16 5.747 38.4 6.229 ;
     RECT  26.616 6.181 28.032 6.661 ;
     RECT  36.168 6.229 37.392 10.597 ;
     RECT  37.416 6.229 38.4 9.925 ;
     RECT  4.752 6.323 4.776 7.333 ;
     RECT  19.128 6.805 20.256 8.003 ;
     RECT  26.616 7.043 28.032 9.589 ;
     RECT  4.752 7.333 5.568 7.381 ;
     RECT  5.592 7.333 6.768 10.597 ;
     RECT  3.528 7.957 4.704 8.531 ;
     RECT  18.912 8.003 20.256 12.901 ;
     RECT  25.32 8.195 26.352 12.949 ;
     RECT  6.792 8.531 7.8 10.643 ;
     RECT  20.28 8.533 21.744 9.731 ;
     RECT  21.768 8.533 23.04 9.731 ;
     RECT  10.296 9.107 10.728 9.731 ;
     RECT  33.816 9.107 34.8 15.637 ;
     RECT  26.76 9.589 28.032 10.597 ;
     RECT  10.704 9.731 10.728 10.357 ;
     RECT  24.312 10.307 25.296 19.813 ;
     RECT  38.472 10.307 39.696 15.877 ;
     RECT  27.048 10.597 28.032 11.459 ;
     RECT  36.168 10.597 37.296 13.045 ;
     RECT  6.408 10.643 7.8 10.883 ;
     RECT  26.76 11.459 28.032 16.019 ;
     RECT  5.592 12.611 5.688 13.139 ;
     RECT  5.664 13.139 5.688 13.621 ;
     RECT  17.136 13.187 17.568 13.669 ;
     RECT  18.912 13.667 20.256 14.773 ;
     RECT  16.344 13.669 17.568 14.867 ;
     RECT  2.712 13.715 3.528 14.197 ;
     RECT  2.712 14.197 3.984 17.077 ;
     RECT  5.688 14.533 7.104 18.083 ;
     RECT  19.08 14.773 20.256 16.309 ;
     RECT  25.32 14.963 26.352 16.981 ;
     RECT  36.168 15.059 37.392 16.501 ;
     RECT  30.648 15.829 31.872 16.405 ;
     RECT  31.896 15.829 33.072 17.747 ;
     RECT  26.616 16.019 28.032 18.275 ;
     RECT  14.376 16.405 15.84 17.699 ;
     RECT  20.28 16.453 21.552 17.171 ;
     RECT  15.864 16.501 17.136 17.699 ;
     RECT  36.168 16.501 37.296 17.605 ;
     RECT  25.368 16.981 26.352 17.699 ;
     RECT  2.712 17.651 3.984 20.003 ;
     RECT  25.368 17.699 26.592 18.275 ;
     RECT  30.552 17.699 31.872 17.747 ;
     RECT  11.112 17.845 12.528 18.757 ;
     RECT  4.584 18.181 5.664 19.379 ;
     RECT  30.024 18.419 30.36 18.851 ;
     RECT  20.28 18.709 21.6 19.333 ;
     RECT  29.976 18.851 30.36 19.909 ;
     RECT  20.808 19.811 22.32 23.365 ;
     RECT  2.712 20.003 2.808 20.053 ;
     RECT  19.464 20.723 20.784 23.365 ;
     RECT  10.32 21.155 10.896 21.253 ;
     RECT  8.328 21.253 9.312 23.365 ;
     RECT  9.336 21.253 10.896 22.501 ;
     RECT  4.92 21.637 6.048 23.365 ;
     RECT  14.328 21.683 14.376 22.789 ;
     RECT  35.208 21.923 36.24 22.259 ;
     RECT  24.312 22.259 25.392 23.365 ;
     RECT  35.208 22.259 36.72 23.365 ;
     RECT  9.912 22.501 10.896 23.365 ;
     RECT  3.432 22.741 4.8 22.981 ;
     RECT  35.208 23.365 36.288 23.701 ;
  END
END dsfd_vm_fxa
END LIBRARY
